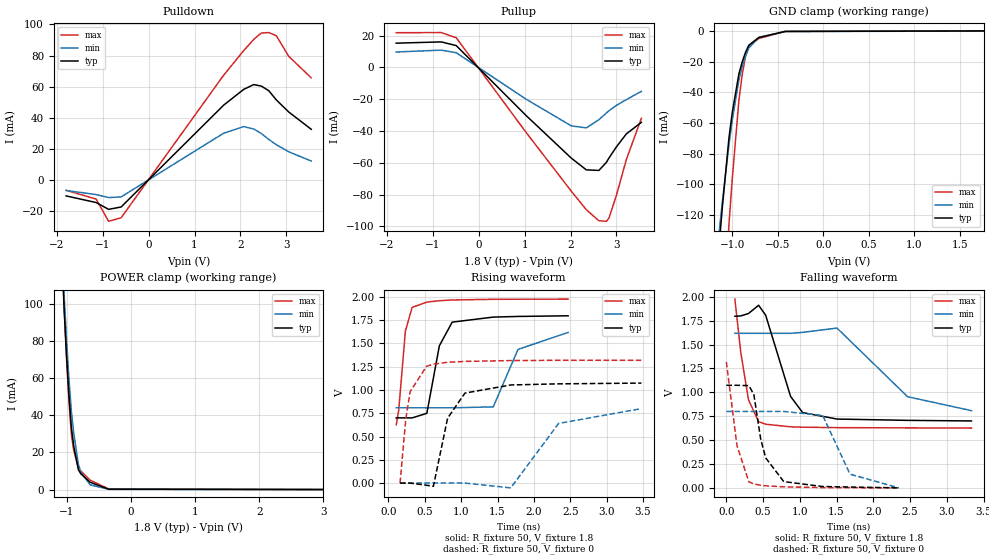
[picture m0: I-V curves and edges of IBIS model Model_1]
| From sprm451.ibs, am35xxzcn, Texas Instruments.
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| Model based on original model for BC1833DV40CTPBFHP18LL_7LM
|   Sub model HP18LL_7LM_PD_ON_1P8
[model]   Model_1
|[Description]  1.8V-I/O-PD-X
|[Input Load]   PD
|[Output Drive]
|Voltage   1.8V
|Mode   I/O
Model_type   I/O
Polarity   Non-Inverting
Enable   Active-Low
Vinl =  0.63V
Vinh =  1.17V
Cref =  15pF
Rref =  100.0000M
Vref =  0V
Vmeas =  0.9
C_comp   2.232809p   2.073051p   2.295852p
[Model Spec]
Vinl   0.63V   0.567V   0.693V
Vinh   1.17V   1.053V   1.287V
[Temperature Range]   25   125   -40
[Voltage Range]   1.8   1.62   1.98
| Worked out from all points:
|   slope of the pulldown table from 0 to 0.27 V, typ, clamps not added: 31.5 ohm
|   slope of the pullup table from 0 to 0.27 V, typ, clamps not added: 33.5 ohm
|   GND clamp passes 1 mA (typ) near -0.54 V on its own axis
|   POWER clamp passes 1 mA (typ) near -0.48 V on its own axis
|   rising waveform, R_fixture 50, V_fixture 1.8: 20-80 % time 168ps typ, 247ps min, 94.3ps max; typ from 0.701 V to 1.8 V
|   rising waveform, R_fixture 50, V_fixture 0: 20-80 % time 225ps typ, 472ps min, 131ps max; typ from 0 V to 1.07 V
|   falling waveform, R_fixture 50, V_fixture 1.8: 20-80 % time 282ps typ, 646ps min, 154ps max; typ from 1.8 V to 0.701 V
|   falling waveform, R_fixture 50, V_fixture 0: 20-80 % time 201ps typ, 246ps min, 144ps max; typ from 1.07 V to 0 V
[POWER_clamp]
-1.8V     842.4mA    869.2mA    912.8mA
-1.073V   123.6mA    130.9mA    129mA
-1.036V   94.8mA     102.9mA    96.52mA
-1V       70.82mA    79.68mA    69.62mA
-963.6mV  50.42mA    59.5mA     47.43mA
-927.3mV  33.6mA     42.32mA    29.95mA
-890.9mV  23.68mA    30.78mA    21.23mA
-818.2mV  10.84mA    13.86mA    11.65mA
-781.8mV  8.6mA      9.562mA    10.12mA
-636.4mV  3.971mA    2.6mA      5.151mA
-345.5mV  233.4uA    144.1uA    344.8uA
3.6V      0A         0A         0A
[Pulldown]
-1.8V     -10.48mA   -6.986mA   -6.871mA
-1.145V   -14.76mA   -9.635mA   -12.53mA
-872.7mV  -19.16mA   -11.57mA   -26.86mA
-600mV    -17.63mA   -11.14mA   -24.6mA
1.636V    48.02mA    29.94mA    67.34mA
2.073V    58.18mA    34.17mA    83.16mA
2.291V    61.26mA    32.65mA    90.37mA
2.455V    60.31mA    29.78mA    94.52mA
2.618V    57.35mA    25.94mA    94.79mA
2.782V    51.42mA    22.55mA    92.8mA
3.055V    43.58mA    17.93mA    79.45mA
3.545V    32.44mA    11.99mA    65.6mA
[Pullup]
-1.8V     15.25mA    9.689mA    21.84mA
-818.2mV  16.04mA    10.87mA    21.92mA
-490.9mV  13.71mA    9.212mA    18.64mA
1.036V    -30.4mA    -20.07mA   -41.09mA
2.018V    -57.11mA   -36.81mA   -77.94mA
2.345V    -64.48mA   -38.06mA   -89.56mA
2.618V    -64.84mA   -32.95mA   -96.49mA
2.782V    -59.78mA   -28.7mA    -96.85mA
2.836V    -57.13mA   -27.34mA   -95.02mA
3V        -50.06mA   -23.92mA   -80.63mA
3.218V    -41.82mA   -20.26mA   -57.92mA
3.545V    -34.58mA   -15.09mA   -32.06mA
[GND_clamp]
-1.8V     -697.8mA   -553.2mA   -1.259A
-1.145V   -140.7mA   -131.7mA   -248.3mA
-1.109V   -115.1mA   -111.6mA   -203.3mA
-1.036V   -69.61mA   -74.07mA   -125.9mA
-1V       -53.18mA   -58.25mA   -96.53mA
-927.3mV  -27.97mA   -31.86mA   -45.36mA
-890.9mV  -20.15mA   -23.34mA   -28.45mA
-854.5mV  -13.89mA   -16.39mA   -16.55mA
-818.2mV  -9.202mA   -11.02mA   -9.655mA
-709.1mV  -4.178mA   -4.041mA   -4.8mA
-418.2mV  -167.7uA   -232.8uA   -162.2uA
1.764V    148.6uA    81.78uA    236.4uA
[Ramp]
dV/dt_f 0.72573481/0.29560081n 0.53569302/0.67555475n 0.88861394/0.16164786n
dV/dt_r 0.67824841/0.22489373n 0.51280373/0.47254638n 0.81071552/0.13099315n
R_load = 50
[Rising Waveform]
R_fixture = 50
V_fixture = 1.8
V_fixture_min = 1.62
V_fixture_max = 1.98
106.8ps   700.5mV    808.2mV    625.6mV
140.8ps   700.5mV    808.2mV    778mV
233.1ps   700.6mV    808.2mV    1.632V
325.1ps   700mV      808.2mV    1.887V
528.1ps   749.6mV    808.2mV    1.944V
700.1ps   1.475V     808.2mV    1.959V
876.5ps   1.729V     808.2mV    1.967V
1.441ns   1.783V     818.9mV    1.974V
1.781ns   1.79V      1.436V     1.975V
2.47ns    1.797V     1.618V     1.976V
[Rising Waveform]
R_fixture = 50
V_fixture = 0
V_fixture_min = 0
V_fixture_max = 0
159.8ps   9.235nV    99.72nV    8.891nV
238ps     20.47uV    2.982uV    683.5mV
298.9ps   -444uV     1.923uV    982.8mV
525ps     -23.12mV   -556.3nV   1.255V
617.8ps   -34.89mV   30.45nV    1.277V
813.8ps   698.5mV    -1.58uV    1.298V
1.052ns   966.7mV    -195.9uV   1.307V
1.682ns   1.054V     -51.29mV   1.316V
2.339ns   1.066V     640.6mV    1.319V
3.477ns   1.074V     799.9mV    1.319V
[Falling Waveform]
R_fixture = 50
V_fixture = 1.8
V_fixture_min = 1.62
V_fixture_max = 1.98
116.4ps   1.797V     1.618V     1.976V
196.1ps   1.8V       1.618V     1.422V
300.8ps   1.825V     1.618V     923.4mV
439.3ps   1.912V     1.618V     693.4mV
535.4ps   1.807V     1.618V     666.2mV
874.3ps   957.4mV    1.618V     639mV
1.038ns   788mV      1.628V     635.3mV
1.506ns   720.5mV    1.673V     630.5mV
2.466ns   706.7mV    954.5mV    628.1mV
3.336ns   700.5mV    808.2mV    625.6mV
[Falling Waveform]
R_fixture = 50
V_fixture = 0
V_fixture_min = 0
V_fixture_max = 0
0s        1.074V     799.9mV    1.319V
145.1ps   1.074V     799.9mV    440.9mV
307.1ps   1.07V      799.9mV    62.25mV
374.5ps   976.4mV    799.9mV    41.47mV
466.4ps   516.4mV    799.9mV    27.62mV
535ps     314.5mV    799.9mV    21.5mV
781.5ps   65.48mV    799.9mV    10.9mV
1.311ns   14.01mV    758.7mV    2.742mV
1.683ns   8.619mV    143.3mV    921.5uV
2.347ns   9.235nV    99.72nV    8.891nV
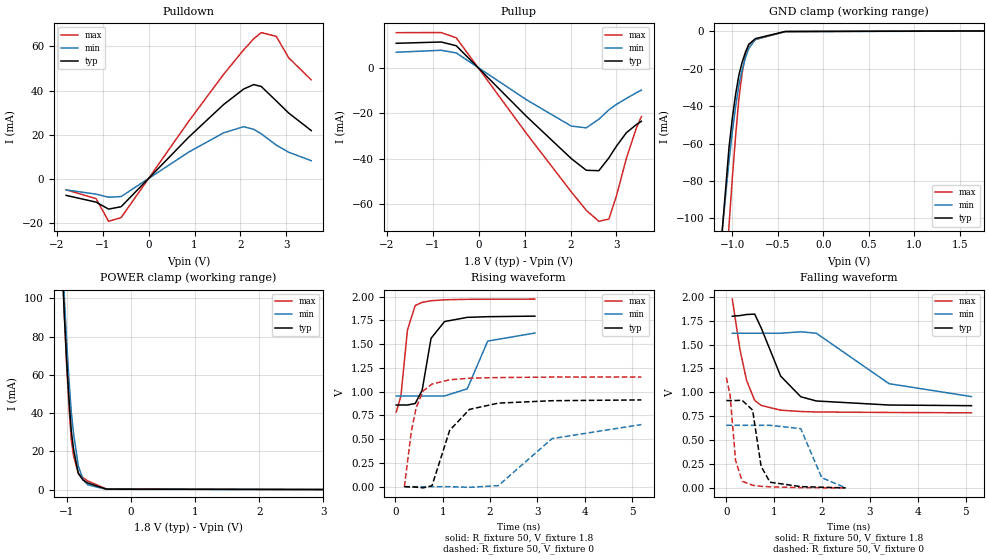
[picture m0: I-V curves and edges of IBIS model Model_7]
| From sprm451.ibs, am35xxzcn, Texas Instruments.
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| Model based on original model for BC1833DV50BTPBFZP18LL_7LM
|   Sub model ZP18LL_7LM_PD_ON_1P8
[model]   Model_7
|[Description]  1.8V-I/O-PD-X
|[Input Load]   PD
|[Output Drive]
|Voltage   1.8V
|Mode   I/O
Model_type   I/O
Polarity   Non-Inverting
Enable   Active-Low
Vinl =  0.63V
Vinh =  1.17V
Cref =  15pF
Rref =  100.0000M
Vref =  0V
Vmeas =  0.9
C_comp   1.952094p   1.82457p   1.99685p
[Model Spec]
Vinl   0.63V   0.567V   0.693V
Vinh   1.17V   1.053V   1.287V
[Temperature Range]   25   125   -40
[Voltage Range]   1.8   1.62   1.98
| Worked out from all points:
|   slope of the pulldown table from 0 to 0.27 V, typ, clamps not added: 44.6 ohm
|   slope of the pullup table from 0 to 0.27 V, typ, clamps not added: 47.6 ohm
|   GND clamp passes 1 mA (typ) near -0.57 V on its own axis
|   POWER clamp passes 1 mA (typ) near -0.50 V on its own axis
|   rising waveform, R_fixture 50, V_fixture 1.8: 20-80 % time 215ps typ, 285ps min, 155ps max; typ from 0.86 V to 1.8 V
|   rising waveform, R_fixture 50, V_fixture 0: 20-80 % time 445ps typ, 984ps min, 246ps max; typ from 0 V to 0.914 V
|   falling waveform, R_fixture 50, V_fixture 1.8: 20-80 % time 529ps typ, 1.21ns min, 284ps max; typ from 1.8 V to 0.86 V
|   falling waveform, R_fixture 50, V_fixture 0: 20-80 % time 163ps typ, 254ps min, 124ps max; typ from 0.914 V to 0 V
[POWER_clamp]
-1.8V     833.5mA    863.2mA    901.5mA
-1.073V   119.6mA    128.2mA    123.8mA
-1.036V   90.99mA    100.3mA    91.56mA
-1V       67.21mA    77.3mA     64.92mA
-963.6mV  47.03mA    57.27mA    42.99mA
-927.3mV  30.43mA    40.25mA    25.78mA
-890.9mV  20.75mA    28.88mA    17.36mA
-818.2mV  8.417mA    12.3mA     8.465mA
-745.5mV  5.011mA    5.192mA    6.262mA
-672.7mV  3.472mA    2.533mA    4.531mA
-381.8mV  258uA      159.8uA    367.6uA
3.6V      0A         0A         0A
[Pulldown]
-1.8V     -7.339mA   -4.872mA   -4.803mA
-1.145V   -10.39mA   -6.769mA   -8.819mA
-872.7mV  -13.54mA   -8.159mA   -19.05mA
-600mV    -12.46mA   -7.873mA   -17.38mA
872.7mV   18.95mA    12.21mA    26.11mA
1.636V    33.73mA    20.94mA    47.4mA
2.073V    40.73mA    23.7mA     58.46mA
2.291V    42.72mA    22.53mA    63.43mA
2.455V    41.87mA    20.47mA    66.23mA
2.782V    35.36mA    15.4mA     64.52mA
3.055V    29.83mA    12.14mA    54.79mA
3.545V    21.95mA    8.339mA    44.87mA
[Pullup]
-1.8V     10.72mA    6.784mA    15.4mA
-818.2mV  11.29mA    7.651mA    15.44mA
-490.9mV  9.653mA    6.484mA    13.12mA
1.036V    -21.34mA   -14.06mA   -28.84mA
2.018V    -39.99mA   -25.69mA   -54.63mA
2.345V    -45.12mA   -26.45mA   -62.75mA
2.618V    -45.29mA   -22.66mA   -67.55mA
2.836V    -39.69mA   -18.55mA   -66.59mA
3V        -34.54mA   -16.15mA   -56.48mA
3.218V    -28.61mA   -13.52mA   -39.88mA
3.436V    -25.01mA   -11.02mA   -26.56mA
3.545V    -23.56mA   -9.84mA    -21.49mA
[GND_clamp]
-1.8V     -667.9mA   -536.4mA   -1.146A
-1.109V   -105.7mA   -105.8mA   -172.9mA
-1.036V   -62.17mA   -69.32mA   -103.8mA
-1V       -46.71mA   -54.02mA   -78.82mA
-963.6mV  -33.8mA    -40.46mA   -56.21mA
-927.3mV  -23.44mA   -28.63mA   -35.97mA
-890.9mV  -16.49mA   -20.59mA   -22.18mA
-854.5mV  -11.01mA   -14.09mA   -12.57mA
-818.2mV  -7.007mA   -9.141mA   -7.128mA
-745.5mV  -3.917mA   -4.386mA   -4.424mA
-418.2mV  -145.2uA   -181.7uA   -152.2uA
1.764V    148.6uA    81.64uA    236.4uA
[Ramp]
dV/dt_f 0.57820343/0.53321315n 0.41153382/1.2211474n 0.72337916/0.28337698n
dV/dt_r 0.56277196/0.44507689n 0.40444103/0.98176965n 0.70129767/0.24651408n
R_load = 50
[Rising Waveform]
R_fixture = 50
V_fixture = 1.8
V_fixture_min = 1.62
V_fixture_max = 1.98
20.99ps   860mV      955mV      785.5mV
120.2ps   860mV      955mV      955mV
258.7ps   859.9mV    955mV      1.651V
422.2ps   876.3mV    955mV      1.908V
567.8ps   1.014V     955mV      1.941V
755.8ps   1.562V     955mV      1.958V
1.041ns   1.739V     955.1mV    1.968V
1.52ns    1.783V     1.031V     1.973V
1.951ns   1.79V      1.533V     1.974V
2.947ns   1.796V     1.618V     1.975V
[Rising Waveform]
R_fixture = 50
V_fixture = 0
V_fixture_min = 0
V_fixture_max = 0
193.4ps   9.192nV    85.66nV    10.64nV
340.1ps   -2.557mV   2.165uV    583.1mV
442.4ps   -5.376mV   132.4nV    832.4mV
588.8ps   -12.42mV   -1.579uV   1.007V
775.2ps   9.464mV    -2.483uV   1.081V
1.149ns   593.3mV    -171.1uV   1.126V
1.568ns   814.2mV    -6.735mV   1.142V
2.176ns   879.9mV    11.46mV    1.149V
3.31ns    905.4mV    506.5mV    1.154V
5.193ns   913.5mV    654.1mV    1.154V
[Falling Waveform]
R_fixture = 50
V_fixture = 1.8
V_fixture_min = 1.62
V_fixture_max = 1.98
124.8ps   1.796V     1.618V     1.975V
284.6ps   1.803V     1.618V     1.448V
423.8ps   1.814V     1.618V     1.123V
593.8ps   1.818V     1.618V     914.3mV
731ps     1.671V     1.618V     862.3mV
1.135ns   1.17V      1.618V     813.1mV
1.557ns   953.1mV    1.633V     799mV
1.882ns   909.2mV    1.618V     794.1mV
3.402ns   866.8mV    1.09V      788.8mV
5.125ns   860mV      955mV      785.5mV
[Falling Waveform]
R_fixture = 50
V_fixture = 0
V_fixture_min = 0
V_fixture_max = 0
0s        913.5mV    654.1mV    1.154V
77.74ps   913.4mV    654.1mV    974.7mV
192.8ps   914.2mV    654.1mV    288.5mV
330.9ps   915.9mV    654.1mV    69.36mV
549.3ps   814mV      654.1mV    26.94mV
726.8ps   225.2mV    654.1mV    16.41mV
913ps     58.95mV    654.4mV    10.83mV
1.556ns   12.95mV    618.9mV    1.852mV
1.994ns   6.897mV    106.5mV    536.1uV
2.497ns   9.192nV    85.66nV    10.64nV
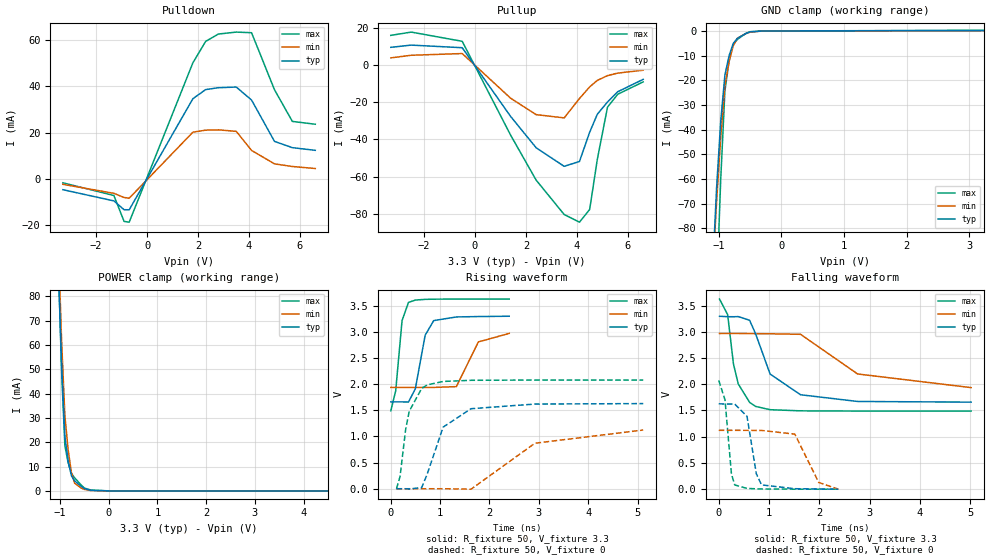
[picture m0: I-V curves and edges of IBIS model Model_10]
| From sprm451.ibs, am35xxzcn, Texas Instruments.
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| Model based on original model for BC1833DV50BTPBFZP18LL_7LM
|   Sub model ZP18LL_7LM_PD_ON_3P3
[model]   Model_10
|[Description]  3.3V-I/O-PD-X
|[Input Load]   PD
|[Output Drive]
|Voltage   3.3V
|Mode   I/O
Model_type   I/O
Polarity   Non-Inverting
Enable   Active-Low
Vinl =  0.8V
Vinh =  2V
Cref =  15pF
Rref =  100.0000M
Vref =  0V
Vmeas =  1.65
C_comp   1.683006p   1.492615p   1.787227p
[Model Spec]
Vinl   0.8V   0.8V   0.8V
Vinh   2V   2V   2V
[Temperature Range]   25   125   -40
[Voltage Range]   3.3   2.97   3.63
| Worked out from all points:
|   slope of the pulldown table from 0 to 0.495 V, typ, clamps not added: 44.6 ohm
|   slope of the pullup table from 0 to 0.495 V, typ, clamps not added: 49.2 ohm
|   GND clamp passes 1 mA (typ) near -0.56 V on its own axis
|   POWER clamp passes 1 mA (typ) near -0.50 V on its own axis
|   rising waveform, R_fixture 50, V_fixture 3.3: 20-80 % time 192ps typ, 277ps min, 121ps max; typ from 1.66 V to 3.3 V
|   rising waveform, R_fixture 50, V_fixture 0: 20-80 % time 427ps typ, 976ps min, 232ps max; typ from 0 V to 1.63 V
|   falling waveform, R_fixture 50, V_fixture 3.3: 20-80 % time 507ps typ, 1ns min, 228ps max; typ from 3.3 V to 1.66 V
|   falling waveform, R_fixture 50, V_fixture 0: 20-80 % time 153ps typ, 282ps min, 108ps max; typ from 1.63 V to 0 V
[POWER_clamp]
-3.3V     2.414A     2.855A     2.597A
-1.033V   91.38mA    100.8mA    92.09mA
-966.7mV  51.62mA    61.2mA     48.76mA
-900mV    22.31mA    30.86mA    18.57mA
-833.3mV  12.32mA    16.85mA    11.59mA
-766.7mV  6.266mA    7.628mA    7.19mA
-700mV    4.145mA    3.179mA    5.382mA
-566.7mV  1.918mA    1.21mA     2.445mA
-500mV    988.1uA    615.4uA    1.197mA
-366.7mV  251uA      160.8uA    340.6uA
33.33mV   0A         0A         0A
6.6V      0A         0A         0A
[Pulldown]
-3.3V     -4.655mA   -2.337mA   -1.677mA
-1.3V     -9.504mA   -6.223mA   -7.163mA
-900mV    -13.3mA    -8.026mA   -18.36mA
-700mV    -13.35mA   -8.345mA   -18.7mA
1.8V      34.68mA    20.21mA    50.21mA
2.3V      38.61mA    21.07mA    59.44mA
2.8V      39.41mA    21.2mA     62.61mA
3.5V      39.7mA     20.55mA    63.45mA
4.1V      34.08mA    12.32mA    63.18mA
5V        16.21mA    6.501mA    38.53mA
5.7V      13.51mA    5.366mA    24.85mA
6.6V      12.35mA    4.495mA    23.63mA
[Pullup]
-3.3V     9.687mA    4.009mA    16.14mA
-2.5V     10.89mA    5.407mA    17.91mA
-500mV    9.485mA    6.336mA    12.94mA
1.4V      -27.6mA    -17.76mA   -37.69mA
2.4V      -44.47mA   -26.6mA    -61.92mA
3.5V      -54.49mA   -28.37mA   -80.48mA
4.1V      -51.87mA   -17.91mA   -84.62mA
4.5V      -36.09mA   -11.65mA   -77.77mA
4.8V      -26.39mA   -8.135mA   -50.71mA
5.2V      -19.78mA   -5.578mA   -22.57mA
5.6V      -14.26mA   -4.206mA   -15.61mA
6.6V      -7.577mA   -2.662mA   -8.942mA
[GND_clamp]
-3.3V     -1.975A    -1.766A    -3.378A
-1.1V     -99.4mA    -100.8mA   -162mA
-1.033V   -63.74mA   -69.32mA   -106.1mA
-966.7mV  -36.57mA   -43.05mA   -60.18mA
-900mV    -17.89mA   -22.01mA   -24.33mA
-833.3mV  -10.02mA   -12.39mA   -12.36mA
-766.7mV  -5.065mA   -6.03mA    -5.397mA
-700mV    -3.03mA    -2.946mA   -3.429mA
-566.7mV  -1.071mA   -1.108mA   -1.034mA
-500mV    -408.8uA   -526.2uA   -330.7uA
-300mV    -30.43uA   -31.39uA   -39.7uA
3.233V    152.3uA    93.49uA    242.6uA
[Ramp]
dV/dt_f  0.9825446/0.50371119n 0.61884461/0.98346485n  1.2814013/0.22625728n
dV/dt_r 0.98086665/0.42362929n  0.6781094/0.97314198n   1.251215/0.23061983n
R_load = 50
[Rising Waveform]
R_fixture = 50
V_fixture = 3.3
V_fixture_min = 2.97
V_fixture_max = 3.63
613.4fs   1.659V     1.936V     1.489V
99.11ps   1.659V     1.936V     1.868V
228.5ps   1.659V     1.936V     3.213V
359.1ps   1.657V     1.936V     3.561V
497.8ps   1.91V      1.936V     3.605V
696.4ps   2.933V     1.936V     3.618V
870.1ps   3.213V     1.936V     3.622V
1.329ns   3.282V     1.951V     3.624V
1.774ns   3.29V      2.805V     3.624V
2.4ns     3.296V     2.968V     3.624V
[Rising Waveform]
R_fixture = 50
V_fixture = 0
V_fixture_min = 0
V_fixture_max = 0
115.3ps   7.935nV    106nV      4.134nV
188ps     4.843uV    -370.3nV   234.2mV
300.1ps   -248.5uV   -461.2nV   1.126V
373.2ps   -2.67mV    -60.64nV   1.479V
625.5ps   20.96mV    144.5nV    1.916V
738.1ps   279.9mV    9.941nV    1.984V
1.061ns   1.178V     25.17uV    2.05V
1.627ns   1.529V     -8.018mV   2.072V
2.921ns   1.618V     869.5mV    2.077V
5.115ns   1.627V     1.122V     2.076V
[Falling Waveform]
R_fixture = 50
V_fixture = 3.3
V_fixture_min = 2.97
V_fixture_max = 3.63
15.81ps   3.296V     2.968V     3.624V
177.4ps   3.288V     2.968V     3.327V
292.3ps   3.287V     2.968V     2.388V
387.8ps   3.29V      2.968V     2.006V
613.7ps   3.22V      2.966V     1.655V
733.8ps   2.96V      2.964V     1.577V
1.021ns   2.194V     2.962V     1.515V
1.626ns   1.8V       2.952V     1.493V
2.76ns    1.672V     2.196V     1.489V
5.016ns   1.659V     1.936V     1.489V
[Falling Waveform]
R_fixture = 50
V_fixture = 0
V_fixture_min = 0
V_fixture_max = 0
0s        1.627V     1.122V     2.076V
124.2ps   1.623V     1.122V     1.704V
252.7ps   1.623V     1.122V     288.7mV
318.3ps   1.623V     1.122V     80.41mV
562.2ps   1.388V     1.121V     14.58mV
746.4ps   297.2mV    1.12V      6.518mV
849.5ps   81.65mV    1.12V      3.807mV
1.512ns   8.88mV     1.049V     121.1uV
1.987ns   3.244mV    128.1mV    14.14uV
2.377ns   7.935nV    106nV      4.134nV
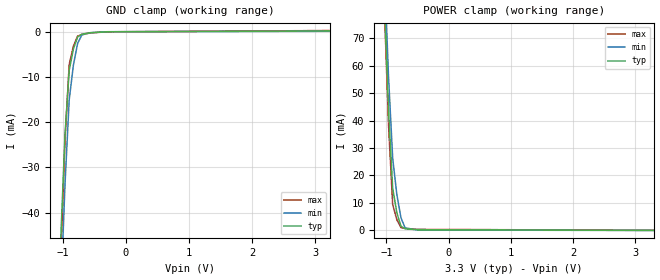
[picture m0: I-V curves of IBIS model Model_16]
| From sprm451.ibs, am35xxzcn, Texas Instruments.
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| Model based on original model for IC1833DVTPBFZP18LL_7LM
|   Sub model 7LM_!PI_!PUPDSEL_3P3
[model]   Model_16
|[Description]  3.3V-INPUT-PD-X
|[Input Load]   PD
|[Output Drive]
|Voltage   3.3V
|Mode   INPUT
Model_type   Input
Polarity   Non-Inverting
Vinl =  0.8V
Vinh =  2V
C_comp   1.012258p   0.8890016p   1.091755p
[Model Spec]
Vinl   0.8V   0.8V   0.8V
Vinh   2V   2V   2V
[Temperature Range]   25   125   -40
[Voltage Range]   3.3   2.97   3.63
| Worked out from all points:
|   GND clamp passes 1 mA (typ) near -0.75 V on its own axis
|   POWER clamp passes 1 mA (typ) near -0.73 V on its own axis
[POWER_clamp]
-3.3V     2.37A      2.826A     2.542A
-1.033V   82.55mA    94.89mA    80.63mA
-966.7mV  43.74mA    56mA       38.47mA
-900mV    15.37mA    26.34mA    9.443mA
-833.3mV  6.477mA    13.09mA    3.921mA
-766.7mV  1.541mA    4.609mA    1.021mA
-700mV    560.4uA    907.9uA    743.2uA
-500mV    249.8uA    143.8uA    371.7uA
3.3V      -147.5pA   -31.33uA   27.53uA
[GND_clamp]
-3.3V     -1.792A    -1.668A    -2.631A
-1.033V   -45.54mA   -57.75mA   -50.28mA
-966.7mV  -22.83mA   -33.82mA   -24.05mA
-900mV    -8.522mA   -15.05mA   -7.278mA
-833.3mV  -3.829mA   -7.369mA   -3.202mA
-766.7mV  -1.175mA   -2.599mA   -991.4uA
-700mV    -560.2uA   -745.4uA   -646.9uA
-566.7mV  -249.1uA   -233.9uA   -286.4uA
-300mV    -29.03uA   -23.37uA   -39.39uA
3.233V    152.3uA    84.63uA    242.6uA
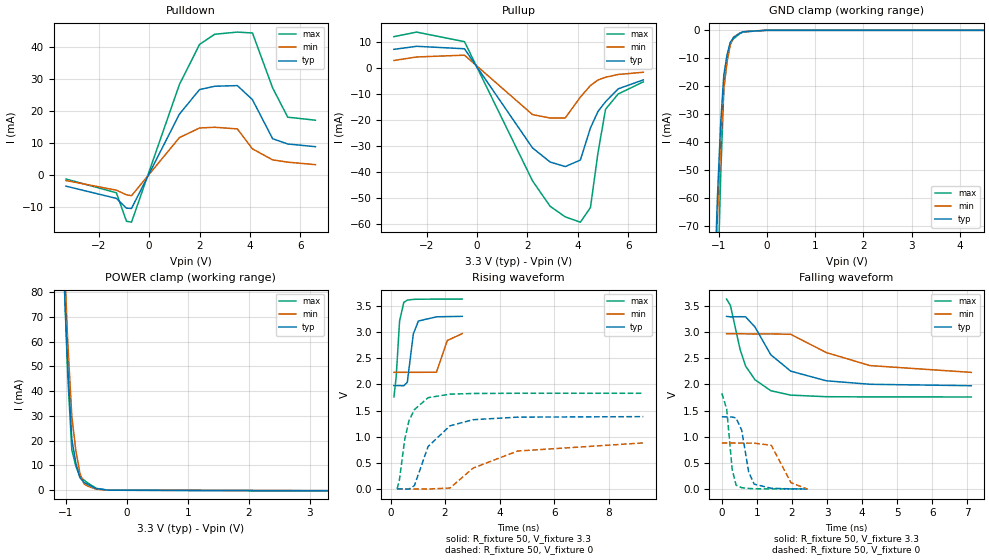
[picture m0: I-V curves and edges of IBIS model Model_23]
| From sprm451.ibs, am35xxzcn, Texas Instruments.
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| Model based on original model for BC1833DV65ATPBFHP18LL_7LM_X50
|   Sub model LL_7LM_X50_PU_ON_3P3
[model]   Model_23
|[Description]  3.3V-I/O-PU-X
|[Input Load]   PU
|[Output Drive]
|Voltage   3.3V
|Mode   I/O
Model_type   I/O
Polarity   Non-Inverting
Enable   Active-Low
Vinl =  0.8V
Vinh =  2V
Cref =  15pF
Rref =  100.0000M
Vref =  0V
Vmeas =  1.65
C_comp   1.569055p   1.388637p   1.6677p
[Model Spec]
Vinl   0.8V   0.8V   0.8V
Vinh   2V   2V   2V
[Temperature Range]   25   125   -40
[Voltage Range]   3.3   2.97   3.63
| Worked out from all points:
|   slope of the pulldown table from 0 to 0.495 V, typ, clamps not added: 57.2 ohm
|   slope of the pullup table from 0 to 0.495 V, typ, clamps not added: 64.6 ohm
|   GND clamp passes 1 mA (typ) near -0.56 V on its own axis
|   POWER clamp passes 1 mA (typ) near -0.53 V on its own axis
|   rising waveform, R_fixture 50, V_fixture 3.3: 20-80 % time 188ps typ, 267ps min, 136ps max; typ from 1.98 V to 3.3 V
|   rising waveform, R_fixture 50, V_fixture 0: 20-80 % time 836ps typ, 1.93ns min, 444ps max; typ from 0.005 V to 1.39 V
|   falling waveform, R_fixture 50, V_fixture 3.3: 20-80 % time 1.01ns typ, 1.63ns min, 553ps max; typ from 3.3 V to 1.98 V
|   falling waveform, R_fixture 50, V_fixture 0: 20-80 % time 210ps typ, 357ps min, 143ps max; typ from 1.39 V to 0.005 V
[POWER_clamp]
-3.3V     2.404A     2.849A     2.585A
-1.033V   89.24mA    99.32mA    89.3mA
-966.7mV  49.69mA    59.91mA    46.23mA
-900mV    20.59mA    29.73mA    16.29mA
-833.3mV  10.84mA    15.9mA     9.63mA
-766.7mV  5.043mA    6.847mA    5.566mA
-700mV    3.181mA    2.571mA    4.1mA
-633.3mV  2.248mA    1.617mA    2.875mA
-500mV    675.7uA    429.5uA    770.8uA
-300mV    22.84uA    18.84uA    28.19uA
3.3V      -177.5uA   -131.7uA   -277.3uA
[Pulldown]
-3.3V     -3.482mA   -1.731mA   -1.253mA
-1.3V     -7.3mA     -4.736mA   -5.547mA
-900mV    -10.35mA   -6.182mA   -14.42mA
-700mV    -10.42mA   -6.462mA   -14.71mA
1.2V      18.95mA    11.64mA    28.17mA
2V        26.61mA    14.65mA    40.68mA
2.6V      27.65mA    14.87mA    43.85mA
3.5V      27.86mA    14.36mA    44.53mA
4.1V      23.47mA    8.141mA    44.25mA
4.9V      11.31mA    4.711mA    27.15mA
5.5V      9.66mA     3.997mA    18.01mA
6.6V      8.818mA    3.224mA    17.07mA
[Pullup]
-3.3V     7.018mA    2.752mA    11.89mA
-2.4V     8.195mA    4.095mA    13.65mA
-500mV    7.249mA    4.793mA    9.977mA
2.2V      -30.8mA    -18.02mA   -43.45mA
2.9V      -36.22mA   -19.34mA   -53.21mA
3.5V      -37.97mA   -19.31mA   -57.28mA
4.1V      -35.47mA   -11.3mA    -59.32mA
4.5V      -23.14mA   -6.857mA   -53.72mA
4.8V      -16.8mA    -4.734mA   -32.6mA
5.1V      -13.06mA   -3.688mA   -15.95mA
5.6V      -8.137mA   -2.623mA   -10.11mA
6.6V      -4.691mA   -1.758mA   -5.452mA
[GND_clamp]
-3.3V     -1.939A    -1.746A    -3.236A
-1.1V     -94.85mA   -97.92mA   -147.6mA
-1.033V   -60.11mA   -66.92mA   -95.49mA
-966.7mV  -33.84mA   -41.13mA   -53.35mA
-900mV    -16.04mA   -20.57mA   -21.16mA
-833.3mV  -8.82mA    -11.35mA   -10.72mA
-766.7mV  -4.347mA   -5.329mA   -4.693mA
-700mV    -2.622mA   -2.512mA   -3.078mA
-566.7mV  -1.044mA   -980.6uA   -1.151mA
-500mV    -516.4uA   -513.3uA   -592uA
-33.33mV  0A         0A         0A
6.6V      0A         0A         0A
[Ramp]
dV/dt_f 0.79376008/1.0080993n 0.44324543/1.6259422n  1.1206463/0.55232791n
dV/dt_r 0.83122681/0.83531775n 0.53087089/1.9016899n  1.0976582/0.44436463n
R_load = 50
[Rising Waveform]
R_fixture = 50
V_fixture = 3.3
V_fixture_min = 2.97
V_fixture_max = 3.63
124.5ps   1.977V     2.231V     1.762V
206ps     1.977V     2.231V     2.132V
331.8ps   1.977V     2.231V     3.209V
486.3ps   1.975V     2.231V     3.566V
616.1ps   2.04V      2.231V     3.609V
835.8ps   2.962V     2.231V     3.624V
1.021ns   3.211V     2.231V     3.627V
1.686ns   3.291V     2.234V     3.629V
2.081ns   3.295V     2.838V     3.63V
2.629ns   3.3V       2.97V      3.63V
[Rising Waveform]
R_fixture = 50
V_fixture = 0
V_fixture_min = 0
V_fixture_max = 0
239.7ps   4.68mV     2.797mV    6.834mV
322.9ps   4.68mV     2.797mV    164.6mV
523.5ps   3.282mV    2.797mV    956.5mV
675.8ps   -302.1uV   2.797mV    1.305V
876.4ps   68.58mV    2.797mV    1.52V
1.378ns   813.9mV    2.658mV    1.747V
2.182ns   1.21V      21.49mV    1.814V
3.026ns   1.326V     401.6mV    1.827V
4.659ns   1.375V     728mV      1.831V
9.272ns   1.385V     883mV      1.831V
[Falling Waveform]
R_fixture = 50
V_fixture = 3.3
V_fixture_min = 2.97
V_fixture_max = 3.63
134.5ps   3.3V       2.97V      3.63V
243.7ps   3.29V      2.97V      3.511V
521.4ps   3.294V     2.969V     2.667V
677.8ps   3.291V     2.966V     2.351V
945.4ps   3.096V     2.964V     2.09V
1.394ns   2.568V     2.966V     1.882V
1.965ns   2.254V     2.957V     1.797V
2.975ns   2.071V     2.61V      1.767V
4.22ns    2.004V     2.361V     1.763V
7.11ns    1.977V     2.231V     1.762V
[Falling Waveform]
R_fixture = 50
V_fixture = 0
V_fixture_min = 0
V_fixture_max = 0
0s        1.385V     883mV      1.831V
138.9ps   1.381V     883mV      1.532V
294.5ps   1.38V      883.1mV    379.8mV
406.7ps   1.36V      882.6mV    80.15mV
566.9ps   1.127V     881.8mV    30mV
764.5ps   331.8mV    881.1mV    16.47mV
919.8ps   99.81mV    881.2mV    11.2mV
1.41ns    19.4mV     840.4mV    7.219mV
1.97ns    8.521mV    126.9mV    6.872mV
2.447ns   4.68mV     2.797mV    6.834mV
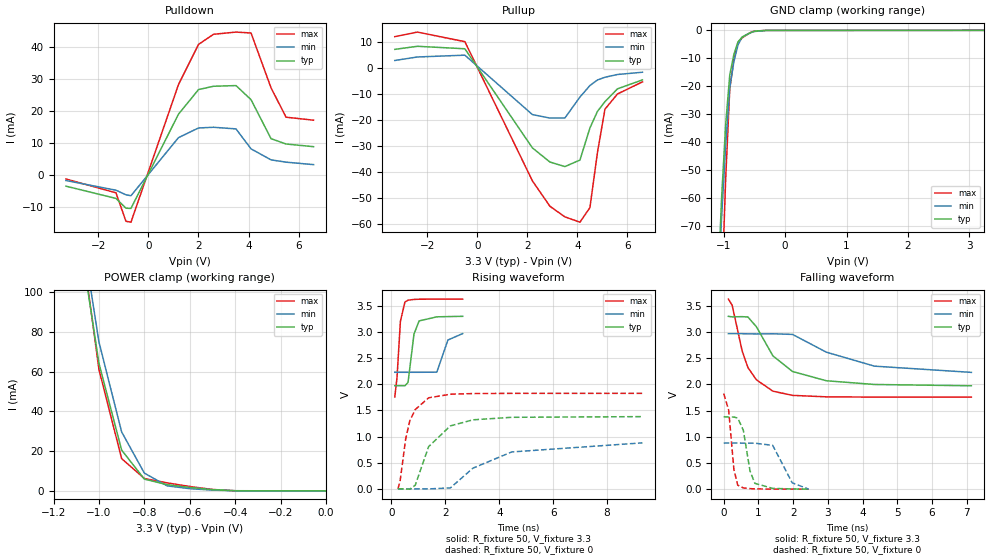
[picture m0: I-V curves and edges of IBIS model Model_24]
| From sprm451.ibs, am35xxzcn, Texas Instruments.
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| Model based on original model for BC1833DV65ATPBFHP18LL_7LM_X50
|   Sub model LM_X50_PD_PU_OFF_3P3
[model]   Model_24
|[Description]  3.3V-I/O-PI-X
|[Input Load]   PI
|[Output Drive]
|Voltage   3.3V
|Mode   I/O
Model_type   I/O
Polarity   Non-Inverting
Enable   Active-Low
Vinl =  0.8V
Vinh =  2V
Cref =  15pF
Rref =  100.0000M
Vref =  0V
Vmeas =  1.65
C_comp   1.569055p   1.388637p   1.6677p
[Model Spec]
Vinl   0.8V   0.8V   0.8V
Vinh   2V   2V   2V
[Temperature Range]   25   125   -40
[Voltage Range]   3.3   2.97   3.63
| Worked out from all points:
|   slope of the pulldown table from 0 to 0.495 V, typ, clamps not added: 57.2 ohm
|   slope of the pullup table from 0 to 0.495 V, typ, clamps not added: 64.6 ohm
|   GND clamp passes 1 mA (typ) near -0.58 V on its own axis
|   POWER clamp passes 1 mA (typ) near -0.53 V on its own axis
|   rising waveform, R_fixture 50, V_fixture 3.3: 20-80 % time 189ps typ, 268ps min, 136ps max; typ from 1.97 V to 3.3 V
|   rising waveform, R_fixture 50, V_fixture 0: 20-80 % time 841ps typ, 1.91ns min, 448ps max; typ from 0 V to 1.38 V
|   falling waveform, R_fixture 50, V_fixture 3.3: 20-80 % time 1.01ns typ, 1.64ns min, 553ps max; typ from 3.3 V to 1.97 V
|   falling waveform, R_fixture 50, V_fixture 0: 20-80 % time 210ps typ, 357ps min, 143ps max; typ from 1.38 V to 0 V
[POWER_clamp]
-3.3V     2.404A     2.849A     2.585A
-1.067V   114.2mA    123.6mA    117.4mA
-1.033V   89.22mA    99.31mA    89.28mA
-1V       64.23mA    74.99mA    61.18mA
-900mV    20.57mA    29.72mA    16.26mA
-800mV    5.954mA    8.975mA    6.268mA
-700mV    3.161mA    2.56mA     4.067mA
-600mV    1.76mA     1.128mA    2.228mA
-500mV    654.7uA    418.2uA    736.2uA
-400mV    102.9uA    85.38uA    80.17uA
0V        9.32nA     42.2nA     36.62nA
[Pulldown]
-3.3V     -3.482mA   -1.731mA   -1.253mA
-1.3V     -7.299mA   -4.736mA   -5.547mA
-900mV    -10.35mA   -6.182mA   -14.42mA
-700mV    -10.42mA   -6.462mA   -14.71mA
1.2V      18.95mA    11.64mA    28.17mA
2V        26.61mA    14.65mA    40.68mA
2.6V      27.65mA    14.87mA    43.85mA
3.5V      27.86mA    14.36mA    44.53mA
4.1V      23.47mA    8.141mA    44.25mA
4.9V      11.31mA    4.711mA    27.15mA
5.5V      9.66mA     3.997mA    18.01mA
6.6V      8.818mA    3.224mA    17.07mA
[Pullup]
-3.3V     7.018mA    2.752mA    11.89mA
-2.4V     8.195mA    4.095mA    13.65mA
-500mV    7.249mA    4.793mA    9.977mA
2.2V      -30.8mA    -18.02mA   -43.45mA
2.9V      -36.22mA   -19.34mA   -53.21mA
3.5V      -37.97mA   -19.31mA   -57.28mA
4.1V      -35.47mA   -11.3mA    -59.32mA
4.5V      -23.14mA   -6.857mA   -53.71mA
4.8V      -16.8mA    -4.734mA   -32.6mA
5.1V      -13.06mA   -3.688mA   -15.95mA
5.6V      -8.137mA   -2.623mA   -10.11mA
6.6V      -4.691mA   -1.758mA   -5.452mA
[GND_clamp]
-3.3V     -1.939A    -1.746A    -3.236A
-1.1V     -94.77mA   -97.88mA   -147.5mA
-1.033V   -60mA      -66.87mA   -95.35mA
-966.7mV  -33.71mA   -41.08mA   -53.17mA
-900mV    -15.89mA   -20.5mA    -20.9mA
-833.3mV  -8.644mA   -11.27mA   -10.41mA
-766.7mV  -4.155mA   -5.24mA    -4.355mA
-700mV    -2.422mA   -2.415mA   -2.734mA
-566.7mV  -842.1uA   -880.6uA   -805.8uA
-500mV    -315uA     -413uA     -247.5uA
-300mV    -13.91uA   -20.32uA   -14.31uA
3.233V    8.994nA    8.034uA    33.58nA
[Ramp]
dV/dt_f 0.79552329/1.0111088n 0.44388419/1.6293742n  1.1232704/0.55237363n
dV/dt_r 0.83215258/0.84027246n 0.53104946/1.9078305n  1.0994342/0.44778931n
R_load = 50
[Rising Waveform]
R_fixture = 50
V_fixture = 3.3
V_fixture_min = 2.97
V_fixture_max = 3.63
124.6ps   1.974V     2.23V      1.758V
207.3ps   1.974V     2.23V      2.134V
331.9ps   1.974V     2.23V      3.203V
499.4ps   1.972V     2.23V      3.572V
616.1ps   2.037V     2.23V      3.608V
835.9ps   2.959V     2.23V      3.623V
1.026ns   3.212V     2.23V      3.627V
1.683ns   3.29V      2.232V     3.629V
2.095ns   3.295V     2.847V     3.63V
2.642ns   3.3V       2.97V      3.63V
[Rising Waveform]
R_fixture = 50
V_fixture = 0
V_fixture_min = 0
V_fixture_max = 0
240.3ps   8.025nV    103.4nV    4.167nV
320.5ps   -166.1nV   -63.55nV   147.4mV
527.2ps   -1.449mV   27.46nV    955.3mV
681.7ps   -5.02mV    -242.9pV   1.304V
882.7ps   69.95mV    153.9nV    1.517V
1.379ns   807.8mV    -141.9uV   1.742V
2.185ns   1.205V     18.72mV    1.81V
3.024ns   1.321V     396.9mV    1.823V
4.463ns   1.369V     706.8mV    1.827V
9.314ns   1.382V     880.5mV    1.827V
[Falling Waveform]
R_fixture = 50
V_fixture = 3.3
V_fixture_min = 2.97
V_fixture_max = 3.63
134.4ps   3.3V       2.97V      3.63V
243.7ps   3.29V      2.97V      3.511V
532ps     3.294V     2.969V     2.638V
697ps     3.288V     2.966V     2.323V
940.9ps   3.102V     2.964V     2.089V
1.418ns   2.545V     2.967V     1.871V
1.983ns   2.247V     2.955V     1.791V
2.956ns   2.07V      2.616V     1.763V
4.342ns   1.999V     2.349V     1.758V
7.134ns   1.974V     2.23V      1.758V
[Falling Waveform]
R_fixture = 50
V_fixture = 0
V_fixture_min = 0
V_fixture_max = 0
0s        1.382V     880.5mV    1.827V
142.7ps   1.378V     880.5mV    1.51V
293.7ps   1.377V     880.5mV    377.8mV
403.5ps   1.358V     880mV      76.91mV
566.2ps   1.125V     879.3mV    24.12mV
757.2ps   349.3mV    878.5mV    10.5mV
897.8ps   111.1mV    878.6mV    5.201mV
1.412ns   15.28mV    836.4mV    426uV
1.972ns   4.394mV    122.7mV    40.19uV
2.447ns   8.025nV    103.4nV    4.167nV
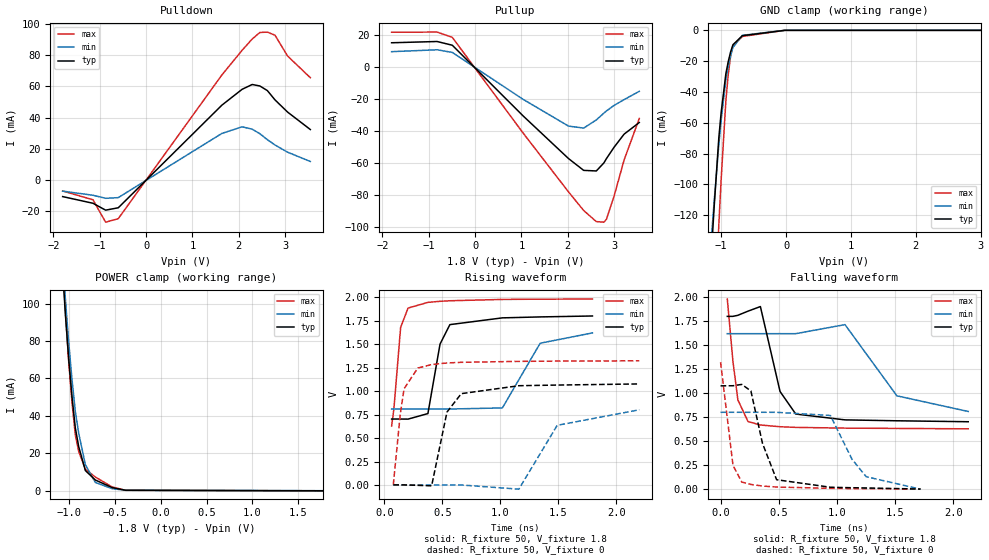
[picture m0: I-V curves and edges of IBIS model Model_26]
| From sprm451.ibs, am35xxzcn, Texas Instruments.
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| Model based on original model for BQ1833DV40DTPBFHP18LL_7LM
|   Sub model HP18LL_7LM_PU_ON_1P8
[model]   Model_26
|[Description]  1.8V-I/O-PU-X
|[Input Load]   PU
|[Output Drive]
|Voltage   1.8V
|Mode   I/O
Model_type   I/O
Polarity   Non-Inverting
Enable   Active-Low
Vinl =  0.63V
Vinh =  1.17V
Cref =  15pF
Rref =  100.0000M
Vref =  0V
Vmeas =  0.9
C_comp   2.161439p   2.02467p   2.204523p
[Model Spec]
Vinl   0.63V   0.567V   0.693V
Vinh   1.17V   1.053V   1.287V
[Temperature Range]   25   125   -40
[Voltage Range]   1.8   1.62   1.98
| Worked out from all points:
|   slope of the pulldown table from 0 to 0.27 V, typ, clamps not added: 31.5 ohm
|   slope of the pullup table from 0 to 0.27 V, typ, clamps not added: 33.5 ohm
|   GND clamp passes 1 mA (typ) near -0.53 V on its own axis
|   POWER clamp passes 1 mA (typ) near -0.49 V on its own axis
|   rising waveform, R_fixture 50, V_fixture 1.8: 20-80 % time 93.5ps typ, 189ps min, 56.4ps max; typ from 0.703 V to 1.8 V
|   rising waveform, R_fixture 50, V_fixture 0: 20-80 % time 125ps typ, 244ps min, 75.4ps max; typ from 0.003 V to 1.08 V
|   falling waveform, R_fixture 50, V_fixture 1.8: 20-80 % time 133ps typ, 278ps min, 75.6ps max; typ from 1.8 V to 0.703 V
|   falling waveform, R_fixture 50, V_fixture 0: 20-80 % time 135ps typ, 207ps min, 71.2ps max; typ from 1.08 V to 0.003 V
[POWER_clamp]
-1.8V     842.2mA    869.2mA    912.6mA
-1.073V   123.5mA    130.8mA    128.8mA
-1.036V   94.66mA    102.8mA    96.27mA
-1V       70.68mA    79.61mA    69.37mA
-963.6mV  50.27mA    59.42mA    47.18mA
-927.3mV  33.45mA    42.25mA    29.69mA
-890.9mV  23.53mA    30.71mA    20.96mA
-818.2mV  10.69mA    13.79mA    11.39mA
-709.1mV  5.603mA    4.298mA    7.212mA
-527.3mV  1.593mA    1.002mA    1.9mA
-381.8mV  140.2uA    115.9uA    126.2uA
1.764V    -143.5uA   -80.18uA   -225.9uA
[Pulldown]
-1.8V     -10.48mA   -6.986mA   -6.871mA
-1.145V   -14.76mA   -9.635mA   -12.53mA
-872.7mV  -19.16mA   -11.57mA   -26.86mA
-600mV    -17.63mA   -11.14mA   -24.6mA
1.636V    48.02mA    29.94mA    67.34mA
2.073V    58.18mA    34.17mA    83.16mA
2.291V    61.26mA    32.65mA    90.37mA
2.455V    60.31mA    29.78mA    94.52mA
2.618V    57.35mA    25.94mA    94.79mA
2.782V    51.42mA    22.55mA    92.8mA
3.055V    43.58mA    17.93mA    79.45mA
3.545V    32.44mA    11.99mA    65.6mA
[Pullup]
-1.8V     15.25mA    9.689mA    21.84mA
-818.2mV  16.04mA    10.87mA    21.92mA
-490.9mV  13.71mA    9.212mA    18.64mA
1.036V    -30.4mA    -20.07mA   -41.09mA
2.018V    -57.1mA    -36.81mA   -77.94mA
2.345V    -64.48mA   -38.06mA   -89.56mA
2.618V    -64.84mA   -32.95mA   -96.49mA
2.782V    -59.78mA   -28.7mA    -96.85mA
2.836V    -57.13mA   -27.34mA   -95.03mA
3V        -50.06mA   -23.92mA   -80.64mA
3.218V    -41.82mA   -20.26mA   -57.92mA
3.545V    -34.58mA   -15.09mA   -32.06mA
[GND_clamp]
-1.8V     -697.8mA   -553.3mA   -1.259A
-1.145V   -140.7mA   -131.7mA   -248.4mA
-1.109V   -115.2mA   -111.7mA   -203.4mA
-1.036V   -69.7mA    -74.11mA   -126mA
-1V       -53.27mA   -58.3mA    -96.66mA
-927.3mV  -28.09mA   -31.91mA   -45.55mA
-890.9mV  -20.27mA   -23.4mA    -28.66mA
-854.5mV  -14.02mA   -16.45mA   -16.78mA
-818.2mV  -9.341mA   -11.08mA   -9.899mA
-672.7mV  -3.472mA   -3.23mA    -3.981mA
-18.18mV  0A         0A         0A
3.6V      0A         0A         0A
[Ramp]
dV/dt_f  0.7446489/0.1404022n 0.55123605/0.29352959n 0.90526713/79.983793p
dV/dt_r 0.66748949/0.12390014n  0.5094473/0.24366087n 0.80990532/75.884978p
R_load = 50
[Rising Waveform]
R_fixture = 50
V_fixture = 1.8
V_fixture_min = 1.62
V_fixture_max = 1.98
62.54ps   703.5mV    810.1mV    629.7mV
82.19ps   703.5mV    810.1mV    811.3mV
140.3ps   703.5mV    810.1mV    1.679V
204.3ps   702.7mV    810.1mV    1.884V
375.6ps   761.7mV    810.1mV    1.945V
480.2ps   1.501V     810.1mV    1.956V
565.1ps   1.708V     810.1mV    1.962V
1.018ns   1.78V      821.7mV    1.976V
1.344ns   1.79V      1.51V      1.979V
1.795ns   1.8V       1.62V      1.98V
[Rising Waveform]
R_fixture = 50
V_fixture = 0
V_fixture_min = 0
V_fixture_max = 0
77.11ps   2.803mV    1.768mV    3.968mV
137.4ps   2.844mV    1.77mV     758.1mV
170.2ps   2.832mV    1.77mV     1.027V
288.5ps   -1.939mV   1.771mV    1.246V
407.8ps   -7.203mV   1.758mV    1.283V
540.2ps   778mV      1.758mV    1.3V
663.6ps   973.7mV    1.808mV    1.307V
1.16ns    1.058V     -42.67mV   1.317V
1.491ns   1.065V     636.6mV    1.32V
2.199ns   1.077V     801.8mV    1.323V
[Falling Waveform]
R_fixture = 50
V_fixture = 1.8
V_fixture_min = 1.62
V_fixture_max = 1.98
57.86ps   1.8V       1.62V      1.98V
105.8ps   1.8V       1.62V      1.337V
148.4ps   1.811V     1.62V      931.6mV
235.4ps   1.854V     1.62V      705.9mV
342.1ps   1.902V     1.62V      669.5mV
511ps     1.018V     1.62V      651.4mV
646ps     783.5mV    1.62V      644.7mV
1.069ns   722.8mV    1.714V     637mV
1.515ns   713.4mV    973.1mV    633.9mV
2.128ns   703.5mV    810.1mV    629.7mV
[Falling Waveform]
R_fixture = 50
V_fixture = 0
V_fixture_min = 0
V_fixture_max = 0
0s        1.077V     801.8mV    1.323V
106.6ps   1.078V     801.8mV    250mV
181.8ps   1.092V     801.8mV    76.03mV
260.5ps   1.024V     801.8mV    50.86mV
360.1ps   478.8mV    801.8mV    34.35mV
481.4ps   99.9mV     801.6mV    23.97mV
943.3ps   21.74mV    768.6mV    10.5mV
1.129ns   16.72mV    314.2mV    7.924mV
1.251ns   14.48mV    131.5mV    6.73mV
1.718ns   2.803mV    1.768mV    3.968mV
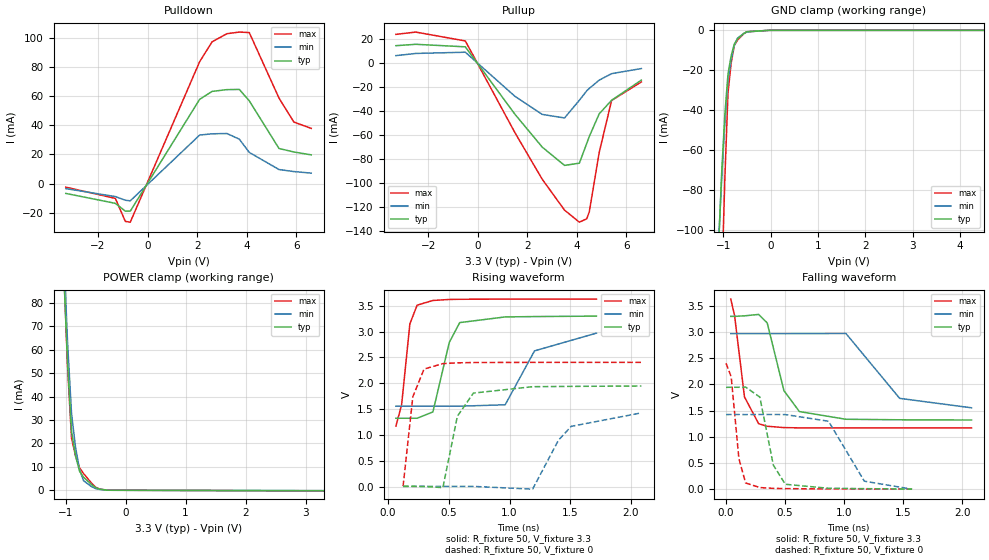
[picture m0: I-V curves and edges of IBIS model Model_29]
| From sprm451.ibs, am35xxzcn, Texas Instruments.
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| Model based on original model for BQ1833DV40DTPBFHP18LL_7LM
|   Sub model HP18LL_7LM_PU_ON_3P3
[model]   Model_29
|[Description]  3.3V-I/O-PU-X
|[Input Load]   PU
|[Output Drive]
|Voltage   3.3V
|Mode   I/O
Model_type   I/O
Polarity   Non-Inverting
Enable   Active-Low
Vinl =  0.8V
Vinh =  2V
Cref =  15pF
Rref =  100.0000M
Vref =  0V
Vmeas =  1.65
C_comp   1.861386p   1.655853p   1.968812p
[Model Spec]
Vinl   0.8V   0.8V   0.8V
Vinh   2V   2V   2V
[Temperature Range]   25   125   -40
[Voltage Range]   3.3   2.97   3.63
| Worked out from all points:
|   slope of the pulldown table from 0 to 0.495 V, typ, clamps not added: 31.5 ohm
|   slope of the pullup table from 0 to 0.495 V, typ, clamps not added: 34.2 ohm
|   GND clamp passes 1 mA (typ) near -0.52 V on its own axis
|   POWER clamp passes 1 mA (typ) near -0.48 V on its own axis
|   rising waveform, R_fixture 50, V_fixture 3.3: 20-80 % time 118ps typ, 207ps min, 63.1ps max; typ from 1.32 V to 3.3 V
|   rising waveform, R_fixture 50, V_fixture 0: 20-80 % time 110ps typ, 205ps min, 71.8ps max; typ from 0.003 V to 1.95 V
|   falling waveform, R_fixture 50, V_fixture 3.3: 20-80 % time 145ps typ, 269ps min, 84.6ps max; typ from 3.3 V to 1.32 V
|   falling waveform, R_fixture 50, V_fixture 0: 20-80 % time 99.2ps typ, 182ps min, 58.2ps max; typ from 1.95 V to 0.003 V
[POWER_clamp]
-3.3V     2.432A     2.868A     2.62A
-1.033V   95.06mA    103.2mA    96.82mA
-966.7mV  54.89mA    63.36mA    52.99mA
-900mV    25.17mA    32.73mA    22.29mA
-833.3mV  14.71mA    18.41mA    14.68mA
-766.7mV  8.177mA    8.865mA    9.637mA
-700mV    5.568mA    4.096mA    7.172mA
-566.7mV  2.478mA    1.576mA    3.075mA
-500mV    1.182mA    756.3uA    1.336mA
-433.3mV  529.8uA    361.2uA    561.7uA
-300mV    28.38uA    26.91uA    30.81uA
3.3V      -177.5uA   -143.5uA   -277.3uA
[Pulldown]
-3.3V     -6.746mA   -3.451mA   -2.449mA
-1.3V     -13.56mA   -8.907mA   -10.16mA
-900mV    -18.87mA   -11.41mA   -25.91mA
-700mV    -18.91mA   -11.83mA   -26.47mA
2.1V      57.81mA    33.29mA    83.64mA
2.6V      63.23mA    34.14mA    97.21mA
3.2V      64.44mA    34.35mA    102.8mA
3.7V      64.57mA    30.45mA    103.9mA
4.1V      56.78mA    21.39mA    103.6mA
5.3V      24.08mA    9.65mA     58.63mA
5.9V      21.68mA    8.241mA    42.2mA
6.6V      19.7mA     7.18mA     37.87mA
[Pullup]
-3.3V     14.58mA    6.278mA    24.04mA
-2.5V     15.74mA    8.096mA    25.94mA
-500mV    13.62mA    9.123mA    18.54mA
1.5V      -42.71mA   -27.72mA   -58.09mA
2.6V      -70.12mA   -42.82mA   -96.97mA
3.5V      -85.45mA   -45.81mA   -122.8mA
4.1V      -83.58mA   -31.01mA   -132.9mA
4.4V      -66.93mA   -23.06mA   -130mA
4.5V      -61.28mA   -21.14mA   -124.2mA
4.9V      -42.38mA   -14.19mA   -74.57mA
5.4V      -31.02mA   -8.795mA   -31.2mA
6.6V      -14.18mA   -4.519mA   -15.68mA
[GND_clamp]
-3.3V     -2.048A    -1.805A    -3.667A
-1.1V     -108.7mA   -106.5mA   -191.5mA
-1.033V   -71.21mA   -74.08mA   -127.8mA
-966.7mV  -42.29mA   -46.88mA   -74.43mA
-900mV    -21.88mA   -24.94mA   -31.36mA
-833.3mV  -12.76mA   -14.54mA   -16.38mA
-766.7mV  -6.884mA   -7.551mA   -7.57mA
-700mV    -4.265mA   -3.97mA    -4.926mA
-566.7mV  -1.605mA   -1.575mA   -1.664mA
-500mV    -702.9uA   -787.9uA   -705.8uA
-33.33mV  0A         0A         0A
6.6V      0A         0A         0A
[Ramp]
dV/dt_f  1.2088099/0.14590382n 0.87076856/0.2713783n   1.494596/85.099489p
dV/dt_r  1.2003306/0.11075094n 0.89198535/0.20709846n  1.4642058/72.131359p
R_load = 50
[Rising Waveform]
R_fixture = 50
V_fixture = 3.3
V_fixture_min = 2.97
V_fixture_max = 3.63
63.87ps   1.322V     1.555V     1.171V
110.7ps   1.322V     1.555V     1.581V
178.9ps   1.322V     1.555V     3.152V
238.9ps   1.322V     1.555V     3.512V
368.7ps   1.445V     1.555V     3.603V
503.1ps   2.788V     1.555V     3.622V
589.4ps   3.174V     1.555V     3.626V
964.1ps   3.284V     1.583V     3.629V
1.206ns   3.291V     2.627V     3.63V
1.716ns   3.3V       2.97V      3.63V
[Rising Waveform]
R_fixture = 50
V_fixture = 0
V_fixture_min = 0
V_fixture_max = 0
122.9ps   3.381mV    2.142mV    4.746mV
203.4ps   3.56mV     2.144mV    1.74V
295.9ps   2.256mV    2.144mV    2.275V
450.9ps   -21.78mV   2.135mV    2.38V
570.1ps   1.361V     2.168mV    2.395V
702ps     1.809V     2.291mV    2.401V
1.19ns    1.933V     -51.43mV   2.404V
1.403ns   1.937V     897.4mV    2.404V
1.508ns   1.939V     1.165V     2.404V
2.086ns   1.946V     1.426V     2.404V
[Falling Waveform]
R_fixture = 50
V_fixture = 3.3
V_fixture_min = 2.97
V_fixture_max = 3.63
39.93ps   3.3V       2.97V      3.63V
72.08ps   3.3V       2.97V      3.316V
156.2ps   3.31V      2.97V      1.761V
275.9ps   3.337V     2.97V      1.251V
348.3ps   3.176V     2.97V      1.203V
490.2ps   1.882V     2.97V      1.177V
620.8ps   1.483V     2.971V     1.172V
1.015ns   1.336V     2.973V     1.172V
1.47ns    1.326V     1.735V     1.171V
2.078ns   1.322V     1.555V     1.171V
[Falling Waveform]
R_fixture = 50
V_fixture = 0
V_fixture_min = 0
V_fixture_max = 0
0s        1.946V     1.426V     2.404V
43.48ps   1.946V     1.427V     2.148V
108.7ps   1.947V     1.427V     587.1mV
165.5ps   1.95V      1.426V     120.4mV
286ps     1.76V      1.427V     32.7mV
399.9ps   464.7mV    1.427V     17.69mV
501.6ps   95.28mV    1.426V     12.69mV
867.7ps   19.39mV    1.298V     6.151mV
1.171ns   12.09mV    154.6mV    5.005mV
1.575ns   3.381mV    2.142mV    4.746mV
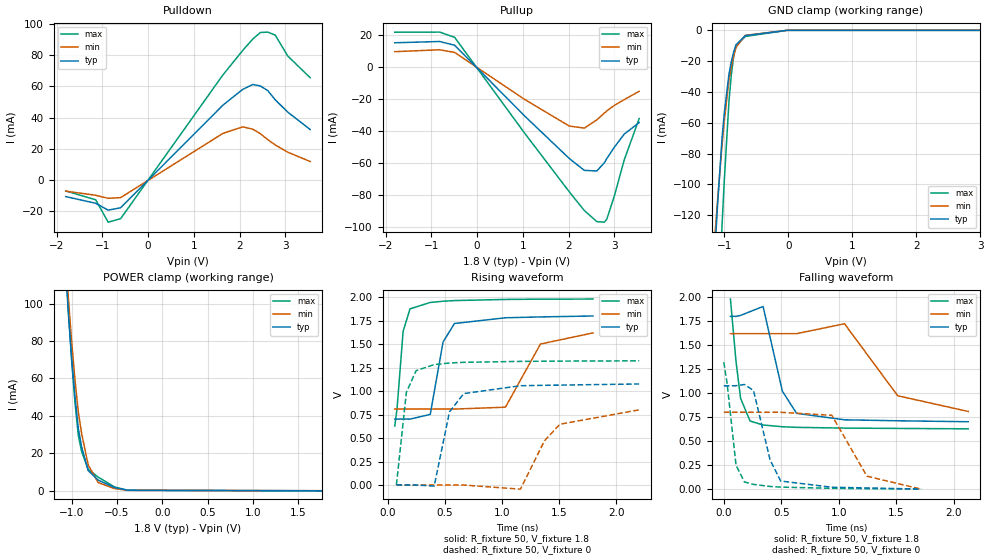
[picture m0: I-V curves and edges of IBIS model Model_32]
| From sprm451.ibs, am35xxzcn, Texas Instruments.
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| Model based on original model for BQ1833DV40DTPBFZP18LL_7LM
|   Sub model ZP18LL_7LM_PU_ON_1P8
[model]   Model_32
|[Description]  1.8V-I/O-PU-X
|[Input Load]   PU
|[Output Drive]
|Voltage   1.8V
|Mode   I/O
Model_type   I/O
Polarity   Non-Inverting
Enable   Active-Low
Vinl =  0.63V
Vinh =  1.17V
Cref =  15pF
Rref =  100.0000M
Vref =  0V
Vmeas =  0.9
C_comp   2.161439p   2.02467p   2.204523p
[Model Spec]
Vinl   0.63V   0.567V   0.693V
Vinh   1.17V   1.053V   1.287V
[Temperature Range]   25   125   -40
[Voltage Range]   1.8   1.62   1.98
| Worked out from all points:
|   slope of the pulldown table from 0 to 0.27 V, typ, clamps not added: 31.5 ohm
|   slope of the pullup table from 0 to 0.27 V, typ, clamps not added: 33.5 ohm
|   GND clamp passes 1 mA (typ) near -0.53 V on its own axis
|   POWER clamp passes 1 mA (typ) near -0.49 V on its own axis
|   rising waveform, R_fixture 50, V_fixture 1.8: 20-80 % time 93.5ps typ, 188ps min, 56.3ps max; typ from 0.703 V to 1.8 V
|   rising waveform, R_fixture 50, V_fixture 0: 20-80 % time 123ps typ, 243ps min, 75.4ps max; typ from 0.003 V to 1.08 V
|   falling waveform, R_fixture 50, V_fixture 1.8: 20-80 % time 132ps typ, 277ps min, 75.6ps max; typ from 1.8 V to 0.703 V
|   falling waveform, R_fixture 50, V_fixture 0: 20-80 % time 135ps typ, 208ps min, 71.2ps max; typ from 1.08 V to 0.003 V
[POWER_clamp]
-1.8V     842.2mA    869.2mA    912.6mA
-1.073V   123.5mA    130.8mA    128.8mA
-1.036V   94.66mA    102.8mA    96.27mA
-1V       70.68mA    79.61mA    69.37mA
-963.6mV  50.27mA    59.42mA    47.18mA
-927.3mV  33.45mA    42.25mA    29.69mA
-890.9mV  23.53mA    30.71mA    20.96mA
-818.2mV  10.69mA    13.79mA    11.39mA
-709.1mV  5.603mA    4.298mA    7.212mA
-527.3mV  1.593mA    1.002mA    1.9mA
-381.8mV  140.2uA    115.9uA    126.2uA
1.764V    -143.5uA   -80.18uA   -225.9uA
[Pulldown]
-1.8V     -10.48mA   -6.986mA   -6.871mA
-1.145V   -14.76mA   -9.635mA   -12.53mA
-872.7mV  -19.16mA   -11.57mA   -26.86mA
-600mV    -17.63mA   -11.14mA   -24.6mA
1.636V    48.02mA    29.94mA    67.34mA
2.073V    58.18mA    34.17mA    83.16mA
2.291V    61.26mA    32.65mA    90.37mA
2.455V    60.31mA    29.78mA    94.52mA
2.618V    57.35mA    25.94mA    94.79mA
2.782V    51.42mA    22.55mA    92.8mA
3.055V    43.58mA    17.93mA    79.45mA
3.545V    32.44mA    11.99mA    65.6mA
[Pullup]
-1.8V     15.25mA    9.689mA    21.84mA
-818.2mV  16.04mA    10.87mA    21.92mA
-490.9mV  13.71mA    9.212mA    18.64mA
1.036V    -30.4mA    -20.07mA   -41.09mA
2.018V    -57.1mA    -36.81mA   -77.94mA
2.345V    -64.48mA   -38.06mA   -89.56mA
2.618V    -64.84mA   -32.95mA   -96.49mA
2.782V    -59.78mA   -28.7mA    -96.85mA
2.836V    -57.13mA   -27.34mA   -95.03mA
3V        -50.06mA   -23.92mA   -80.64mA
3.218V    -41.82mA   -20.26mA   -57.92mA
3.545V    -34.58mA   -15.09mA   -32.06mA
[GND_clamp]
-1.8V     -697.8mA   -553.3mA   -1.259A
-1.145V   -140.7mA   -131.7mA   -248.4mA
-1.109V   -115.2mA   -111.7mA   -203.4mA
-1.036V   -69.7mA    -74.11mA   -126mA
-1V       -53.27mA   -58.3mA    -96.66mA
-927.3mV  -28.09mA   -31.91mA   -45.55mA
-890.9mV  -20.27mA   -23.4mA    -28.66mA
-854.5mV  -14.02mA   -16.45mA   -16.78mA
-818.2mV  -9.341mA   -11.08mA   -9.899mA
-672.7mV  -3.472mA   -3.23mA    -3.981mA
-18.18mV  0A         0A         0A
3.6V      0A         0A         0A
[Ramp]
dV/dt_f 0.74464658/0.1403864n 0.55122545/0.29357659n 0.90535371/80.011761p
dV/dt_r 0.66748863/0.12390518n 0.50933903/0.24381256n 0.80988169/75.876612p
R_load = 50
[Rising Waveform]
R_fixture = 50
V_fixture = 1.8
V_fixture_min = 1.62
V_fixture_max = 1.98
62.55ps   703.5mV    810.1mV    629.7mV
82.1ps    703.5mV    810.1mV    809.9mV
135.6ps   703.5mV    810.1mV    1.637V
196ps     703mV      810.1mV    1.876V
372.7ps   753.6mV    810.1mV    1.944V
484.6ps   1.523V     810.1mV    1.957V
584.3ps   1.72V      810.1mV    1.964V
1.03ns    1.781V     829.9mV    1.976V
1.336ns   1.79V      1.502V     1.979V
1.795ns   1.8V       1.62V      1.98V
[Rising Waveform]
R_fixture = 50
V_fixture = 0
V_fixture_min = 0
V_fixture_max = 0
77.06ps   2.803mV    1.768mV    3.968mV
164ps     2.853mV    1.77mV     988.4mV
249.1ps   2.191mV    1.77mV     1.219V
407.2ps   -8.677mV   1.759mV    1.283V
540.8ps   780.2mV    1.758mV    1.3V
665.4ps   974.8mV    1.808mV    1.307V
1.161ns   1.058V     -41.89mV   1.317V
1.371ns   1.063V     473mV      1.319V
1.506ns   1.065V     648.7mV    1.32V
2.199ns   1.077V     801.8mV    1.323V
[Falling Waveform]
R_fixture = 50
V_fixture = 1.8
V_fixture_min = 1.62
V_fixture_max = 1.98
57.9ps    1.8V       1.62V      1.98V
106.1ps   1.8V       1.62V      1.335V
146.3ps   1.81V      1.62V      947mV
228.3ps   1.849V     1.62V      711.2mV
342ps     1.903V     1.62V      669.5mV
509.9ps   1.022V     1.62V      651.5mV
633.2ps   791.1mV    1.62V      645.1mV
1.051ns   723.5mV    1.723V     637.2mV
1.514ns   713.4mV    973.9mV    633.9mV
2.128ns   703.5mV    810.1mV    629.7mV
[Falling Waveform]
R_fixture = 50
V_fixture = 0
V_fixture_min = 0
V_fixture_max = 0
0s        1.077V     801.8mV    1.323V
29.45ps   1.077V     801.8mV    1.097V
106.6ps   1.078V     801.8mV    250.4mV
179.3ps   1.091V     801.8mV    77.33mV
258.8ps   1.029V     801.8mV    51.24mV
403ps     306mV      801.8mV    29.9mV
495.3ps   86.43mV    801.6mV    23.14mV
940.6ps   21.84mV    770.4mV    10.54mV
1.246ns   14.57mV    137.1mV    6.773mV
1.718ns   2.803mV    1.768mV    3.968mV
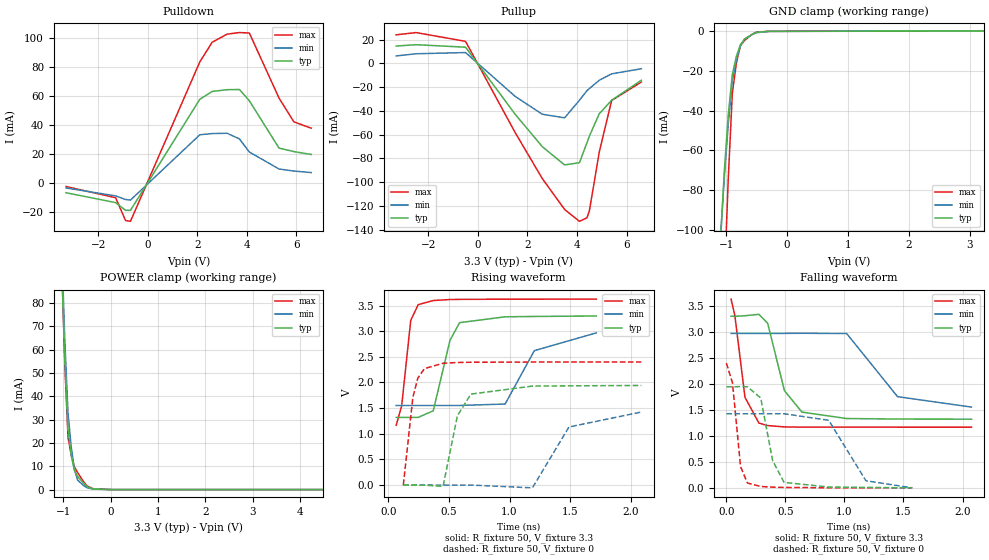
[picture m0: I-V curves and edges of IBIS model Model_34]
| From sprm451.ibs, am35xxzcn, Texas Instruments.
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| Model based on original model for BQ1833DV40DTPBFZP18LL_7LM
|   Sub model ZP18LL_7LM_PD_ON_3P3
[model]   Model_34
|[Description]  3.3V-I/O-PD-X
|[Input Load]   PD
|[Output Drive]
|Voltage   3.3V
|Mode   I/O
Model_type   I/O
Polarity   Non-Inverting
Enable   Active-Low
Vinl =  0.8V
Vinh =  2V
Cref =  15pF
Rref =  100.0000M
Vref =  0V
Vmeas =  1.65
C_comp   1.861386p   1.655853p   1.968812p
[Model Spec]
Vinl   0.8V   0.8V   0.8V
Vinh   2V   2V   2V
[Temperature Range]   25   125   -40
[Voltage Range]   3.3   2.97   3.63
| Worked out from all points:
|   slope of the pulldown table from 0 to 0.495 V, typ, clamps not added: 31.5 ohm
|   slope of the pullup table from 0 to 0.495 V, typ, clamps not added: 34.2 ohm
|   GND clamp passes 1 mA (typ) near -0.54 V on its own axis
|   POWER clamp passes 1 mA (typ) near -0.47 V on its own axis
|   rising waveform, R_fixture 50, V_fixture 3.3: 20-80 % time 118ps typ, 208ps min, 63.1ps max; typ from 1.32 V to 3.3 V
|   rising waveform, R_fixture 50, V_fixture 0: 20-80 % time 110ps typ, 206ps min, 71.9ps max; typ from 0 V to 1.94 V
|   falling waveform, R_fixture 50, V_fixture 3.3: 20-80 % time 146ps typ, 269ps min, 84.6ps max; typ from 3.3 V to 1.32 V
|   falling waveform, R_fixture 50, V_fixture 0: 20-80 % time 99.3ps typ, 181ps min, 58.2ps max; typ from 1.94 V to 0 V
[POWER_clamp]
-3.3V     2.432A     2.868A     2.62A
-1.033V   95.16mA    103.3mA    97mA
-966.7mV  55mA       63.41mA    53.17mA
-900mV    25.28mA    32.79mA    22.49mA
-833.3mV  14.83mA    18.47mA    14.88mA
-766.7mV  8.299mA    8.929mA    9.847mA
-700mV    5.694mA    4.162mA    7.387mA
-566.7mV  2.611mA    1.646mA    3.301mA
-500mV    1.319mA    827.8uA    1.568mA
-366.7mV  287.8uA    192.2uA    368.8uA
33.33mV   0A         0A         0A
6.6V      0A         0A         0A
[Pulldown]
-3.3V     -6.746mA   -3.451mA   -2.449mA
-1.3V     -13.56mA   -8.907mA   -10.16mA
-900mV    -18.87mA   -11.41mA   -25.91mA
-700mV    -18.91mA   -11.83mA   -26.47mA
2.1V      57.81mA    33.29mA    83.64mA
2.6V      63.23mA    34.14mA    97.21mA
3.2V      64.44mA    34.35mA    102.8mA
3.7V      64.57mA    30.45mA    103.9mA
4.1V      56.78mA    21.39mA    103.6mA
5.3V      24.08mA    9.65mA     58.63mA
5.9V      21.68mA    8.241mA    42.2mA
6.6V      19.7mA     7.18mA     37.87mA
[Pullup]
-3.3V     14.58mA    6.278mA    24.04mA
-2.5V     15.74mA    8.096mA    25.94mA
-500mV    13.62mA    9.123mA    18.54mA
1.5V      -42.71mA   -27.72mA   -58.1mA
2.6V      -70.12mA   -42.82mA   -96.98mA
3.5V      -85.45mA   -45.81mA   -122.9mA
4.1V      -83.57mA   -31.01mA   -132.9mA
4.4V      -66.93mA   -23.06mA   -130mA
4.5V      -61.28mA   -21.14mA   -124.2mA
4.9V      -42.37mA   -14.19mA   -74.57mA
5.4V      -31.02mA   -8.795mA   -31.2mA
6.6V      -14.18mA   -4.519mA   -15.68mA
[GND_clamp]
-3.3V     -2.048A    -1.805A    -3.667A
-1.1V     -108.6mA   -106.5mA   -191.4mA
-1.033V   -71.11mA   -74.03mA   -127.7mA
-966.7mV  -42.17mA   -46.82mA   -74.25mA
-900mV    -21.74mA   -24.87mA   -31.11mA
-833.3mV  -12.59mA   -14.47mA   -16.1mA
-766.7mV  -6.71mA    -7.469mA   -7.269mA
-700mV    -4.089mA   -3.883mA   -4.623mA
-566.7mV  -1.428mA   -1.487mA   -1.361mA
-500mV    -525.6uA   -699.5uA   -401.5uA
-300mV    -31.04uA   -34.98uA   -39.83uA
3.233V    152.3uA    97.64uA    242.6uA
[Ramp]
dV/dt_f  1.2089812/0.14578919n 0.87098555/0.27143295n  1.4948726/84.991828p
dV/dt_r  1.2006701/0.11085018n 0.89231794/0.20740933n  1.4643173/72.262276p
R_load = 50
[Rising Waveform]
R_fixture = 50
V_fixture = 3.3
V_fixture_min = 2.97
V_fixture_max = 3.63
64.28ps   1.319V     1.552V     1.166V
109.4ps   1.319V     1.552V     1.545V
184.2ps   1.319V     1.552V     3.211V
245.7ps   1.319V     1.552V     3.518V
370.2ps   1.448V     1.552V     3.599V
508.4ps   2.822V     1.552V     3.618V
587.6ps   3.167V     1.552V     3.621V
963.8ps   3.281V     1.58V      3.625V
1.205ns   3.288V     2.621V     3.625V
1.717ns   3.297V     2.968V     3.626V
[Rising Waveform]
R_fixture = 50
V_fixture = 0
V_fixture_min = 0
V_fixture_max = 0
123.2ps   8.381nV    117.4nV    4.085nV
201.5ps   186.9uV    1.748uV    1.705V
242.5ps   -185.2uV   2.009uV    2.084V
297.3ps   -1.311mV   2.569uV    2.271V
451.2ps   -26.32mV   -6.734uV   2.375V
569.5ps   1.35V      25.73uV    2.39V
680.4ps   1.773V     167.6uV    2.395V
1.189ns   1.93V      -54.91mV   2.399V
1.491ns   1.935V     1.132V     2.399V
2.089ns   1.942V     1.424V     2.399V
[Falling Waveform]
R_fixture = 50
V_fixture = 3.3
V_fixture_min = 2.97
V_fixture_max = 3.63
40.1ps    3.297V     2.968V     3.626V
72.06ps   3.296V     2.968V     3.314V
157.8ps   3.307V     2.968V     1.74V
275.9ps   3.334V     2.968V     1.245V
349.9ps   3.162V     2.968V     1.197V
492.4ps   1.866V     2.968V     1.171V
640.6ps   1.455V     2.97V      1.166V
1.019ns   1.332V     2.965V     1.167V
1.45ns    1.322V     1.752V     1.166V
2.076ns   1.319V     1.552V     1.166V
[Falling Waveform]
R_fixture = 50
V_fixture = 0
V_fixture_min = 0
V_fixture_max = 0
0s        1.942V     1.424V     2.399V
52.05ps   1.942V     1.424V     2.017V
120.4ps   1.945V     1.424V     407.4mV
178.5ps   1.943V     1.424V     93.06mV
291.3ps   1.726V     1.424V     26.42mV
392ps     524.3mV    1.424V     13.35mV
488.8ps   105.5mV    1.424V     8.371mV
866.7ps   16.03mV    1.298V     1.397mV
1.182ns   8.52mV     136.9mV    239.5uV
1.574ns   8.381nV    117.4nV    4.085nV
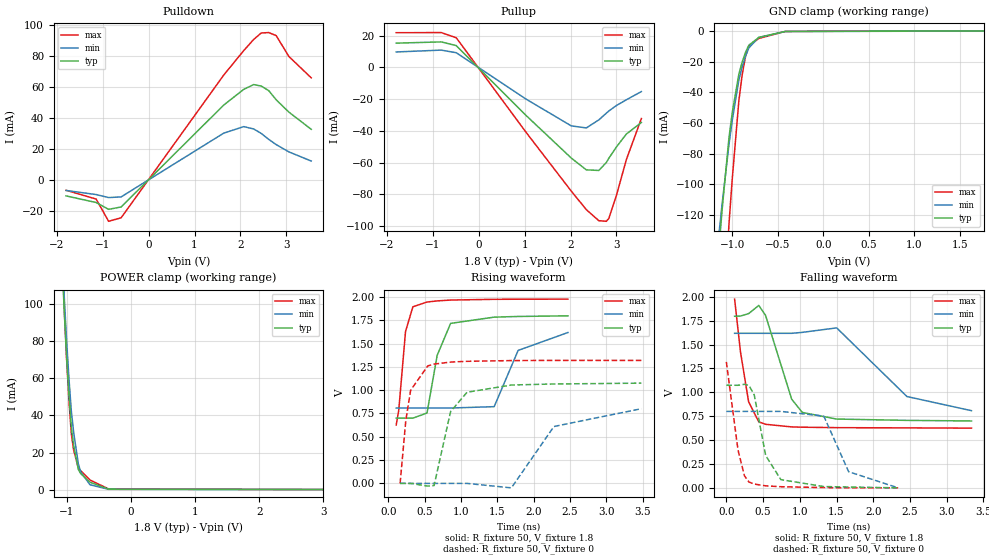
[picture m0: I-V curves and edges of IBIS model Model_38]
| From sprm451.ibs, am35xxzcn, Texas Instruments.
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| Model based on original model for BC1833DV40CTPBFZP18LL_7LM_X50
|   Sub model LL_7LM_X50_PD_ON_1P8
[model]   Model_38
|[Description]  1.8V-I/O-PD-X
|[Input Load]   PD
|[Output Drive]
|Voltage   1.8V
|Mode   I/O
Model_type   I/O
Polarity   Non-Inverting
Enable   Active-Low
Vinl =  0.63V
Vinh =  1.17V
Cref =  15pF
Rref =  100.0000M
Vref =  0V
Vmeas =  0.9
C_comp   2.232809p   2.073051p   2.295852p
[Model Spec]
Vinl   0.63V   0.567V   0.693V
Vinh   1.17V   1.053V   1.287V
[Temperature Range]   25   125   -40
[Voltage Range]   1.8   1.62   1.98
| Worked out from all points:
|   slope of the pulldown table from 0 to 0.27 V, typ, clamps not added: 31.4 ohm
|   slope of the pullup table from 0 to 0.27 V, typ, clamps not added: 33.4 ohm
|   GND clamp passes 1 mA (typ) near -0.54 V on its own axis
|   POWER clamp passes 1 mA (typ) near -0.48 V on its own axis
|   rising waveform, R_fixture 50, V_fixture 1.8: 20-80 % time 174ps typ, 261ps min, 96.7ps max; typ from 0.7 V to 1.8 V
|   rising waveform, R_fixture 50, V_fixture 0: 20-80 % time 226ps typ, 474ps min, 132ps max; typ from 0 V to 1.07 V
|   falling waveform, R_fixture 50, V_fixture 1.8: 20-80 % time 285ps typ, 648ps min, 154ps max; typ from 1.8 V to 0.7 V
|   falling waveform, R_fixture 50, V_fixture 0: 20-80 % time 210ps typ, 258ps min, 143ps max; typ from 1.07 V to 0 V
[POWER_clamp]
-1.8V     842.4mA    869.3mA    912.9mA
-1.073V   123.7mA    130.9mA    129.1mA
-1.036V   94.83mA    102.9mA    96.56mA
-1V       70.85mA    79.7mA     69.66mA
-963.6mV  50.44mA    59.51mA    47.46mA
-927.3mV  33.63mA    42.34mA    29.99mA
-890.9mV  23.71mA    30.8mA     21.26mA
-818.2mV  10.87mA    13.88mA    11.68mA
-781.8mV  8.623mA    9.578mA    10.15mA
-636.4mV  3.988mA    2.612mA    5.172mA
-345.5mV  234.4uA    145uA      345.5uA
3.6V      0A         0A         0A
[Pulldown]
-1.8V     -10.49mA   -6.992mA   -6.878mA
-1.145V   -14.77mA   -9.642mA   -12.54mA
-872.7mV  -19.17mA   -11.58mA   -26.88mA
-600mV    -17.64mA   -11.15mA   -24.61mA
1.636V    48.04mA    29.95mA    67.37mA
2.073V    58.21mA    34.18mA    83.2mA
2.291V    61.28mA    32.65mA    90.41mA
2.455V    60.33mA    29.78mA    94.55mA
2.618V    57.37mA    25.94mA    94.82mA
2.782V    51.43mA    22.55mA    92.84mA
3.055V    43.59mA    17.92mA    79.47mA
3.545V    32.43mA    11.97mA    65.61mA
[Pullup]
-1.8V     15.27mA    9.71mA     21.85mA
-818.2mV  16.05mA    10.88mA    21.94mA
-490.9mV  13.72mA    9.222mA    18.66mA
1.036V    -30.46mA   -20.11mA   -41.15mA
2.018V    -57.22mA   -36.91mA   -78.08mA
2.345V    -64.63mA   -38.19mA   -89.73mA
2.618V    -65.01mA   -33.11mA   -96.69mA
2.782V    -59.96mA   -28.87mA   -97.07mA
2.836V    -57.31mA   -27.51mA   -95.25mA
3V        -50.25mA   -24.09mA   -80.86mA
3.218V    -42.03mA   -20.43mA   -58.16mA
3.545V    -34.78mA   -15.26mA   -32.29mA
[GND_clamp]
-1.8V     -697.8mA   -553.2mA   -1.259A
-1.145V   -140.7mA   -131.7mA   -248.3mA
-1.109V   -115.1mA   -111.6mA   -203.3mA
-1.036V   -69.61mA   -74.07mA   -125.9mA
-1V       -53.17mA   -58.25mA   -96.53mA
-927.3mV  -27.97mA   -31.86mA   -45.36mA
-890.9mV  -20.15mA   -23.34mA   -28.44mA
-854.5mV  -13.89mA   -16.39mA   -16.54mA
-818.2mV  -9.198mA   -11.01mA   -9.648mA
-709.1mV  -4.172mA   -4.037mA   -4.792mA
-418.2mV  -167.1uA   -231.6uA   -161.9uA
1.764V    148.6uA    81.79uA    236.4uA
[Ramp]
dV/dt_f 0.72468238/0.29692966n 0.53520674/0.67524213n 0.88626571/0.1616922n
dV/dt_r 0.68108193/0.22655821n 0.51281713/0.47420792n   0.811647/0.13205393n
R_load = 50
[Rising Waveform]
R_fixture = 50
V_fixture = 1.8
V_fixture_min = 1.62
V_fixture_max = 1.98
106.9ps   700.4mV    808.1mV    625.4mV
141.9ps   700.4mV    808.1mV    785.2mV
235.1ps   700.4mV    808.1mV    1.628V
336.6ps   699.8mV    808.1mV    1.894V
531.1ps   754.7mV    808.1mV    1.945V
670.9ps   1.373V     808.1mV    1.957V
856.2ps   1.716V     808.1mV    1.966V
1.456ns   1.783V     822.9mV    1.974V
1.786ns   1.79V      1.426V     1.975V
2.472ns   1.797V     1.618V     1.976V
[Rising Waveform]
R_fixture = 50
V_fixture = 0
V_fixture_min = 0
V_fixture_max = 0
160.7ps   9.392nV    101.9nV    8.897nV
239.1ps   17.36uV    2.937uV    675.7mV
305.8ps   -452.6uV   1.763uV    999.1mV
541.5ps   -28.81mV   -567.7nV   1.26V
628.4ps   -23.01mV   73.3nV     1.279V
856ps     770.1mV    -2.024uV   1.301V
1.082ns   977.1mV    -290.6uV   1.309V
1.693ns   1.055V     -48.04mV   1.317V
2.279ns   1.066V     610.1mV    1.319V
3.483ns   1.075V     800.7mV    1.319V
[Falling Waveform]
R_fixture = 50
V_fixture = 1.8
V_fixture_min = 1.62
V_fixture_max = 1.98
112.7ps   1.797V     1.618V     1.976V
192.7ps   1.799V     1.618V     1.422V
303ps     1.824V     1.618V     902.2mV
441.6ps   1.91V      1.618V     690.9mV
533.4ps   1.807V     1.618V     665.6mV
889.6ps   928.1mV    1.618V     638.2mV
1.034ns   789.6mV    1.628V     635.1mV
1.502ns   720.4mV    1.675V     630.3mV
2.458ns   706.5mV    956.3mV    627.9mV
3.337ns   700.4mV    808.1mV    625.4mV
[Falling Waveform]
R_fixture = 50
V_fixture = 0
V_fixture_min = 0
V_fixture_max = 0
0s        1.075V     800.7mV    1.319V
158.7ps   1.074V     800.7mV    396.8mV
246.5ps   1.084V     800.7mV    126.6mV
308ps     1.072V     800.7mV    60.84mV
379.6ps   973.7mV    800.7mV    39.83mV
535.9ps   337.7mV    800.7mV    21.17mV
742.7ps   85.77mV    800.7mV    11.88mV
1.327ns   13.68mV    751.2mV    2.649mV
1.665ns   8.959mV    169mV      994.9uV
2.338ns   9.392nV    101.9nV    8.897nV
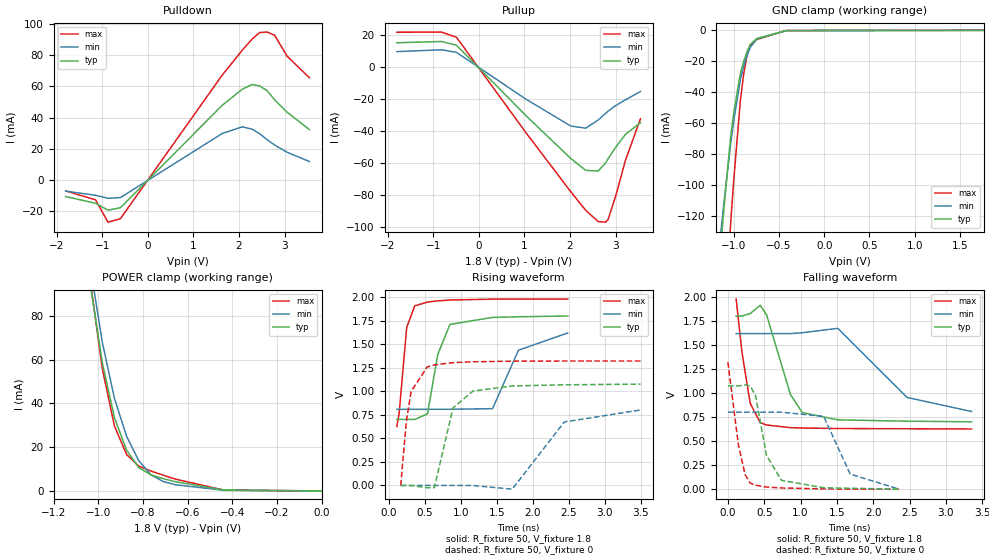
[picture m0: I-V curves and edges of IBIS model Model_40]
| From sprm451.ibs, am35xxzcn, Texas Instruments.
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| Model based on original model for BC1833DV40CTPBFZP18LL_7LM_X50
|   Sub model LM_X50_PD_PU_OFF_1P8
[model]   Model_40
|[Description]  1.8V-I/O-PI-X
|[Input Load]   PI
|[Output Drive]
|Voltage   1.8V
|Mode   I/O
Model_type   I/O
Polarity   Non-Inverting
Enable   Active-Low
Vinl =  0.63V
Vinh =  1.17V
Cref =  15pF
Rref =  100.0000M
Vref =  0V
Vmeas =  0.9
C_comp   2.232809p   2.073051p   2.295852p
[Model Spec]
Vinl   0.63V   0.567V   0.693V
Vinh   1.17V   1.053V   1.287V
[Temperature Range]   25   125   -40
[Voltage Range]   1.8   1.62   1.98
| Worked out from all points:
|   slope of the pulldown table from 0 to 0.27 V, typ, clamps not added: 31.4 ohm
|   slope of the pullup table from 0 to 0.27 V, typ, clamps not added: 33.4 ohm
|   GND clamp passes 1 mA (typ) near -0.54 V on its own axis
|   POWER clamp passes 1 mA (typ) near -0.49 V on its own axis
|   rising waveform, R_fixture 50, V_fixture 1.8: 20-80 % time 175ps typ, 260ps min, 97.3ps max; typ from 0.702 V to 1.8 V
|   rising waveform, R_fixture 50, V_fixture 0: 20-80 % time 229ps typ, 477ps min, 132ps max; typ from 0 V to 1.08 V
|   falling waveform, R_fixture 50, V_fixture 1.8: 20-80 % time 285ps typ, 649ps min, 155ps max; typ from 1.8 V to 0.702 V
|   falling waveform, R_fixture 50, V_fixture 0: 20-80 % time 212ps typ, 259ps min, 144ps max; typ from 1.08 V to 0 V
[POWER_clamp]
-1.8V     842.2mA    869.2mA    912.6mA
-1.055V   109.1mA    116.8mA    112.5mA
-1.036V   94.66mA    102.8mA    96.26mA
-981.8mV  58.67mA    68.01mA    55.9mA
-927.3mV  33.44mA    42.25mA    29.67mA
-872.7mV  18.56mA    24.94mA    16.57mA
-818.2mV  10.68mA    13.78mA    11.36mA
-763.6mV  7.313mA    7.334mA    9.056mA
-709.1mV  5.588mA    4.293mA    7.178mA
-654.5mV  4.216mA    2.83mA     5.403mA
-436.4mV  387.4uA    279.4uA    353.6uA
0V        17.81nA    62.47nA    29.22nA
[Pulldown]
-1.8V     -10.49mA   -6.992mA   -6.878mA
-1.145V   -14.77mA   -9.642mA   -12.54mA
-872.7mV  -19.17mA   -11.58mA   -26.88mA
-600mV    -17.64mA   -11.15mA   -24.61mA
1.636V    48.04mA    29.95mA    67.37mA
2.073V    58.21mA    34.18mA    83.2mA
2.291V    61.28mA    32.65mA    90.41mA
2.455V    60.33mA    29.78mA    94.55mA
2.618V    57.37mA    25.94mA    94.82mA
2.782V    51.43mA    22.55mA    92.84mA
3.055V    43.59mA    17.92mA    79.47mA
3.545V    32.43mA    11.97mA    65.61mA
[Pullup]
-1.8V     15.27mA    9.71mA     21.85mA
-818.2mV  16.05mA    10.88mA    21.94mA
-490.9mV  13.72mA    9.223mA    18.66mA
1.036V    -30.46mA   -20.11mA   -41.15mA
2.018V    -57.22mA   -36.91mA   -78.08mA
2.345V    -64.63mA   -38.19mA   -89.73mA
2.618V    -65.01mA   -33.11mA   -96.69mA
2.782V    -59.96mA   -28.87mA   -97.07mA
2.836V    -57.31mA   -27.51mA   -95.24mA
3V        -50.25mA   -24.09mA   -80.86mA
3.218V    -42.03mA   -20.43mA   -58.16mA
3.545V    -34.78mA   -15.26mA   -32.29mA
[GND_clamp]
-1.8V     -697.8mA   -553.2mA   -1.259A
-1.145V   -140.6mA   -131.7mA   -248.3mA
-1.109V   -115.1mA   -111.6mA   -203.3mA
-1.036V   -69.6mA    -74.06mA   -125.9mA
-1V       -53.16mA   -58.25mA   -96.51mA
-927.3mV  -27.95mA   -31.85mA   -45.33mA
-890.9mV  -20.12mA   -23.33mA   -28.4mA
-854.5mV  -13.86mA   -16.38mA   -16.48mA
-818.2mV  -9.16mA    -11mA      -9.576mA
-745.5mV  -5.269mA   -5.602mA   -5.948mA
-418.2mV  -131.7uA   -213.2uA   -104.8uA
1.764V    17.26nA    527.4nA    24.83nA
[Ramp]
dV/dt_f 0.72681807/0.29763727n 0.53631476/0.6762556n 0.88960757/0.16221696n
dV/dt_r 0.68217647/0.22740411n 0.51339262/0.47549139n 0.81343334/0.13267282n
R_load = 50
[Rising Waveform]
R_fixture = 50
V_fixture = 1.8
V_fixture_min = 1.62
V_fixture_max = 1.98
106.6ps   701.5mV    809.1mV    626.7mV
138.7ps   701.5mV    809.1mV    764.2mV
243.9ps   701.6mV    809.1mV    1.678V
355.7ps   701mV      809.1mV    1.908V
533ps     760.2mV    809.1mV    1.948V
676ps     1.391V     809.1mV    1.961V
844.9ps   1.711V     809.1mV    1.97V
1.437ns   1.785V     815.5mV    1.979V
1.798ns   1.792V     1.437V     1.979V
2.483ns   1.8V       1.62V      1.98V
[Rising Waveform]
R_fixture = 50
V_fixture = 0
V_fixture_min = 0
V_fixture_max = 0
160.4ps   9.859nV    108.8nV    8.928nV
240.1ps   15.15uV    2.926uV    684.3mV
305.2ps   -452.3uV   1.779uV    998mV
529ps     -24.27mV   -578.4nV   1.259V
628.1ps   -23.01mV   80.64nV    1.281V
888.5ps   824.4mV    2.149uV    1.305V
1.166ns   1.003V     -334uV     1.314V
1.711ns   1.057V     -39.54mV   1.32V
2.435ns   1.069V     674.2mV    1.322V
3.494ns   1.076V     801.7mV    1.322V
[Falling Waveform]
R_fixture = 50
V_fixture = 1.8
V_fixture_min = 1.62
V_fixture_max = 1.98
113.2ps   1.8V       1.62V      1.98V
194.3ps   1.803V     1.62V      1.419V
306.7ps   1.829V     1.62V      893.5mV
444.6ps   1.915V     1.62V      692.8mV
532.3ps   1.815V     1.62V      668.4mV
859.3ps   986.6mV    1.62V      640.7mV
1.023ns   797.9mV    1.629V     636.9mV
1.512ns   721.9mV    1.675V     631.7mV
2.465ns   708mV      955.2mV    629.3mV
3.352ns   701.5mV    809.1mV    626.7mV
[Falling Waveform]
R_fixture = 50
V_fixture = 0
V_fixture_min = 0
V_fixture_max = 0
0s        1.076V     801.7mV    1.322V
143.7ps   1.076V     801.7mV    463.3mV
237.5ps   1.086V     801.7mV    149.5mV
305.7ps   1.075V     801.7mV    63.92mV
379.3ps   976mV      801.7mV    41.27mV
530.9ps   351.6mV    801.7mV    22.29mV
736.4ps   91.93mV    801.7mV    12.43mV
1.318ns   14.55mV    757.7mV    2.784mV
1.682ns   9.291mV    157.2mV    967.3uV
2.356ns   9.859nV    108.8nV    8.928nV
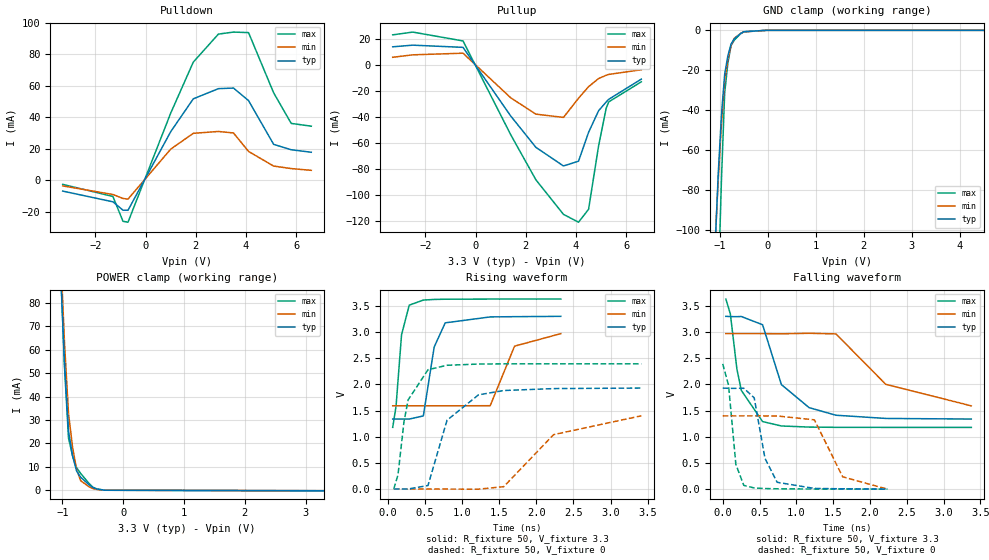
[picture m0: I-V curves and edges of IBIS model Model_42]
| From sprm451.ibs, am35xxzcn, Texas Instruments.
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| Model based on original model for BC1833DV40CTPBFZP18LL_7LM_X50
|   Sub model LL_7LM_X50_PU_ON_3P3
[model]   Model_42
|[Description]  3.3V-I/O-PU-X
|[Input Load]   PU
|[Output Drive]
|Voltage   3.3V
|Mode   I/O
Model_type   I/O
Polarity   Non-Inverting
Enable   Active-Low
Vinl =  0.8V
Vinh =  2V
Cref =  15pF
Rref =  100.0000M
Vref =  0V
Vmeas =  1.65
C_comp   1.943144p   1.721292p   2.064363p
[Model Spec]
Vinl   0.8V   0.8V   0.8V
Vinh   2V   2V   2V
[Temperature Range]   25   125   -40
[Voltage Range]   3.3   2.97   3.63
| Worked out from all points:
|   slope of the pulldown table from 0 to 0.495 V, typ, clamps not added: 31.5 ohm
|   slope of the pullup table from 0 to 0.495 V, typ, clamps not added: 34.6 ohm
|   GND clamp passes 1 mA (typ) near -0.52 V on its own axis
|   POWER clamp passes 1 mA (typ) near -0.48 V on its own axis
|   rising waveform, R_fixture 50, V_fixture 3.3: 20-80 % time 136ps typ, 201ps min, 88.9ps max; typ from 1.34 V to 3.3 V
|   rising waveform, R_fixture 50, V_fixture 0: 20-80 % time 309ps typ, 703ps min, 174ps max; typ from 0.003 V to 1.93 V
|   falling waveform, R_fixture 50, V_fixture 3.3: 20-80 % time 383ps typ, 815ps min, 190ps max; typ from 3.3 V to 1.34 V
|   falling waveform, R_fixture 50, V_fixture 0: 20-80 % time 158ps typ, 244ps min, 92.5ps max; typ from 1.93 V to 0.003 V
[POWER_clamp]
-3.3V     2.432A     2.868A     2.62A
-1.033V   95.08mA    103.2mA    96.86mA
-966.7mV  54.92mA    63.38mA    53.02mA
-900mV    25.2mA     32.75mA    22.32mA
-833.3mV  14.73mA    18.43mA    14.71mA
-766.7mV  8.199mA    8.88mA     9.664mA
-700mV    5.588mA    4.11mA     7.196mA
-566.7mV  2.492mA    1.585mA    3.092mA
-500mV    1.193mA    763uA      1.348mA
-433.3mV  535.3uA    364.9uA    567.5uA
-300mV    28.66uA    27.24uA    30.96uA
3.3V      -177.5uA   -143.2uA   -277.3uA
[Pulldown]
-3.3V     -6.73mA    -3.436mA   -2.446mA
-1.3V     -13.54mA   -8.893mA   -10.15mA
-900mV    -18.86mA   -11.4mA    -25.9mA
-700mV    -18.9mA    -11.82mA   -26.47mA
1V        30.96mA    19.89mA    42.74mA
1.9V      51.83mA    29.94mA    75.14mA
2.9V      58.3mA     31.12mA    92.92mA
3.5V      58.67mA    30.17mA    94.2mA
4.1V      50.73mA    18.46mA    93.88mA
5.1V      22.94mA    9.149mA    55.64mA
5.8V      19.5mA     7.56mA     36.23mA
6.6V      17.91mA    6.449mA    34.47mA
[Pullup]
-3.3V     13.88mA    5.843mA    23.08mA
-2.5V     15.16mA    7.729mA    25.2mA
-500mV    13.47mA    8.99mA     18.39mA
1.4V      -39.27mA   -25.27mA   -53.66mA
2.4V      -63.29mA   -37.81mA   -88.19mA
3.5V      -77.61mA   -40.33mA   -114.8mA
4.1V      -73.95mA   -25.59mA   -120.8mA
4.5V      -51.77mA   -16.71mA   -110.9mA
4.9V      -35.15mA   -10.47mA   -62.03mA
5.2V      -28.48mA   -7.948mA   -33.38mA
5.3V      -26.46mA   -7.311mA   -28.43mA
6.6V      -10.91mA   -3.736mA   -12.96mA
[GND_clamp]
-3.3V     -2.048A    -1.805A    -3.667A
-1.1V     -108.7mA   -106.5mA   -191.5mA
-1.033V   -71.21mA   -74.08mA   -127.8mA
-966.7mV  -42.28mA   -46.87mA   -74.43mA
-900mV    -21.88mA   -24.94mA   -31.36mA
-833.3mV  -12.75mA   -14.54mA   -16.38mA
-766.7mV  -6.878mA   -7.548mA   -7.563mA
-700mV    -4.259mA   -3.966mA   -4.917mA
-566.7mV  -1.601mA   -1.571mA   -1.659mA
-500mV    -700.3uA   -785.2uA   -703.8uA
-33.33mV  0A         0A         0A
6.6V      0A         0A         0A
[Ramp]
dV/dt_f  1.1889844/0.37568541n 0.84311969/0.79998787n  1.4742218/0.18981294n
dV/dt_r  1.1650184/0.30789833n  0.8454593/0.7011035n  1.4416199/0.17225835n
R_load = 50
[Rising Waveform]
R_fixture = 50
V_fixture = 3.3
V_fixture_min = 2.97
V_fixture_max = 3.63
67.21ps   1.34V      1.592V     1.181V
111.5ps   1.34V      1.592V     1.576V
186ps     1.34V      1.592V     2.948V
290ps     1.339V     1.592V     3.514V
479.6ps   1.399V     1.592V     3.611V
625.7ps   2.715V     1.592V     3.623V
774.3ps   3.176V     1.592V     3.627V
1.38ns    3.289V     1.594V     3.63V
1.708ns   3.294V     2.731V     3.63V
2.331ns   3.3V       2.97V      3.63V
[Rising Waveform]
R_fixture = 50
V_fixture = 0
V_fixture_min = 0
V_fixture_max = 0
81.57ps   3.383mV    2.143mV    4.747mV
138.4ps   3.383mV    2.144mV    274.8mV
219.1ps   3.398mV    2.143mV    1.288V
274.6ps   3.147mV    2.143mV    1.704V
542.5ps   70.65mV    2.143mV    2.281V
798.8ps   1.317V     2.143mV    2.366V
1.222ns   1.801V     603.4uV    2.389V
1.562ns   1.884V     48.27mV    2.393V
2.234ns   1.921V     1.042V     2.394V
3.415ns   1.931V     1.401V     2.394V
[Falling Waveform]
R_fixture = 50
V_fixture = 3.3
V_fixture_min = 2.97
V_fixture_max = 3.63
42.67ps   3.3V       2.97V      3.63V
103.2ps   3.296V     2.97V      3.351V
192.7ps   3.294V     2.97V      2.295V
252.6ps   3.297V     2.97V      1.887V
541.5ps   3.14V      2.97V      1.292V
796.8ps   1.998V     2.967V     1.208V
1.173ns   1.558V     2.977V     1.187V
1.538ns   1.413V     2.965V     1.182V
2.214ns   1.352V     2.003V     1.181V
3.376ns   1.34V      1.592V     1.181V
[Falling Waveform]
R_fixture = 50
V_fixture = 0
V_fixture_min = 0
V_fixture_max = 0
0s        1.931V     1.401V     2.394V
79.22ps   1.927V     1.401V     1.986V
178.8ps   1.926V     1.401V     473mV
286.6ps   1.928V     1.401V     74.46mV
427.7ps   1.745V     1.401V     24.87mV
573.8ps   591.4mV    1.4V       14.2mV
739.3ps   132.8mV    1.399V     9.301mV
1.245ns   16.48mV    1.325V     5.022mV
1.629ns   8.632mV    237.6mV    4.781mV
2.238ns   3.383mV    2.143mV    4.747mV
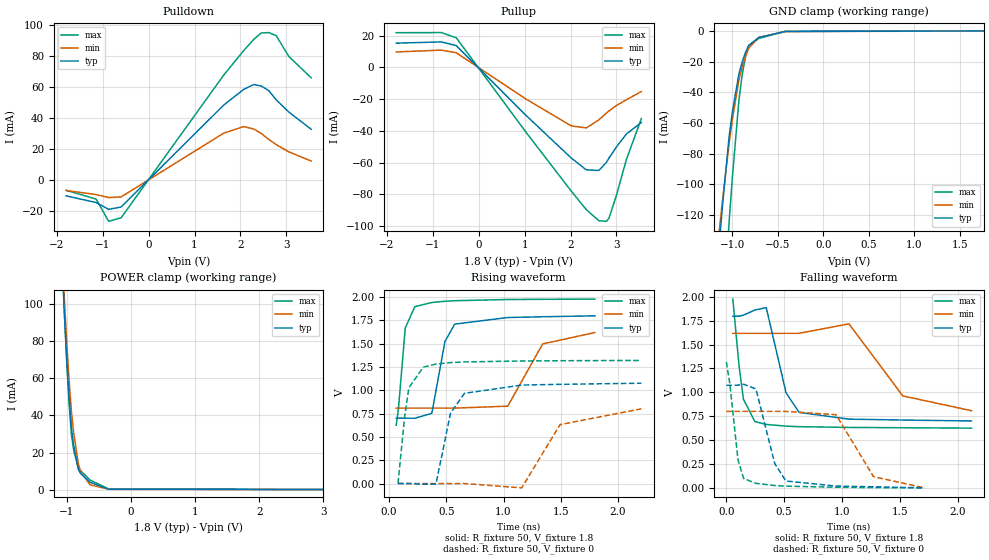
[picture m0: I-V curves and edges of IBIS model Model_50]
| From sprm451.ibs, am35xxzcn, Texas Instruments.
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| Model based on original model for BQ1833DV40DTPBFHP18LL_7LM_X50
|   Sub model LL_7LM_X50_PD_ON_1P8
[model]   Model_50
|[Description]  1.8V-I/O-PD-X
|[Input Load]   PD
|[Output Drive]
|Voltage   1.8V
|Mode   I/O
Model_type   I/O
Polarity   Non-Inverting
Enable   Active-Low
Vinl =  0.63V
Vinh =  1.17V
Cref =  15pF
Rref =  100.0000M
Vref =  0V
Vmeas =  0.9
C_comp   2.258279p   2.108893p   2.320297p
[Model Spec]
Vinl   0.63V   0.567V   0.693V
Vinh   1.17V   1.053V   1.287V
[Temperature Range]   25   125   -40
[Voltage Range]   1.8   1.62   1.98
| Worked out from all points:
|   slope of the pulldown table from 0 to 0.27 V, typ, clamps not added: 31.4 ohm
|   slope of the pullup table from 0 to 0.27 V, typ, clamps not added: 33.4 ohm
|   GND clamp passes 1 mA (typ) near -0.54 V on its own axis
|   POWER clamp passes 1 mA (typ) near -0.48 V on its own axis
|   rising waveform, R_fixture 50, V_fixture 1.8: 20-80 % time 96.2ps typ, 193ps min, 58.4ps max; typ from 0.7 V to 1.8 V
|   rising waveform, R_fixture 50, V_fixture 0: 20-80 % time 125ps typ, 246ps min, 77.1ps max; typ from 0 V to 1.07 V
|   falling waveform, R_fixture 50, V_fixture 1.8: 20-80 % time 134ps typ, 277ps min, 76.4ps max; typ from 1.8 V to 0.7 V
|   falling waveform, R_fixture 50, V_fixture 0: 20-80 % time 136ps typ, 213ps min, 71.1ps max; typ from 1.07 V to 0 V
[POWER_clamp]
-1.8V     842.4mA    869.3mA    912.9mA
-1.073V   123.7mA    130.9mA    129.1mA
-1.036V   94.83mA    102.9mA    96.56mA
-1V       70.85mA    79.7mA     69.66mA
-963.6mV  50.44mA    59.51mA    47.46mA
-927.3mV  33.63mA    42.34mA    29.99mA
-890.9mV  23.71mA    30.8mA     21.26mA
-818.2mV  10.87mA    13.88mA    11.68mA
-781.8mV  8.623mA    9.578mA    10.15mA
-636.4mV  3.988mA    2.612mA    5.172mA
-345.5mV  234.4uA    145uA      345.5uA
3.6V      0A         0A         0A
[Pulldown]
-1.8V     -10.49mA   -6.992mA   -6.878mA
-1.145V   -14.77mA   -9.642mA   -12.54mA
-872.7mV  -19.17mA   -11.58mA   -26.88mA
-600mV    -17.64mA   -11.15mA   -24.61mA
1.636V    48.04mA    29.95mA    67.37mA
2.073V    58.21mA    34.18mA    83.2mA
2.291V    61.28mA    32.65mA    90.41mA
2.455V    60.33mA    29.78mA    94.55mA
2.618V    57.37mA    25.94mA    94.82mA
2.782V    51.43mA    22.55mA    92.84mA
3.055V    43.59mA    17.92mA    79.47mA
3.545V    32.43mA    11.97mA    65.61mA
[Pullup]
-1.8V     15.27mA    9.71mA     21.85mA
-818.2mV  16.05mA    10.88mA    21.94mA
-490.9mV  13.72mA    9.222mA    18.66mA
1.036V    -30.46mA   -20.11mA   -41.15mA
2.018V    -57.22mA   -36.91mA   -78.08mA
2.345V    -64.63mA   -38.19mA   -89.73mA
2.618V    -65.01mA   -33.11mA   -96.69mA
2.782V    -59.96mA   -28.87mA   -97.07mA
2.836V    -57.31mA   -27.51mA   -95.25mA
3V        -50.25mA   -24.09mA   -80.86mA
3.218V    -42.03mA   -20.43mA   -58.16mA
3.545V    -34.78mA   -15.26mA   -32.29mA
[GND_clamp]
-1.8V     -697.8mA   -553.2mA   -1.259A
-1.145V   -140.7mA   -131.7mA   -248.3mA
-1.109V   -115.1mA   -111.6mA   -203.3mA
-1.036V   -69.61mA   -74.07mA   -125.9mA
-1V       -53.17mA   -58.25mA   -96.53mA
-927.3mV  -27.97mA   -31.86mA   -45.36mA
-890.9mV  -20.15mA   -23.34mA   -28.44mA
-854.5mV  -13.89mA   -16.39mA   -16.54mA
-818.2mV  -9.198mA   -11.01mA   -9.648mA
-709.1mV  -4.172mA   -4.037mA   -4.792mA
-418.2mV  -167.1uA   -231.6uA   -161.9uA
1.764V    148.6uA    81.79uA    236.4uA
[Ramp]
dV/dt_f 0.74239028/0.1411492n 0.54981991/0.29321666n 0.90102458/80.752878p
dV/dt_r  0.6681479/0.12567307n 0.50990338/0.2464713n 0.81073912/77.530571p
R_load = 50
[Rising Waveform]
R_fixture = 50
V_fixture = 1.8
V_fixture_min = 1.62
V_fixture_max = 1.98
62.83ps   700.4mV    808.1mV    625.4mV
82.4ps    700.4mV    808.1mV    802.9mV
141.9ps   700.4mV    808.1mV    1.667V
225.6ps   699.1mV    808.1mV    1.895V
374.1ps   752.5mV    808.1mV    1.94V
488.1ps   1.521V     808.1mV    1.953V
573.7ps   1.708V     808.1mV    1.959V
1.037ns   1.779V     829.2mV    1.972V
1.342ns   1.787V     1.496V     1.974V
1.798ns   1.797V     1.618V     1.976V
[Rising Waveform]
R_fixture = 50
V_fixture = 0
V_fixture_min = 0
V_fixture_max = 0
78.53ps   9.392nV    101.9nV    8.897nV
137.4ps   37.56uV    -156.4nV   728.6mV
173.8ps   1.384uV    229.1nV    1.027V
299.4ps   -7.497mV   1.275uV    1.247V
410ps     -5.839mV   -7.734uV   1.28V
537ps     753.4mV    -2.459uV   1.296V
659.2ps   966.7mV    31.8uV     1.303V
1.159ns   1.055V     -46.28mV   1.313V
1.494ns   1.063V     631.4mV    1.316V
2.204ns   1.075V     800.7mV    1.319V
[Falling Waveform]
R_fixture = 50
V_fixture = 1.8
V_fixture_min = 1.62
V_fixture_max = 1.98
56.18ps   1.797V     1.618V     1.976V
110.1ps   1.798V     1.618V     1.276V
147.9ps   1.808V     1.618V     928.2mV
247.2ps   1.862V     1.618V     693.5mV
345.2ps   1.887V     1.618V     664mV
516.5ps   995.9mV    1.618V     646.1mV
629ps     790.2mV    1.618V     640.6mV
1.06ns    719.6mV    1.717V     632.7mV
1.526ns   710mV      962.6mV    629.5mV
2.12ns    700.4mV    808.1mV    625.4mV
[Falling Waveform]
R_fixture = 50
V_fixture = 0
V_fixture_min = 0
V_fixture_max = 0
0s        1.075V     800.7mV    1.319V
29.24ps   1.074V     800.7mV    1.101V
100.9ps   1.075V     800.7mV    293.3mV
149.6ps   1.085V     800.7mV    97.42mV
255.8ps   1.036V     800.7mV    47.37mV
419ps     253.1mV    800.7mV    24.09mV
515.1ps   71.79mV    800.5mV    17.84mV
948.3ps   18.56mV    766mV      6.47mV
1.273ns   11.32mV    117mV      2.617mV
1.711ns   9.392nV    101.9nV    8.897nV
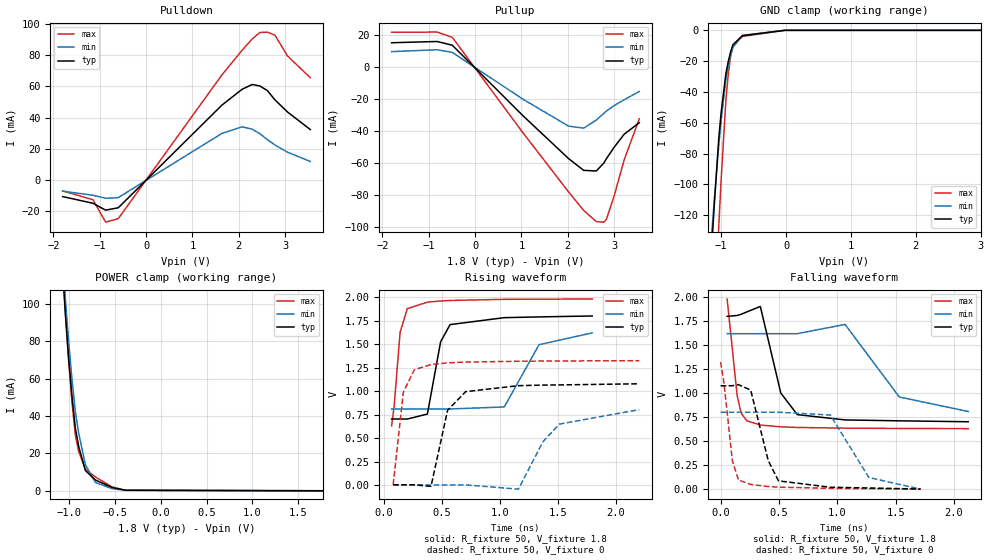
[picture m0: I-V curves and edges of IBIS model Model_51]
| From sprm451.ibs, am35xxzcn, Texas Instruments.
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| Model based on original model for BQ1833DV40DTPBFHP18LL_7LM_X50
|   Sub model LL_7LM_X50_PU_ON_1P8
[model]   Model_51
|[Description]  1.8V-I/O-PU-X
|[Input Load]   PU
|[Output Drive]
|Voltage   1.8V
|Mode   I/O
Model_type   I/O
Polarity   Non-Inverting
Enable   Active-Low
Vinl =  0.63V
Vinh =  1.17V
Cref =  15pF
Rref =  100.0000M
Vref =  0V
Vmeas =  0.9
C_comp   2.258279p   2.108893p   2.320297p
[Model Spec]
Vinl   0.63V   0.567V   0.693V
Vinh   1.17V   1.053V   1.287V
[Temperature Range]   25   125   -40
[Voltage Range]   1.8   1.62   1.98
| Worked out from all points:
|   slope of the pulldown table from 0 to 0.27 V, typ, clamps not added: 31.4 ohm
|   slope of the pullup table from 0 to 0.27 V, typ, clamps not added: 33.4 ohm
|   GND clamp passes 1 mA (typ) near -0.53 V on its own axis
|   POWER clamp passes 1 mA (typ) near -0.49 V on its own axis
|   rising waveform, R_fixture 50, V_fixture 1.8: 20-80 % time 96ps typ, 192ps min, 56.9ps max; typ from 0.703 V to 1.8 V
|   rising waveform, R_fixture 50, V_fixture 0: 20-80 % time 125ps typ, 246ps min, 77ps max; typ from 0.003 V to 1.08 V
|   falling waveform, R_fixture 50, V_fixture 1.8: 20-80 % time 134ps typ, 278ps min, 76.2ps max; typ from 1.8 V to 0.703 V
|   falling waveform, R_fixture 50, V_fixture 0: 20-80 % time 137ps typ, 213ps min, 71.1ps max; typ from 1.08 V to 0.003 V
[POWER_clamp]
-1.8V     842.3mA    869.2mA    912.6mA
-1.073V   123.5mA    130.8mA    128.8mA
-1.036V   94.69mA    102.8mA    96.31mA
-1V       70.7mA     79.63mA    69.41mA
-963.6mV  50.3mA     59.44mA    47.21mA
-927.3mV  33.48mA    42.27mA    29.73mA
-890.9mV  23.56mA    30.73mA    21mA
-818.2mV  10.72mA    13.8mA     11.42mA
-709.1mV  5.624mA    4.312mA    7.236mA
-527.3mV  1.606mA    1.01mA     1.915mA
-381.8mV  142.3uA    117.5uA    127.8uA
1.764V    -143.5uA   -80.17uA   -225.9uA
[Pulldown]
-1.8V     -10.49mA   -6.992mA   -6.878mA
-1.145V   -14.77mA   -9.642mA   -12.54mA
-872.7mV  -19.18mA   -11.58mA   -26.88mA
-600mV    -17.64mA   -11.15mA   -24.61mA
1.636V    48.04mA    29.95mA    67.37mA
2.073V    58.21mA    34.18mA    83.2mA
2.291V    61.28mA    32.65mA    90.41mA
2.455V    60.33mA    29.78mA    94.55mA
2.618V    57.37mA    25.94mA    94.82mA
2.782V    51.43mA    22.55mA    92.84mA
3.055V    43.59mA    17.92mA    79.47mA
3.545V    32.43mA    11.97mA    65.61mA
[Pullup]
-1.8V     15.27mA    9.71mA     21.85mA
-818.2mV  16.05mA    10.88mA    21.94mA
-490.9mV  13.72mA    9.223mA    18.66mA
1.036V    -30.45mA   -20.11mA   -41.15mA
2.018V    -57.22mA   -36.91mA   -78.08mA
2.345V    -64.63mA   -38.19mA   -89.73mA
2.618V    -65.01mA   -33.11mA   -96.69mA
2.782V    -59.96mA   -28.87mA   -97.07mA
2.836V    -57.32mA   -27.51mA   -95.25mA
3V        -50.25mA   -24.09mA   -80.87mA
3.218V    -42.03mA   -20.43mA   -58.16mA
3.545V    -34.78mA   -15.26mA   -32.29mA
[GND_clamp]
-1.8V     -697.8mA   -553.3mA   -1.259A
-1.145V   -140.7mA   -131.7mA   -248.4mA
-1.109V   -115.2mA   -111.7mA   -203.4mA
-1.036V   -69.7mA    -74.11mA   -126mA
-1V       -53.27mA   -58.3mA    -96.66mA
-927.3mV  -28.09mA   -31.91mA   -45.55mA
-890.9mV  -20.27mA   -23.39mA   -28.66mA
-854.5mV  -14.02mA   -16.45mA   -16.77mA
-818.2mV  -9.337mA   -11.08mA   -9.893mA
-672.7mV  -3.466mA   -3.226mA   -3.973mA
-18.18mV  0A         0A         0A
3.6V      0A         0A         0A
[Ramp]
dV/dt_f 0.74322799/0.14126105n 0.55025203/0.29314368n 0.90205253/80.90041p
dV/dt_r 0.66807245/0.12557404n 0.50966594/0.24636347n 0.81085041/77.399484p
R_load = 50
[Rising Waveform]
R_fixture = 50
V_fixture = 1.8
V_fixture_min = 1.62
V_fixture_max = 1.98
65.02ps   703.3mV    810mV      631.5mV
86.37ps   703.3mV    810mV      831.6mV
137.9ps   703.4mV    810mV      1.623V
200ps     702.7mV    810mV      1.878V
373.8ps   756mV      810mV      1.947V
487.8ps   1.525V     810mV      1.96V
569.2ps   1.708V     810mV      1.965V
1.037ns   1.782V     831.3mV    1.977V
1.337ns   1.79V      1.494V     1.979V
1.796ns   1.8V       1.62V      1.98V
[Rising Waveform]
R_fixture = 50
V_fixture = 0
V_fixture_min = 0
V_fixture_max = 0
78.17ps   2.802mV    1.768mV    3.967mV
166.4ps   2.838mV    1.768mV    988.5mV
261.1ps   2.523mV    1.769mV    1.228V
405ps     -13.97mV   1.761mV    1.283V
547.9ps   796.3mV    1.768mV    1.301V
703.9ps   994.4mV    1.789mV    1.309V
1.159ns   1.058V     -43.89mV   1.318V
1.372ns   1.064V     463.6mV    1.32V
1.513ns   1.066V     649.1mV    1.321V
2.202ns   1.078V     802.6mV    1.324V
[Falling Waveform]
R_fixture = 50
V_fixture = 1.8
V_fixture_min = 1.62
V_fixture_max = 1.98
56.22ps   1.8V       1.62V      1.98V
142.1ps   1.809V     1.62V      975.5mV
175ps     1.821V     1.62V      797.2mV
223.7ps   1.846V     1.62V      714mV
340.5ps   1.903V     1.62V      669mV
515.8ps   1.002V     1.62V      650.3mV
656.8ps   777.6mV    1.62V      643.8mV
1.066ns   722.3mV    1.716V     636.8mV
1.531ns   712.9mV    960.7mV    633.7mV
2.121ns   703.3mV    810mV      631.5mV
[Falling Waveform]
R_fixture = 50
V_fixture = 0
V_fixture_min = 0
V_fixture_max = 0
0s        1.078V     802.6mV    1.324V
28.99ps   1.077V     802.6mV    1.108V
100.7ps   1.078V     802.6mV    299.7mV
152.8ps   1.089V     802.6mV    97.78mV
258ps     1.033V     802.6mV    50.88mV
408.1ps   299mV      802.6mV    29.03mV
495.9ps   88.26mV    802.4mV    22.85mV
940.1ps   21.67mV    773.3mV    10.56mV
1.27ns    14.18mV    122.8mV    6.619mV
1.713ns   2.802mV    1.768mV    3.967mV
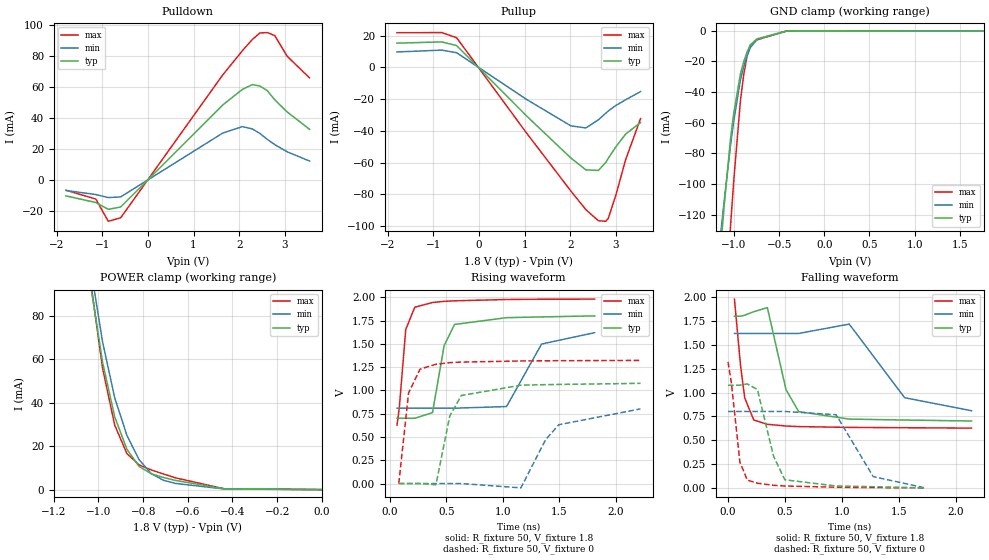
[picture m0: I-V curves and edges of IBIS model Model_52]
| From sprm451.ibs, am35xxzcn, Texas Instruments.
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| Model based on original model for BQ1833DV40DTPBFHP18LL_7LM_X50
|   Sub model LM_X50_PD_PU_OFF_1P8
[model]   Model_52
|[Description]  1.8V-I/O-PI-X
|[Input Load]   PI
|[Output Drive]
|Voltage   1.8V
|Mode   I/O
Model_type   I/O
Polarity   Non-Inverting
Enable   Active-Low
Vinl =  0.63V
Vinh =  1.17V
Cref =  15pF
Rref =  100.0000M
Vref =  0V
Vmeas =  0.9
C_comp   2.258279p   2.108893p   2.320297p
[Model Spec]
Vinl   0.63V   0.567V   0.693V
Vinh   1.17V   1.053V   1.287V
[Temperature Range]   25   125   -40
[Voltage Range]   1.8   1.62   1.98
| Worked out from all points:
|   slope of the pulldown table from 0 to 0.27 V, typ, clamps not added: 31.4 ohm
|   slope of the pullup table from 0 to 0.27 V, typ, clamps not added: 33.4 ohm
|   GND clamp passes 1 mA (typ) near -0.54 V on its own axis
|   POWER clamp passes 1 mA (typ) near -0.49 V on its own axis
|   rising waveform, R_fixture 50, V_fixture 1.8: 20-80 % time 96.8ps typ, 193ps min, 58.5ps max; typ from 0.702 V to 1.8 V
|   rising waveform, R_fixture 50, V_fixture 0: 20-80 % time 126ps typ, 248ps min, 77.5ps max; typ from 0 V to 1.08 V
|   falling waveform, R_fixture 50, V_fixture 1.8: 20-80 % time 134ps typ, 278ps min, 76.8ps max; typ from 1.8 V to 0.702 V
|   falling waveform, R_fixture 50, V_fixture 0: 20-80 % time 137ps typ, 214ps min, 71.4ps max; typ from 1.08 V to 0 V
[POWER_clamp]
-1.8V     842.2mA    869.2mA    912.6mA
-1.055V   109.1mA    116.8mA    112.5mA
-1.036V   94.66mA    102.8mA    96.26mA
-981.8mV  58.67mA    68.01mA    55.9mA
-927.3mV  33.44mA    42.25mA    29.67mA
-872.7mV  18.56mA    24.94mA    16.57mA
-818.2mV  10.68mA    13.78mA    11.36mA
-763.6mV  7.313mA    7.334mA    9.056mA
-709.1mV  5.588mA    4.293mA    7.178mA
-654.5mV  4.216mA    2.83mA     5.403mA
-436.4mV  387.4uA    279.4uA    353.6uA
0V        17.81nA    62.47nA    29.22nA
[Pulldown]
-1.8V     -10.49mA   -6.992mA   -6.878mA
-1.145V   -14.77mA   -9.642mA   -12.54mA
-872.7mV  -19.17mA   -11.58mA   -26.88mA
-600mV    -17.64mA   -11.15mA   -24.61mA
1.636V    48.04mA    29.95mA    67.37mA
2.073V    58.21mA    34.18mA    83.2mA
2.291V    61.28mA    32.65mA    90.41mA
2.455V    60.33mA    29.78mA    94.55mA
2.618V    57.37mA    25.94mA    94.82mA
2.782V    51.43mA    22.55mA    92.84mA
3.055V    43.59mA    17.92mA    79.47mA
3.545V    32.43mA    11.97mA    65.61mA
[Pullup]
-1.8V     15.27mA    9.71mA     21.85mA
-818.2mV  16.05mA    10.88mA    21.94mA
-490.9mV  13.72mA    9.223mA    18.66mA
1.036V    -30.46mA   -20.11mA   -41.15mA
2.018V    -57.22mA   -36.91mA   -78.08mA
2.345V    -64.63mA   -38.19mA   -89.73mA
2.618V    -65.01mA   -33.11mA   -96.69mA
2.782V    -59.96mA   -28.87mA   -97.07mA
2.836V    -57.31mA   -27.51mA   -95.24mA
3V        -50.25mA   -24.09mA   -80.86mA
3.218V    -42.03mA   -20.43mA   -58.16mA
3.545V    -34.78mA   -15.26mA   -32.29mA
[GND_clamp]
-1.8V     -697.8mA   -553.2mA   -1.259A
-1.145V   -140.6mA   -131.7mA   -248.3mA
-1.109V   -115.1mA   -111.6mA   -203.3mA
-1.036V   -69.6mA    -74.06mA   -125.9mA
-1V       -53.16mA   -58.25mA   -96.51mA
-927.3mV  -27.95mA   -31.85mA   -45.33mA
-890.9mV  -20.12mA   -23.33mA   -28.4mA
-854.5mV  -13.86mA   -16.38mA   -16.48mA
-818.2mV  -9.16mA    -11mA      -9.576mA
-745.5mV  -5.269mA   -5.602mA   -5.948mA
-418.2mV  -131.7uA   -213.2uA   -104.8uA
1.764V    17.26nA    527.4nA    24.83nA
[Ramp]
dV/dt_f 0.74424878/0.14163278n 0.55081222/0.29374304n 0.90374433/81.171093p
dV/dt_r 0.66923909/0.12624472n 0.51047828/0.24722722n 0.81251592/77.935129p
R_load = 50
[Rising Waveform]
R_fixture = 50
V_fixture = 1.8
V_fixture_min = 1.62
V_fixture_max = 1.98
62.62ps   701.5mV    809.1mV    626.7mV
82.22ps   701.5mV    809.1mV    804.5mV
140.2ps   701.6mV    809.1mV    1.656V
220.4ps   700.3mV    809.1mV    1.893V
376.8ps   762.2mV    809.1mV    1.944V
479.4ps   1.48V      809.1mV    1.956V
571.6ps   1.708V     809mV      1.962V
1.032ns   1.781V     826.7mV    1.976V
1.342ns   1.789V     1.498V     1.979V
1.812ns   1.8V       1.62V      1.98V
[Rising Waveform]
R_fixture = 50
V_fixture = 0
V_fixture_min = 0
V_fixture_max = 0
78.35ps   9.859nV    108.8nV    8.928nV
164.9ps   40.02uV    156nV      972.1mV
266.2ps   -546.8uV   1.134uV    1.228V
407.3ps   -12.45mV   -7.371uV   1.281V
529.5ps   724.6mV    -3.736uV   1.298V
631.8ps   945.5mV    24.06uV    1.304V
1.159ns   1.056V     -46.28mV   1.316V
1.377ns   1.062V     469.6mV    1.318V
1.494ns   1.064V     631.4mV    1.319V
2.218ns   1.076V     801.7mV    1.322V
[Falling Waveform]
R_fixture = 50
V_fixture = 1.8
V_fixture_min = 1.62
V_fixture_max = 1.98
56.3ps    1.8V       1.62V      1.98V
109.3ps   1.801V     1.62V      1.291V
146.3ps   1.811V     1.62V      944.7mV
225.7ps   1.848V     1.62V      711.9mV
345.3ps   1.891V     1.62V      666.8mV
508.4ps   1.031V     1.62V      648.8mV
619.8ps   799.9mV    1.62V      642.8mV
1.063ns   721.5mV    1.718V     634.2mV
1.549ns   711.5mV    945.7mV    630.9mV
2.136ns   701.5mV    809.1mV    626.7mV
[Falling Waveform]
R_fixture = 50
V_fixture = 0
V_fixture_min = 0
V_fixture_max = 0
0s        1.076V     801.7mV    1.322V
29.07ps   1.076V     801.7mV    1.106V
104.2ps   1.077V     801.7mV    270.1mV
168.7ps   1.09V      801.7mV    81.93mV
258.1ps   1.031V     801.7mV    48.48mV
399.2ps   332.4mV    801.7mV    26.79mV
498.5ps   84.56mV    801.5mV    19.4mV
948.1ps   19.38mV    767mV      6.622mV
1.274ns   11.89mV    117.7mV    2.671mV
1.727ns   9.859nV    108.8nV    8.928nV
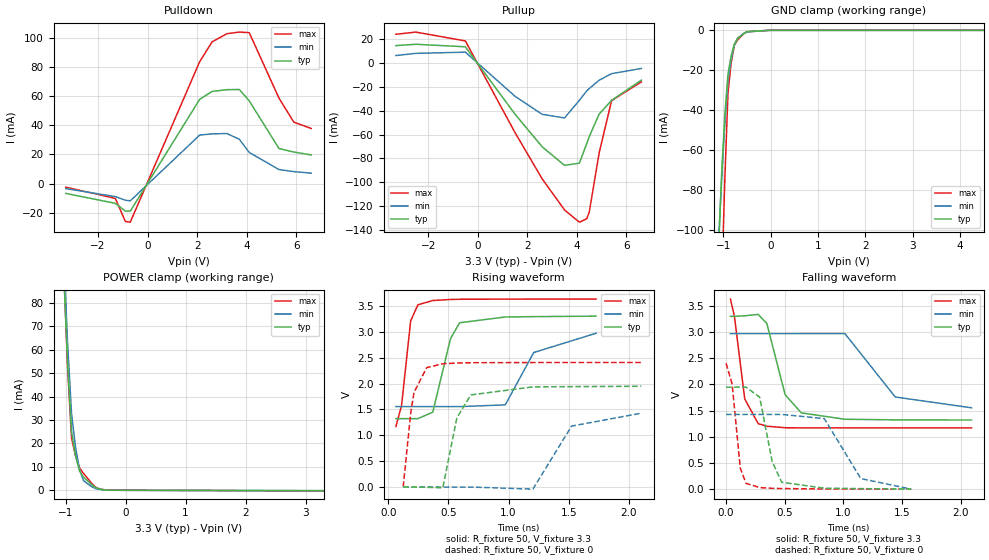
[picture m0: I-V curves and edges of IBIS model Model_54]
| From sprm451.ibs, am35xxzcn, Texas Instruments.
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| Model based on original model for BQ1833DV40DTPBFHP18LL_7LM_X50
|   Sub model LL_7LM_X50_PU_ON_3P3
[model]   Model_54
|[Description]  3.3V-I/O-PU-X
|[Input Load]   PU
|[Output Drive]
|Voltage   3.3V
|Mode   I/O
Model_type   I/O
Polarity   Non-Inverting
Enable   Active-Low
Vinl =  0.8V
Vinh =  2V
Cref =  15pF
Rref =  100.0000M
Vref =  0V
Vmeas =  1.65
C_comp   1.964904p   1.748404p   2.088782p
[Model Spec]
Vinl   0.8V   0.8V   0.8V
Vinh   2V   2V   2V
[Temperature Range]   25   125   -40
[Voltage Range]   3.3   2.97   3.63
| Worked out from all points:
|   slope of the pulldown table from 0 to 0.495 V, typ, clamps not added: 31.5 ohm
|   slope of the pullup table from 0 to 0.495 V, typ, clamps not added: 34.1 ohm
|   GND clamp passes 1 mA (typ) near -0.52 V on its own axis
|   POWER clamp passes 1 mA (typ) near -0.48 V on its own axis
|   rising waveform, R_fixture 50, V_fixture 3.3: 20-80 % time 121ps typ, 219ps min, 65.7ps max; typ from 1.32 V to 3.3 V
|   rising waveform, R_fixture 50, V_fixture 0: 20-80 % time 113ps typ, 209ps min, 73.5ps max; typ from 0.003 V to 1.95 V
|   falling waveform, R_fixture 50, V_fixture 3.3: 20-80 % time 146ps typ, 268ps min, 85.7ps max; typ from 3.3 V to 1.32 V
|   falling waveform, R_fixture 50, V_fixture 0: 20-80 % time 101ps typ, 186ps min, 59.5ps max; typ from 1.95 V to 0.003 V
[POWER_clamp]
-3.3V     2.432A     2.868A     2.62A
-1.033V   95.08mA    103.2mA    96.86mA
-966.7mV  54.92mA    63.38mA    53.02mA
-900mV    25.2mA     32.75mA    22.32mA
-833.3mV  14.73mA    18.43mA    14.71mA
-766.7mV  8.199mA    8.88mA     9.664mA
-700mV    5.588mA    4.11mA     7.196mA
-566.7mV  2.492mA    1.585mA    3.092mA
-500mV    1.193mA    763uA      1.348mA
-433.3mV  535.3uA    364.9uA    567.5uA
-300mV    28.66uA    27.24uA    30.96uA
3.3V      -177.5uA   -143.2uA   -277.3uA
[Pulldown]
-3.3V     -6.752mA   -3.455mA   -2.453mA
-1.3V     -13.57mA   -8.914mA   -10.17mA
-900mV    -18.88mA   -11.42mA   -25.93mA
-700mV    -18.93mA   -11.84mA   -26.49mA
2.1V      57.83mA    33.3mA     83.68mA
2.6V      63.26mA    34.15mA    97.27mA
3.2V      64.48mA    34.36mA    102.9mA
3.7V      64.6mA     30.45mA    104mA
4.1V      56.79mA    21.38mA    103.6mA
5.3V      24.05mA    9.632mA    58.63mA
5.9V      21.65mA    8.225mA    42.16mA
6.6V      19.68mA    7.168mA    37.84mA
[Pullup]
-3.3V     14.63mA    6.311mA    24.1mA
-2.5V     15.75mA    8.119mA    25.97mA
-500mV    13.64mA    9.134mA    18.56mA
1.5V      -42.79mA   -27.78mA   -58.19mA
2.6V      -70.29mA   -43mA      -97.17mA
3.5V      -85.79mA   -46.07mA   -123.2mA
4.1V      -84.01mA   -31.26mA   -133.5mA
4.4V      -67.36mA   -23.27mA   -130.6mA
4.5V      -61.7mA    -21.35mA   -124.8mA
4.9V      -42.71mA   -14.38mA   -75.13mA
5.4V      -31.3mA    -8.901mA   -31.49mA
6.6V      -14.33mA   -4.555mA   -15.8mA
[GND_clamp]
-3.3V     -2.048A    -1.805A    -3.667A
-1.1V     -108.7mA   -106.5mA   -191.5mA
-1.033V   -71.21mA   -74.08mA   -127.8mA
-966.7mV  -42.28mA   -46.87mA   -74.43mA
-900mV    -21.88mA   -24.94mA   -31.36mA
-833.3mV  -12.75mA   -14.54mA   -16.38mA
-766.7mV  -6.878mA   -7.548mA   -7.563mA
-700mV    -4.259mA   -3.966mA   -4.917mA
-566.7mV  -1.601mA   -1.571mA   -1.659mA
-500mV    -700.3uA   -785.2uA   -703.8uA
-33.33mV  0A         0A         0A
6.6V      0A         0A         0A
[Ramp]
dV/dt_f  1.2089244/0.14667502n 0.87056288/0.27074556n  1.4946333/86.194848p
dV/dt_r   1.201486/0.11352066n 0.89245721/0.21113366n  1.4660738/73.805021p
R_load = 50
[Rising Waveform]
R_fixture = 50
V_fixture = 3.3
V_fixture_min = 2.97
V_fixture_max = 3.63
63.42ps   1.322V     1.555V     1.171V
110.3ps   1.322V     1.555V     1.574V
185.8ps   1.322V     1.555V     3.207V
246.3ps   1.322V     1.555V     3.52V
370ps     1.448V     1.555V     3.602V
517.3ps   2.867V     1.554V     3.622V
593.1ps   3.173V     1.554V     3.626V
972.8ps   3.284V     1.588V     3.629V
1.209ns   3.291V     2.598V     3.63V
1.727ns   3.3V       2.97V      3.63V
[Rising Waveform]
R_fixture = 50
V_fixture = 0
V_fixture_min = 0
V_fixture_max = 0
124ps     3.38mV     2.142mV    4.745mV
185.5ps   3.585mV    2.141mV    1.412V
213.2ps   3.503mV    2.142mV    1.824V
318.9ps   -3.13mV    2.143mV    2.306V
453.1ps   -12.83mV   2.137mV    2.381V
570.2ps   1.337V     2.172mV    2.396V
686.1ps   1.78V      2.303mV    2.401V
1.202ns   1.935V     -39.15mV   2.405V
1.524ns   1.94V      1.178V     2.406V
2.104ns   1.947V     1.428V     2.405V
[Falling Waveform]
R_fixture = 50
V_fixture = 3.3
V_fixture_min = 2.97
V_fixture_max = 3.63
37.41ps   3.3V       2.97V      3.63V
71.26ps   3.3V       2.97V      3.301V
159.2ps   3.311V     2.97V      1.725V
274.1ps   3.337V     2.97V      1.253V
348.1ps   3.163V     2.97V      1.203V
503.8ps   1.805V     2.97V      1.175V
642ps     1.458V     2.972V     1.171V
1.013ns   1.336V     2.972V     1.172V
1.443ns   1.325V     1.761V     1.171V
2.093ns   1.322V     1.555V     1.171V
[Falling Waveform]
R_fixture = 50
V_fixture = 0
V_fixture_min = 0
V_fixture_max = 0
0s        1.947V     1.428V     2.405V
51.57ps   1.947V     1.428V     2.012V
121.6ps   1.95V      1.428V     400.7mV
170.3ps   1.95V      1.428V     112.8mV
286.5ps   1.757V     1.428V     32.86mV
393.4ps   529.3mV    1.428V     18.28mV
475.2ps   133.2mV    1.428V     13.82mV
837.9ps   20.81mV    1.349V     6.478mV
1.149ns   12.64mV    204.5mV    5.057mV
1.579ns   3.38mV     2.142mV    4.745mV
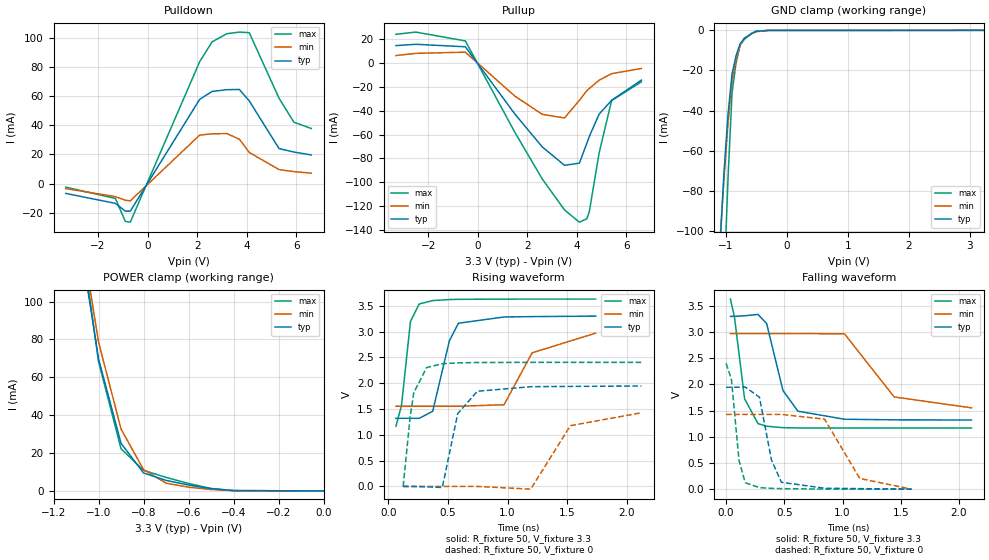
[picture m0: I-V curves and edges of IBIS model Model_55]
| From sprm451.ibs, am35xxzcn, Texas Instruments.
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| Model based on original model for BQ1833DV40DTPBFHP18LL_7LM_X50
|   Sub model LM_X50_PD_PU_OFF_3P3
[model]   Model_55
|[Description]  3.3V-I/O-PI-X
|[Input Load]   PI
|[Output Drive]
|Voltage   3.3V
|Mode   I/O
Model_type   I/O
Polarity   Non-Inverting
Enable   Active-Low
Vinl =  0.8V
Vinh =  2V
Cref =  15pF
Rref =  100.0000M
Vref =  0V
Vmeas =  1.65
C_comp   1.964904p   1.748404p   2.088782p
[Model Spec]
Vinl   0.8V   0.8V   0.8V
Vinh   2V   2V   2V
[Temperature Range]   25   125   -40
[Voltage Range]   3.3   2.97   3.63
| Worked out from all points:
|   slope of the pulldown table from 0 to 0.495 V, typ, clamps not added: 31.5 ohm
|   slope of the pullup table from 0 to 0.495 V, typ, clamps not added: 34.1 ohm
|   GND clamp passes 1 mA (typ) near -0.54 V on its own axis
|   POWER clamp passes 1 mA (typ) near -0.48 V on its own axis
|   rising waveform, R_fixture 50, V_fixture 3.3: 20-80 % time 121ps typ, 219ps min, 65.8ps max; typ from 1.32 V to 3.3 V
|   rising waveform, R_fixture 50, V_fixture 0: 20-80 % time 113ps typ, 211ps min, 73.9ps max; typ from 0 V to 1.95 V
|   falling waveform, R_fixture 50, V_fixture 3.3: 20-80 % time 147ps typ, 269ps min, 85.9ps max; typ from 3.3 V to 1.32 V
|   falling waveform, R_fixture 50, V_fixture 0: 20-80 % time 101ps typ, 186ps min, 59.6ps max; typ from 1.95 V to 0 V
[POWER_clamp]
-3.3V     2.432A     2.868A     2.62A
-1.067V   120.4mA    127.8mA    125.3mA
-1.033V   95.07mA    103.2mA    96.84mA
-1V       69.76mA    78.68mA    68.35mA
-900mV    25.18mA    32.74mA    22.3mA
-800mV    9.485mA    11.26mA    10.87mA
-700mV    5.568mA    4.099mA    7.163mA
-600mV    3.121mA    1.985mA    3.929mA
-500mV    1.172mA    751.7uA    1.314mA
-400mV    187uA      155.3uA    145.6uA
0V        9.358nA    43.99nA    36.65nA
[Pulldown]
-3.3V     -6.752mA   -3.455mA   -2.453mA
-1.3V     -13.57mA   -8.914mA   -10.17mA
-900mV    -18.88mA   -11.42mA   -25.92mA
-700mV    -18.93mA   -11.84mA   -26.49mA
2.1V      57.83mA    33.3mA     83.68mA
2.6V      63.26mA    34.15mA    97.27mA
3.2V      64.48mA    34.36mA    102.9mA
3.7V      64.6mA     30.45mA    104mA
4.1V      56.79mA    21.38mA    103.6mA
5.3V      24.05mA    9.632mA    58.63mA
5.9V      21.65mA    8.225mA    42.16mA
6.6V      19.68mA    7.168mA    37.84mA
[Pullup]
-3.3V     14.63mA    6.311mA    24.1mA
-2.5V     15.75mA    8.119mA    25.97mA
-500mV    13.64mA    9.134mA    18.56mA
1.5V      -42.79mA   -27.78mA   -58.2mA
2.6V      -70.29mA   -43mA      -97.17mA
3.5V      -85.79mA   -46.07mA   -123.2mA
4.1V      -84mA      -31.26mA   -133.5mA
4.4V      -67.35mA   -23.27mA   -130.6mA
4.5V      -61.7mA    -21.35mA   -124.8mA
4.9V      -42.71mA   -14.38mA   -75.13mA
5.4V      -31.3mA    -8.901mA   -31.49mA
6.6V      -14.33mA   -4.555mA   -15.8mA
[GND_clamp]
-3.3V     -2.048A    -1.805A    -3.667A
-1.1V     -108.6mA   -106.5mA   -191.4mA
-1.033V   -71.11mA   -74.03mA   -127.7mA
-966.7mV  -42.16mA   -46.82mA   -74.24mA
-900mV    -21.73mA   -24.87mA   -31.1mA
-833.3mV  -12.58mA   -14.46mA   -16.07mA
-766.7mV  -6.686mA   -7.459mA   -7.225mA
-700mV    -4.06mA    -3.869mA   -4.574mA
-566.7mV  -1.399mA   -1.472mA   -1.314mA
-500mV    -498.9uA   -685uA     -359.4uA
-300mV    -14.89uA   -26.01uA   -14.51uA
3.233V    8.831nA    14.59uA    33.57nA
[Ramp]
dV/dt_f  1.2102749/0.14704878n 0.87131344/0.27127121n  1.4966992/86.447448p
dV/dt_r  1.2031293/0.11394558n 0.89350552/0.21170078n  1.4681911/74.174164p
R_load = 50
[Rising Waveform]
R_fixture = 50
V_fixture = 3.3
V_fixture_min = 2.97
V_fixture_max = 3.63
63.57ps   1.32V      1.553V     1.167V
110.3ps   1.32V      1.553V     1.569V
185.7ps   1.32V      1.553V     3.2V
259.1ps   1.32V      1.553V     3.535V
371.9ps   1.456V     1.553V     3.601V
512.1ps   2.824V     1.553V     3.621V
587.6ps   3.162V     1.553V     3.625V
970.1ps   3.283V     1.583V     3.629V
1.205ns   3.29V      2.588V     3.63V
1.738ns   3.3V       2.97V      3.63V
[Rising Waveform]
R_fixture = 50
V_fixture = 0
V_fixture_min = 0
V_fixture_max = 0
124.2ps   8.754nV    122.9nV    4.075nV
183.5ps   206.3uV    -319nV     1.362V
213ps     126uV      247.3nV    1.814V
321.1ps   -7.115mV   1.551uV    2.303V
452.6ps   -20.47mV   -4.458uV   2.377V
581.4ps   1.41V      41.98uV    2.394V
745.9ps   1.844V     89.02uV    2.401V
1.193ns   1.932V     -52.66mV   2.404V
1.526ns   1.938V     1.177V     2.404V
2.121ns   1.946V     1.427V     2.404V
[Falling Waveform]
R_fixture = 50
V_fixture = 3.3
V_fixture_min = 2.97
V_fixture_max = 3.63
37.48ps   3.3V       2.97V      3.63V
72.29ps   3.3V       2.97V      3.286V
159.2ps   3.311V     2.97V      1.725V
274.2ps   3.337V     2.97V      1.252V
348.2ps   3.163V     2.97V      1.202V
488.7ps   1.884V     2.97V      1.174V
617ps     1.489V     2.971V     1.169V
1.017ns   1.335V     2.966V     1.168V
1.443ns   1.324V     1.761V     1.168V
2.107ns   1.32V      1.553V     1.167V
[Falling Waveform]
R_fixture = 50
V_fixture = 0
V_fixture_min = 0
V_fixture_max = 0
0s        1.946V     1.427V     2.404V
46.24ps   1.946V     1.427V     2.096V
111.2ps   1.947V     1.427V     548.5mV
164.9ps   1.95V      1.427V     121.8mV
286.6ps   1.755V     1.427V     29.87mV
390.3ps   554.3mV    1.427V     15.06mV
475.5ps   130.7mV    1.427V     10.02mV
846.1ps   18.22mV    1.337V     1.895mV
1.148ns   10.13mV    204.2mV    388.7uV
1.593ns   8.754nV    122.9nV    4.075nV
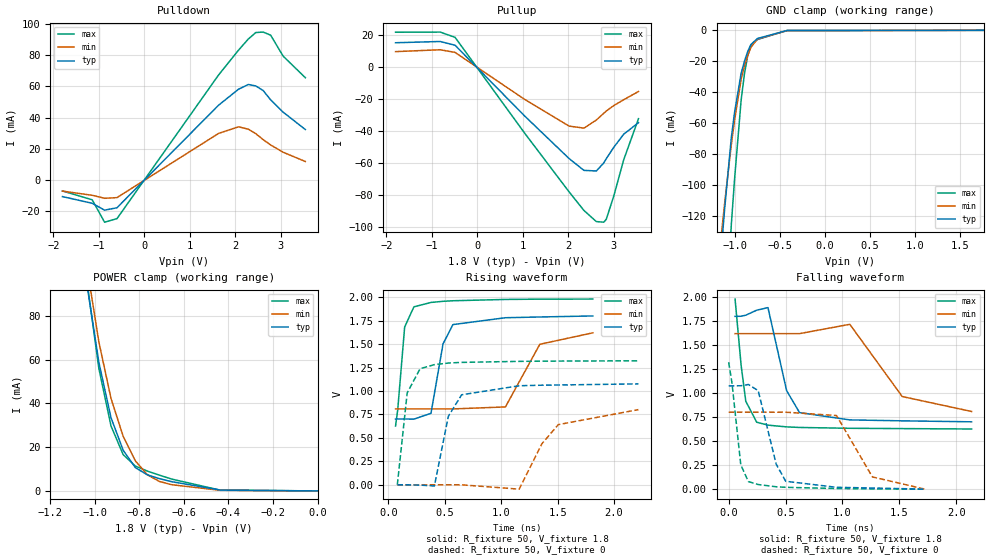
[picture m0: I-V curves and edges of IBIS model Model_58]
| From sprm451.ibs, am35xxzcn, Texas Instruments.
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| Model based on original model for BQ1833DV40DTPBFZP18LL_7LM_X50
|   Sub model LM_X50_PD_PU_OFF_1P8
[model]   Model_58
|[Description]  1.8V-I/O-PI-X
|[Input Load]   PI
|[Output Drive]
|Voltage   1.8V
|Mode   I/O
Model_type   I/O
Polarity   Non-Inverting
Enable   Active-Low
Vinl =  0.63V
Vinh =  1.17V
Cref =  15pF
Rref =  100.0000M
Vref =  0V
Vmeas =  0.9
C_comp   2.258279p   2.108893p   2.320297p
[Model Spec]
Vinl   0.63V   0.567V   0.693V
Vinh   1.17V   1.053V   1.287V
[Temperature Range]   25   125   -40
[Voltage Range]   1.8   1.62   1.98
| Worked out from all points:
|   slope of the pulldown table from 0 to 0.27 V, typ, clamps not added: 31.4 ohm
|   slope of the pullup table from 0 to 0.27 V, typ, clamps not added: 33.4 ohm
|   GND clamp passes 1 mA (typ) near -0.54 V on its own axis
|   POWER clamp passes 1 mA (typ) near -0.49 V on its own axis
|   rising waveform, R_fixture 50, V_fixture 1.8: 20-80 % time 96.3ps typ, 193ps min, 58.5ps max; typ from 0.702 V to 1.8 V
|   rising waveform, R_fixture 50, V_fixture 0: 20-80 % time 126ps typ, 246ps min, 77.5ps max; typ from 0 V to 1.08 V
|   falling waveform, R_fixture 50, V_fixture 1.8: 20-80 % time 134ps typ, 278ps min, 76.8ps max; typ from 1.8 V to 0.702 V
|   falling waveform, R_fixture 50, V_fixture 0: 20-80 % time 137ps typ, 214ps min, 71.3ps max; typ from 1.08 V to 0 V
[POWER_clamp]
-1.8V     842.2mA    869.2mA    912.6mA
-1.055V   109.1mA    116.8mA    112.5mA
-1.036V   94.66mA    102.8mA    96.26mA
-981.8mV  58.67mA    68.01mA    55.9mA
-927.3mV  33.44mA    42.25mA    29.67mA
-872.7mV  18.56mA    24.94mA    16.57mA
-818.2mV  10.68mA    13.78mA    11.36mA
-763.6mV  7.313mA    7.334mA    9.056mA
-709.1mV  5.588mA    4.293mA    7.178mA
-654.5mV  4.216mA    2.83mA     5.403mA
-436.4mV  387.4uA    279.4uA    353.6uA
0V        17.81nA    62.47nA    29.22nA
[Pulldown]
-1.8V     -10.49mA   -6.992mA   -6.878mA
-1.145V   -14.77mA   -9.642mA   -12.54mA
-872.7mV  -19.17mA   -11.58mA   -26.88mA
-600mV    -17.64mA   -11.15mA   -24.61mA
1.636V    48.04mA    29.95mA    67.37mA
2.073V    58.21mA    34.18mA    83.2mA
2.291V    61.28mA    32.65mA    90.41mA
2.455V    60.33mA    29.78mA    94.55mA
2.618V    57.37mA    25.94mA    94.82mA
2.782V    51.43mA    22.55mA    92.84mA
3.055V    43.59mA    17.92mA    79.47mA
3.545V    32.43mA    11.97mA    65.61mA
[Pullup]
-1.8V     15.27mA    9.71mA     21.85mA
-818.2mV  16.05mA    10.88mA    21.94mA
-490.9mV  13.72mA    9.223mA    18.66mA
1.036V    -30.46mA   -20.11mA   -41.15mA
2.018V    -57.22mA   -36.91mA   -78.08mA
2.345V    -64.63mA   -38.19mA   -89.73mA
2.618V    -65.01mA   -33.11mA   -96.69mA
2.782V    -59.96mA   -28.87mA   -97.07mA
2.836V    -57.31mA   -27.51mA   -95.24mA
3V        -50.25mA   -24.09mA   -80.86mA
3.218V    -42.03mA   -20.43mA   -58.16mA
3.545V    -34.78mA   -15.26mA   -32.29mA
[GND_clamp]
-1.8V     -697.8mA   -553.2mA   -1.259A
-1.145V   -140.6mA   -131.7mA   -248.3mA
-1.109V   -115.1mA   -111.6mA   -203.3mA
-1.036V   -69.6mA    -74.06mA   -125.9mA
-1V       -53.16mA   -58.25mA   -96.51mA
-927.3mV  -27.95mA   -31.85mA   -45.33mA
-890.9mV  -20.12mA   -23.33mA   -28.4mA
-854.5mV  -13.86mA   -16.38mA   -16.48mA
-818.2mV  -9.16mA    -11mA      -9.576mA
-745.5mV  -5.269mA   -5.602mA   -5.948mA
-418.2mV  -131.7uA   -213.2uA   -104.8uA
1.764V    17.26nA    527.4nA    24.83nA
[Ramp]
dV/dt_f  0.7442848/0.1416213n 0.55081501/0.29391692n  0.9037678/81.141453p
dV/dt_r 0.66923535/0.12626442n 0.51046937/0.24721243n 0.81251436/77.869267p
R_load = 50
[Rising Waveform]
R_fixture = 50
V_fixture = 1.8
V_fixture_min = 1.62
V_fixture_max = 1.98
62.62ps   701.5mV    809.1mV    626.7mV
82.24ps   701.5mV    809.1mV    804.8mV
143.3ps   701.6mV    809.1mV    1.682V
225.4ps   700.2mV    809.1mV    1.897V
376.8ps   762.2mV    809.1mV    1.944V
483.7ps   1.502V     809.1mV    1.956V
571.4ps   1.708V     809mV      1.962V
1.037ns   1.781V     830.3mV    1.976V
1.342ns   1.789V     1.498V     1.979V
1.812ns   1.8V       1.62V      1.98V
[Rising Waveform]
R_fixture = 50
V_fixture = 0
V_fixture_min = 0
V_fixture_max = 0
78.35ps   9.859nV    108.8nV    8.928nV
166ps     36.77uV    161.2nV    980.1mV
280.5ps   -2.694mV   1.226uV    1.238V
407.3ps   -12.39mV   -7.372uV   1.281V
530.8ps   730.2mV    -3.496uV   1.298V
648.7ps   959.6mV    29.61uV    1.305V
1.159ns   1.056V     -46.25mV   1.316V
1.362ns   1.062V     440.1mV    1.318V
1.506ns   1.064V     641.8mV    1.319V
2.217ns   1.076V     801.7mV    1.322V
[Falling Waveform]
R_fixture = 50
V_fixture = 1.8
V_fixture_min = 1.62
V_fixture_max = 1.98
56.31ps   1.8V       1.62V      1.98V
109.4ps   1.801V     1.62V      1.29V
150.5ps   1.812V     1.62V      915.7mV
246.4ps   1.864V     1.62V      697.5mV
345.4ps   1.891V     1.62V      666.8mV
509.7ps   1.026V     1.62V      648.7mV
623ps     797.5mV    1.62V      642.7mV
1.065ns   721.4mV    1.717V     634.1mV
1.526ns   711.7mV    964.8mV    630.9mV
2.136ns   701.5mV    809.1mV    626.7mV
[Falling Waveform]
R_fixture = 50
V_fixture = 0
V_fixture_min = 0
V_fixture_max = 0
0s        1.076V     801.7mV    1.322V
29.08ps   1.076V     801.7mV    1.106V
106.3ps   1.077V     801.7mV    254.4mV
173.2ps   1.09V      801.7mV    78.96mV
259.7ps   1.026V     801.7mV    48.04mV
417.6ps   260.7mV    801.7mV    25.1mV
501.7ps   82.03mV    801.5mV    19.2mV
948.1ps   19.37mV    767mV      6.617mV
1.264ns   12.04mV    127.3mV    2.745mV
1.727ns   9.859nV    108.8nV    8.928nV
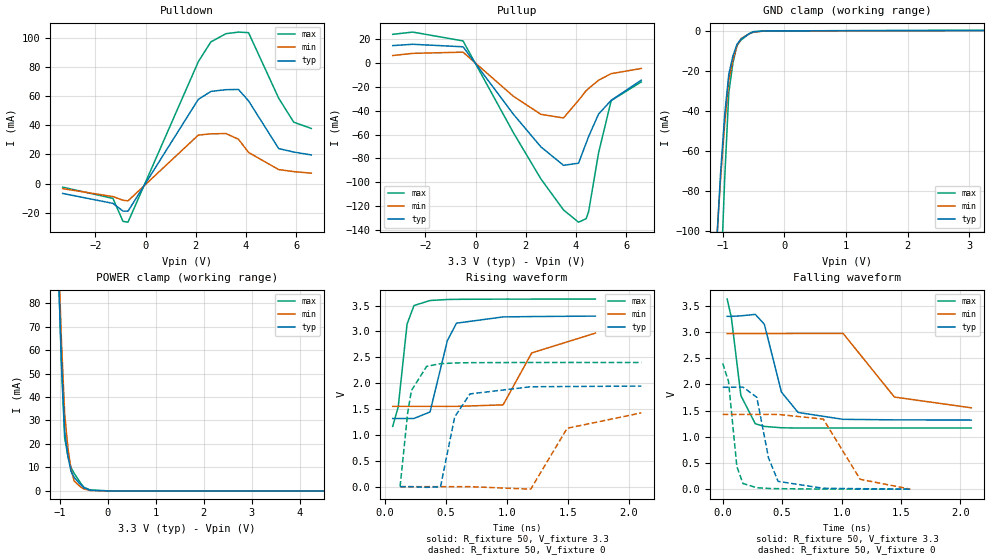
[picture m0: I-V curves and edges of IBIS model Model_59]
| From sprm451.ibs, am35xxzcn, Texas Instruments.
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| Model based on original model for BQ1833DV40DTPBFZP18LL_7LM_X50
|   Sub model LL_7LM_X50_PD_ON_3P3
[model]   Model_59
|[Description]  3.3V-I/O-PD-X
|[Input Load]   PD
|[Output Drive]
|Voltage   3.3V
|Mode   I/O
Model_type   I/O
Polarity   Non-Inverting
Enable   Active-Low
Vinl =  0.8V
Vinh =  2V
Cref =  15pF
Rref =  100.0000M
Vref =  0V
Vmeas =  1.65
C_comp   1.964904p   1.748404p   2.088782p
[Model Spec]
Vinl   0.8V   0.8V   0.8V
Vinh   2V   2V   2V
[Temperature Range]   25   125   -40
[Voltage Range]   3.3   2.97   3.63
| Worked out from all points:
|   slope of the pulldown table from 0 to 0.495 V, typ, clamps not added: 31.5 ohm
|   slope of the pullup table from 0 to 0.495 V, typ, clamps not added: 34.1 ohm
|   GND clamp passes 1 mA (typ) near -0.54 V on its own axis
|   POWER clamp passes 1 mA (typ) near -0.47 V on its own axis
|   rising waveform, R_fixture 50, V_fixture 3.3: 20-80 % time 121ps typ, 219ps min, 65.6ps max; typ from 1.32 V to 3.3 V
|   rising waveform, R_fixture 50, V_fixture 0: 20-80 % time 113ps typ, 210ps min, 73.6ps max; typ from 0 V to 1.94 V
|   falling waveform, R_fixture 50, V_fixture 3.3: 20-80 % time 146ps typ, 268ps min, 85.6ps max; typ from 3.3 V to 1.32 V
|   falling waveform, R_fixture 50, V_fixture 0: 20-80 % time 101ps typ, 186ps min, 59.3ps max; typ from 1.94 V to 0 V
[POWER_clamp]
-3.3V     2.432A     2.868A     2.62A
-1.033V   95.18mA    103.3mA    97.04mA
-966.7mV  55.02mA    63.43mA    53.21mA
-900mV    25.31mA    32.8mA     22.52mA
-833.3mV  14.85mA    18.49mA    14.91mA
-766.7mV  8.321mA    8.944mA    9.874mA
-700mV    5.714mA    4.176mA    7.411mA
-566.7mV  2.625mA    1.655mA    3.318mA
-500mV    1.329mA    834.5uA    1.58mA
-366.7mV  289.8uA    193.7uA    370.6uA
33.33mV   0A         0A         0A
6.6V      0A         0A         0A
[Pulldown]
-3.3V     -6.752mA   -3.455mA   -2.453mA
-1.3V     -13.57mA   -8.914mA   -10.17mA
-900mV    -18.88mA   -11.42mA   -25.92mA
-700mV    -18.93mA   -11.84mA   -26.49mA
2.1V      57.83mA    33.3mA     83.68mA
2.6V      63.26mA    34.15mA    97.27mA
3.2V      64.48mA    34.36mA    102.9mA
3.7V      64.6mA     30.45mA    104mA
4.1V      56.79mA    21.38mA    103.6mA
5.3V      24.05mA    9.632mA    58.63mA
5.9V      21.65mA    8.225mA    42.16mA
6.6V      19.68mA    7.168mA    37.84mA
[Pullup]
-3.3V     14.63mA    6.311mA    24.1mA
-2.5V     15.75mA    8.119mA    25.97mA
-500mV    13.64mA    9.134mA    18.56mA
1.5V      -42.79mA   -27.78mA   -58.2mA
2.6V      -70.29mA   -43mA      -97.17mA
3.5V      -85.79mA   -46.07mA   -123.2mA
4.1V      -84mA      -31.26mA   -133.5mA
4.4V      -67.35mA   -23.27mA   -130.6mA
4.5V      -61.7mA    -21.35mA   -124.8mA
4.9V      -42.71mA   -14.38mA   -75.13mA
5.4V      -31.3mA    -8.901mA   -31.49mA
6.6V      -14.33mA   -4.555mA   -15.8mA
[GND_clamp]
-3.3V     -2.048A    -1.805A    -3.667A
-1.1V     -108.6mA   -106.5mA   -191.4mA
-1.033V   -71.11mA   -74.03mA   -127.7mA
-966.7mV  -42.16mA   -46.82mA   -74.25mA
-900mV    -21.74mA   -24.87mA   -31.11mA
-833.3mV  -12.59mA   -14.46mA   -16.09mA
-766.7mV  -6.705mA   -7.466mA   -7.261mA
-700mV    -4.083mA   -3.879mA   -4.614mA
-566.7mV  -1.424mA   -1.483mA   -1.356mA
-500mV    -523uA     -696.8uA   -399.5uA
-300mV    -31.01uA   -34.87uA   -39.82uA
3.233V    152.3uA    97.89uA    242.6uA
[Ramp]
dV/dt_f  1.2091236/0.14658916n 0.87077041/0.27080478n  1.4948943/86.023366p
dV/dt_r  1.2018786/0.11363629n  0.8928316/0.21124792n  1.4662491/73.881603p
R_load = 50
[Rising Waveform]
R_fixture = 50
V_fixture = 3.3
V_fixture_min = 2.97
V_fixture_max = 3.63
63.75ps   1.318V     1.552V     1.166V
109ps     1.318V     1.552V     1.542V
181.6ps   1.318V     1.552V     3.143V
238.5ps   1.318V     1.552V     3.501V
370.2ps   1.444V     1.552V     3.598V
512.3ps   2.822V     1.552V     3.618V
587.4ps   3.16V      1.552V     3.621V
970.3ps   3.281V     1.581V     3.625V
1.205ns   3.288V     2.585V     3.625V
1.728ns   3.297V     2.968V     3.626V
[Rising Waveform]
R_fixture = 50
V_fixture = 0
V_fixture_min = 0
V_fixture_max = 0
124.3ps   8.544nV    119.7nV    4.096nV
186.2ps   204.5uV    -270.6nV   1.416V
217.2ps   102.7uV    306.9nV    1.857V
342.6ps   -13.02mV   1.428uV    2.326V
456.3ps   -2.467mV   -4.564uV   2.377V
572.7ps   1.349V     32.5uV     2.391V
698ps     1.793V     151.2uV    2.397V
1.197ns   1.931V     -48.06mV   2.4V
1.496ns   1.936V     1.129V     2.401V
2.105ns   1.944V     1.426V     2.4V
[Falling Waveform]
R_fixture = 50
V_fixture = 3.3
V_fixture_min = 2.97
V_fixture_max = 3.63
37.5ps    3.297V     2.968V     3.626V
72.47ps   3.296V     2.968V     3.279V
152.9ps   3.306V     2.968V     1.784V
274.1ps   3.334V     2.968V     1.248V
350.1ps   3.146V     2.968V     1.197V
494.3ps   1.85V      2.968V     1.171V
634.2ps   1.463V     2.97V      1.166V
1.013ns   1.332V     2.97V      1.167V
1.444ns   1.322V     1.757V     1.166V
2.091ns   1.318V     1.552V     1.166V
[Falling Waveform]
R_fixture = 50
V_fixture = 0
V_fixture_min = 0
V_fixture_max = 0
0s        1.944V     1.426V     2.4V
48.81ps   1.943V     1.426V     2.055V
118.9ps   1.946V     1.426V     431.3mV
170.3ps   1.947V     1.426V     107.7mV
286.9ps   1.752V     1.426V     27.67mV
385.3ps   596.2mV    1.426V     13.96mV
466ps     148.6mV    1.426V     9.332mV
846.3ps   17.03mV    1.336V     1.635mV
1.156ns   9.134mV    188.5mV    295.3uV
1.578ns   8.544nV    119.7nV    4.096nV
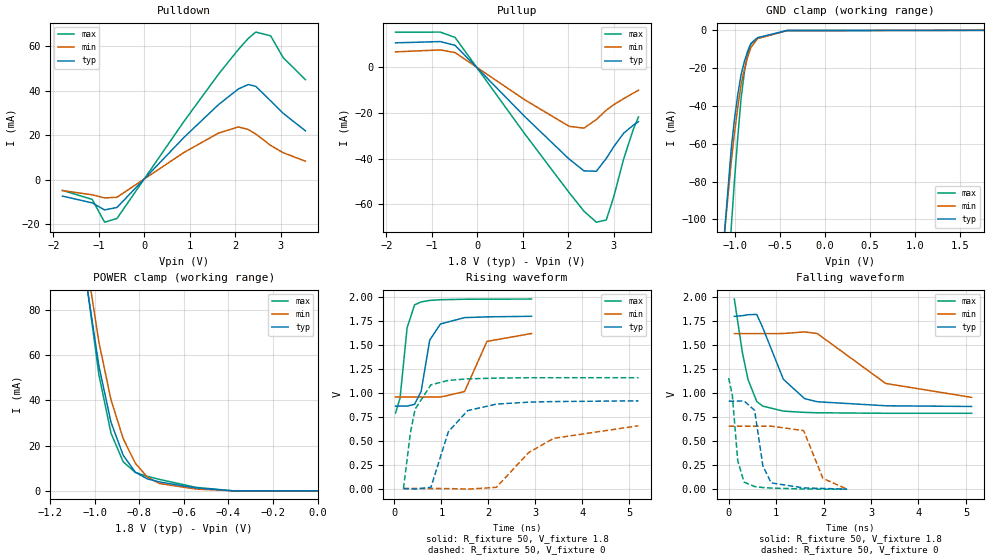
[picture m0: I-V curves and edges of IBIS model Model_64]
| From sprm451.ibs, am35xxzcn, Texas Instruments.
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| Model based on original model for BC1833DV50BTPBFHP18LL_7LM_X50
|   Sub model LM_X50_PD_PU_OFF_1P8
[model]   Model_64
|[Description]  1.8V-I/O-PI-X
|[Input Load]   PI
|[Output Drive]
|Voltage   1.8V
|Mode   I/O
Model_type   I/O
Polarity   Non-Inverting
Enable   Active-Low
Vinl =  0.63V
Vinh =  1.17V
Cref =  15pF
Rref =  100.0000M
Vref =  0V
Vmeas =  0.9
C_comp   1.952094p   1.82457p   1.99685p
[Model Spec]
Vinl   0.63V   0.567V   0.693V
Vinh   1.17V   1.053V   1.287V
[Temperature Range]   25   125   -40
[Voltage Range]   1.8   1.62   1.98
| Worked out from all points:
|   slope of the pulldown table from 0 to 0.27 V, typ, clamps not added: 44.5 ohm
|   slope of the pullup table from 0 to 0.27 V, typ, clamps not added: 47.5 ohm
|   GND clamp passes 1 mA (typ) near -0.57 V on its own axis
|   POWER clamp passes 1 mA (typ) near -0.52 V on its own axis
|   rising waveform, R_fixture 50, V_fixture 1.8: 20-80 % time 219ps typ, 288ps min, 153ps max; typ from 0.861 V to 1.8 V
|   rising waveform, R_fixture 50, V_fixture 0: 20-80 % time 446ps typ, 983ps min, 248ps max; typ from 0 V to 0.917 V
|   falling waveform, R_fixture 50, V_fixture 1.8: 20-80 % time 523ps typ, 1.19ns min, 279ps max; typ from 1.8 V to 0.861 V
|   falling waveform, R_fixture 50, V_fixture 0: 20-80 % time 165ps typ, 259ps min, 124ps max; typ from 0.917 V to 0 V
[POWER_clamp]
-1.8V     833.4mA    863.1mA    901.3mA
-1.055V   105.1mA    114.2mA    107.4mA
-1.036V   90.84mA    100.3mA    91.29mA
-981.8mV  55.17mA    65.7mA     51.32mA
-927.3mV  30.27mA    40.17mA    25.49mA
-872.7mV  15.75mA    23.12mA    12.86mA
-818.2mV  8.252mA    12.22mA    8.168mA
-763.6mV  5.284mA    6.038mA    6.409mA
-709.1mV  3.96mA     3.258mA    5.067mA
-545.5mV  1.312mA    822.8uA    1.581mA
-381.8mV  78.85uA    70.73uA    56.5uA
0V        17.8nA     61.32nA    29.21nA
[Pulldown]
-1.8V     -7.359mA   -4.884mA   -4.817mA
-1.145V   -10.42mA   -6.784mA   -8.841mA
-872.7mV  -13.57mA   -8.176mA   -19.09mA
-600mV    -12.48mA   -7.89mA    -17.42mA
872.7mV   18.97mA    12.22mA    26.15mA
1.636V    33.77mA    20.96mA    47.46mA
2.073V    40.79mA    23.72mA    58.54mA
2.291V    42.78mA    22.54mA    63.52mA
2.455V    41.93mA    20.49mA    66.32mA
2.782V    35.41mA    15.4mA     64.63mA
3.055V    29.87mA    12.14mA    54.89mA
3.545V    21.98mA    8.327mA    44.95mA
[Pullup]
-1.8V     10.75mA    6.804mA    15.41mA
-818.2mV  11.31mA    7.663mA    15.46mA
-490.9mV  9.668mA    6.495mA    13.14mA
1.036V    -21.39mA   -14.1mA    -28.91mA
2.018V    -40.11mA   -25.78mA   -54.77mA
2.345V    -45.27mA   -26.58mA   -62.92mA
2.618V    -45.47mA   -22.82mA   -67.76mA
2.836V    -39.88mA   -18.72mA   -66.81mA
3V        -34.74mA   -16.32mA   -56.71mA
3.218V    -28.82mA   -13.69mA   -40.13mA
3.436V    -25.21mA   -11.19mA   -26.84mA
3.545V    -23.75mA   -10mA      -21.69mA
[GND_clamp]
-1.8V     -667.9mA   -536.4mA   -1.146A
-1.109V   -105.7mA   -105.8mA   -172.9mA
-1.036V   -62.15mA   -69.31mA   -103.8mA
-1V       -46.69mA   -54.01mA   -78.79mA
-963.6mV  -33.78mA   -40.45mA   -56.18mA
-927.3mV  -23.42mA   -28.62mA   -35.93mA
-890.9mV  -16.46mA   -20.57mA   -22.13mA
-854.5mV  -10.97mA   -14.07mA   -12.5mA
-818.2mV  -6.96mA    -9.12mA    -7.043mA
-745.5mV  -3.86mA    -4.36mA    -4.33mA
-418.2mV  -108.5uA   -160.9uA   -94.49uA
1.764V    17.34nA    385nA      24.83nA
[Ramp]
dV/dt_f 0.57858729/0.52591044n 0.41207565/1.2020594n 0.72544172/0.28061355n
dV/dt_r 0.56445801/0.44634657n 0.40570119/0.98336285n 0.70408266/0.24778214n
R_load = 50
[Rising Waveform]
R_fixture = 50
V_fixture = 1.8
V_fixture_min = 1.62
V_fixture_max = 1.98
24.17ps   861.3mV    956mV      790.2mV
120.4ps   861.3mV    956mV      945.5mV
270ps     861.1mV    956mV      1.68V
428.8ps   880.1mV    956mV      1.919V
568.5ps   1.015V     956mV      1.95V
751.5ps   1.552V     956mV      1.966V
980.1ps   1.72V      956mV      1.973V
1.492ns   1.786V     1.013V     1.978V
1.97ns    1.794V     1.538V     1.979V
2.917ns   1.8V       1.62V      1.98V
[Rising Waveform]
R_fixture = 50
V_fixture = 0
V_fixture_min = 0
V_fixture_max = 0
192.7ps   9.923nV    95.96nV    10.68nV
339.8ps   -2.394mV   2.155uV    581.6mV
440.7ps   -5.267mV   215.9nV    830.2mV
776.8ps   12.67mV    -2.341uV   1.084V
1.148ns   594.1mV    -160.1uV   1.13V
1.558ns   814.4mV    -6.589mV   1.146V
2.17ns    882.1mV    12.92mV    1.154V
2.854ns   902.8mV    374.7mV    1.158V
3.389ns   908.8mV    524.7mV    1.158V
5.193ns   916.6mV    656.1mV    1.158V
[Falling Waveform]
R_fixture = 50
V_fixture = 1.8
V_fixture_min = 1.62
V_fixture_max = 1.98
119.4ps   1.8V       1.62V      1.98V
288ps     1.807V     1.62V      1.425V
408.8ps   1.817V     1.62V      1.14V
591.6ps   1.82V      1.62V      912.8mV
719.1ps   1.681V     1.62V      864.8mV
1.153ns   1.144V     1.621V     813.1mV
1.6ns     943mV      1.638V     799.5mV
1.867ns   910.5mV    1.621V     795.6mV
3.309ns   868.6mV    1.101V     790.4mV
5.119ns   861.3mV    956mV      790.2mV
[Falling Waveform]
R_fixture = 50
V_fixture = 0
V_fixture_min = 0
V_fixture_max = 0
0s        916.6mV    656.1mV    1.158V
76.36ps   916.3mV    656.1mV    982.9mV
191.1ps   917.2mV    656.1mV    296.3mV
323.3ps   919.3mV    656.1mV    73.68mV
546.8ps   821mV      656.2mV    27.59mV
720.5ps   243.4mV    656.1mV    16.94mV
895.6ps   64.93mV    656.2mV    11.48mV
1.58ns    13.06mV    609.7mV    1.773mV
1.986ns   7.428mV    111.7mV    562.9uV
2.499ns   9.923nV    95.96nV    10.68nV
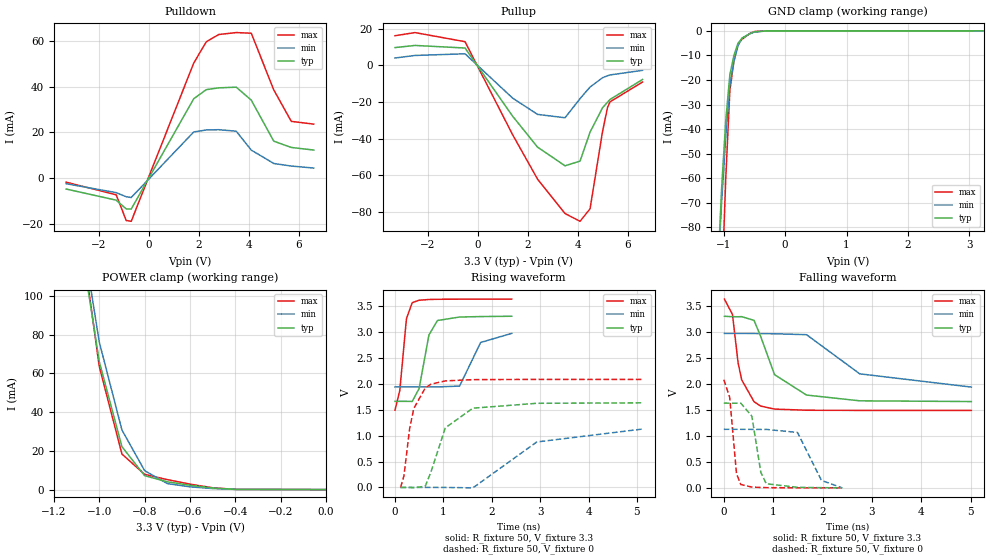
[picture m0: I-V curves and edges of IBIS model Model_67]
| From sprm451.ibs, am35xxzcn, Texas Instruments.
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| Model based on original model for BC1833DV50BTPBFHP18LL_7LM_X50
|   Sub model LM_X50_PD_PU_OFF_3P3
[model]   Model_67
|[Description]  3.3V-I/O-PI-X
|[Input Load]   PI
|[Output Drive]
|Voltage   3.3V
|Mode   I/O
Model_type   I/O
Polarity   Non-Inverting
Enable   Active-Low
Vinl =  0.8V
Vinh =  2V
Cref =  15pF
Rref =  100.0000M
Vref =  0V
Vmeas =  1.65
C_comp   1.683006p   1.492615p   1.787227p
[Model Spec]
Vinl   0.8V   0.8V   0.8V
Vinh   2V   2V   2V
[Temperature Range]   25   125   -40
[Voltage Range]   3.3   2.97   3.63
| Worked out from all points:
|   slope of the pulldown table from 0 to 0.495 V, typ, clamps not added: 44.5 ohm
|   slope of the pullup table from 0 to 0.495 V, typ, clamps not added: 49.1 ohm
|   GND clamp passes 1 mA (typ) near -0.56 V on its own axis
|   POWER clamp passes 1 mA (typ) near -0.51 V on its own axis
|   rising waveform, R_fixture 50, V_fixture 3.3: 20-80 % time 195ps typ, 279ps min, 122ps max; typ from 1.66 V to 3.3 V
|   rising waveform, R_fixture 50, V_fixture 0: 20-80 % time 428ps typ, 987ps min, 236ps max; typ from 0 V to 1.63 V
|   falling waveform, R_fixture 50, V_fixture 3.3: 20-80 % time 497ps typ, 969ps min, 226ps max; typ from 3.3 V to 1.66 V
|   falling waveform, R_fixture 50, V_fixture 0: 20-80 % time 155ps typ, 285ps min, 110ps max; typ from 1.63 V to 0 V
[POWER_clamp]
-3.3V     2.414A     2.856A     2.597A
-1.067V   116.4mA    125.1mA    120.2mA
-1.033V   91.29mA    100.7mA    91.93mA
-1V       66.19mA    76.32mA    63.69mA
-900mV    22.2mA     30.8mA     18.38mA
-800mV    7.208mA    9.795mA    7.881mA
-700mV    4.017mA    3.114mA    5.155mA
-600mV    2.246mA    1.437mA    2.828mA
-500mV    840.1uA    538.7uA    942.1uA
-400mV    133.3uA    110.7uA    103.8uA
0V        9.333nA    42.82nA    36.63nA
[Pulldown]
-3.3V     -4.669mA   -2.345mA   -1.683mA
-1.3V     -9.527mA   -6.237mA   -7.18mA
-900mV    -13.33mA   -8.043mA   -18.4mA
-700mV    -13.38mA   -8.364mA   -18.74mA
1.8V      34.72mA    20.23mA    50.28mA
2.3V      38.67mA    21.09mA    59.54mA
2.8V      39.47mA    21.22mA    62.74mA
3.5V      39.76mA    20.55mA    63.58mA
4.1V      34.11mA    12.32mA    63.3mA
5V        16.21mA    6.486mA    38.59mA
5.7V      13.47mA    5.354mA    24.85mA
6.6V      12.34mA    4.484mA    23.64mA
[Pullup]
-3.3V     9.738mA    4.045mA    16.21mA
-2.5V     10.91mA    5.432mA    17.94mA
-500mV    9.5mA      6.347mA    12.96mA
1.4V      -27.68mA   -17.82mA   -37.78mA
2.4V      -44.64mA   -26.76mA   -62.11mA
3.5V      -54.84mA   -28.6mA    -80.92mA
4.1V      -52.27mA   -18.13mA   -85.16mA
4.5V      -36.47mA   -11.82mA   -78.33mA
5V        -23.1mA    -6.724mA   -36.03mA
5.2V      -20.04mA   -5.652mA   -22.93mA
5.3V      -18.59mA   -5.203mA   -19.89mA
6.6V      -7.68mA    -2.683mA   -9.05mA
[GND_clamp]
-3.3V     -1.975A    -1.766A    -3.378A
-1.1V     -99.4mA    -100.8mA   -162mA
-1.033V   -63.74mA   -69.32mA   -106.1mA
-966.7mV  -36.56mA   -43.04mA   -60.17mA
-900mV    -17.88mA   -22mA      -24.31mA
-833.3mV  -9.995mA   -12.37mA   -12.32mA
-766.7mV  -5.035mA   -6.016mA   -5.345mA
-700mV    -2.995mA   -2.928mA   -3.372mA
-566.7mV  -1.037mA   -1.089mA   -982.7uA
-500mV    -379.4uA   -508.9uA   -286.6uA
-300mV    -14.25uA   -22.31uA   -14.38uA
3.233V    8.935nA    10.41uA    33.57nA
[Ramp]
dV/dt_f  0.9840264/0.49686375n 0.61917333/0.96341921n  1.2838169/0.22526778n
dV/dt_r  0.9837655/0.426144n  0.68058675/0.97772548n  1.2549269/0.23335071n
R_load = 50
[Rising Waveform]
R_fixture = 50
V_fixture = 3.3
V_fixture_min = 2.97
V_fixture_max = 3.63
2.32ps    1.66V      1.938V     1.49V
101.4ps   1.66V      1.938V     1.87V
238.9ps   1.66V      1.938V     3.254V
358.2ps   1.658V     1.938V     3.562V
500.4ps   1.907V     1.938V     3.609V
703.6ps   2.94V      1.938V     3.623V
879.4ps   3.218V     1.938V     3.627V
1.337ns   3.285V     1.954V     3.629V
1.771ns   3.294V     2.794V     3.63V
2.414ns   3.3V       2.97V      3.63V
[Rising Waveform]
R_fixture = 50
V_fixture = 0
V_fixture_min = 0
V_fixture_max = 0
117.2ps   8.36nV     112.1nV    4.117nV
187.8ps   2.405uV    -318.4nV   223.1mV
303.3ps   -255.2uV   -416.1nV   1.127V
390ps     -3.908mV   -10.37nV   1.522V
627.3ps   21.82mV    181nV      1.918V
745.9ps   301mV      83.26nV    1.991V
1.042ns   1.149V     12.09uV    2.054V
1.612ns   1.528V     -7.876mV   2.078V
2.93ns    1.622V     876.4mV    2.083V
5.117ns   1.631V     1.126V     2.082V
[Falling Waveform]
R_fixture = 50
V_fixture = 3.3
V_fixture_min = 2.97
V_fixture_max = 3.63
12.95ps   3.3V       2.97V      3.63V
175.7ps   3.292V     2.97V      3.335V
289.6ps   3.291V     2.97V      2.405V
362ps     3.293V     2.97V      2.078V
612.5ps   3.222V     2.969V     1.657V
745.9ps   2.914V     2.966V     1.573V
1.028ns   2.177V     2.964V     1.515V
1.675ns   1.785V     2.946V     1.493V
2.753ns   1.674V     2.193V     1.49V
5.013ns   1.66V      1.938V     1.49V
[Falling Waveform]
R_fixture = 50
V_fixture = 0
V_fixture_min = 0
V_fixture_max = 0
0s        1.631V     1.126V     2.082V
119.2ps   1.628V     1.126V     1.741V
257.7ps   1.628V     1.126V     271.7mV
345.2ps   1.628V     1.126V     63.79mV
568.1ps   1.379V     1.125V     15.72mV
749.8ps   298.6mV    1.124V     7.246mV
860.3ps   78.44mV    1.124V     4.147mV
1.492ns   10.4mV     1.066V     180.2uV
1.977ns   3.94mV     143.4mV    21.16uV
2.398ns   8.36nV     112.1nV    4.117nV
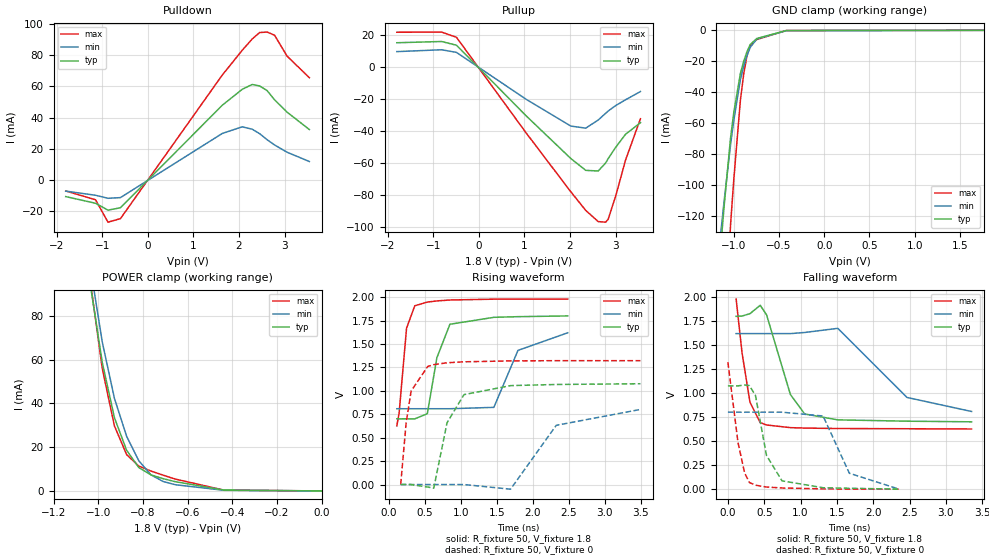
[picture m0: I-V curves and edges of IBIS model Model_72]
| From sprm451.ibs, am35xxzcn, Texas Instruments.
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| Model based on original model for BC1833DV40CTPBFHP18LL_7LM_X50
|   Sub model LM_X50_PD_PU_OFF_1P8
[model]   Model_72
|[Description]  1.8V-I/O-PI-X
|[Input Load]   PI
|[Output Drive]
|Voltage   1.8V
|Mode   I/O
Model_type   I/O
Polarity   Non-Inverting
Enable   Active-Low
Vinl =  0.63V
Vinh =  1.17V
Cref =  15pF
Rref =  100.0000M
Vref =  0V
Vmeas =  0.9
C_comp   2.232809p   2.073051p   2.295852p
[Model Spec]
Vinl   0.63V   0.567V   0.693V
Vinh   1.17V   1.053V   1.287V
[Temperature Range]   25   125   -40
[Voltage Range]   1.8   1.62   1.98
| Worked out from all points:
|   slope of the pulldown table from 0 to 0.27 V, typ, clamps not added: 31.4 ohm
|   slope of the pullup table from 0 to 0.27 V, typ, clamps not added: 33.4 ohm
|   GND clamp passes 1 mA (typ) near -0.54 V on its own axis
|   POWER clamp passes 1 mA (typ) near -0.49 V on its own axis
|   rising waveform, R_fixture 50, V_fixture 1.8: 20-80 % time 175ps typ, 263ps min, 97.1ps max; typ from 0.702 V to 1.8 V
|   rising waveform, R_fixture 50, V_fixture 0: 20-80 % time 229ps typ, 476ps min, 133ps max; typ from 0 V to 1.08 V
|   falling waveform, R_fixture 50, V_fixture 1.8: 20-80 % time 285ps typ, 649ps min, 155ps max; typ from 1.8 V to 0.702 V
|   falling waveform, R_fixture 50, V_fixture 0: 20-80 % time 210ps typ, 259ps min, 145ps max; typ from 1.08 V to 0 V
[POWER_clamp]
-1.8V     842.2mA    869.2mA    912.6mA
-1.055V   109.1mA    116.8mA    112.5mA
-1.036V   94.66mA    102.8mA    96.26mA
-981.8mV  58.67mA    68.01mA    55.9mA
-927.3mV  33.44mA    42.25mA    29.67mA
-872.7mV  18.56mA    24.94mA    16.57mA
-818.2mV  10.68mA    13.78mA    11.36mA
-763.6mV  7.313mA    7.334mA    9.056mA
-709.1mV  5.588mA    4.293mA    7.178mA
-654.5mV  4.216mA    2.83mA     5.403mA
-436.4mV  387.4uA    279.4uA    353.6uA
0V        17.81nA    62.47nA    29.22nA
[Pulldown]
-1.8V     -10.49mA   -6.992mA   -6.878mA
-1.145V   -14.77mA   -9.642mA   -12.54mA
-872.7mV  -19.17mA   -11.58mA   -26.88mA
-600mV    -17.64mA   -11.15mA   -24.61mA
1.636V    48.04mA    29.95mA    67.37mA
2.073V    58.21mA    34.18mA    83.2mA
2.291V    61.28mA    32.65mA    90.41mA
2.455V    60.33mA    29.78mA    94.55mA
2.618V    57.37mA    25.94mA    94.82mA
2.782V    51.43mA    22.55mA    92.84mA
3.055V    43.59mA    17.92mA    79.47mA
3.545V    32.43mA    11.97mA    65.61mA
[Pullup]
-1.8V     15.27mA    9.71mA     21.85mA
-818.2mV  16.05mA    10.88mA    21.94mA
-490.9mV  13.72mA    9.223mA    18.66mA
1.036V    -30.46mA   -20.11mA   -41.15mA
2.018V    -57.22mA   -36.91mA   -78.08mA
2.345V    -64.63mA   -38.19mA   -89.73mA
2.618V    -65.01mA   -33.11mA   -96.69mA
2.782V    -59.96mA   -28.87mA   -97.07mA
2.836V    -57.31mA   -27.51mA   -95.24mA
3V        -50.25mA   -24.09mA   -80.86mA
3.218V    -42.03mA   -20.43mA   -58.16mA
3.545V    -34.78mA   -15.26mA   -32.29mA
[GND_clamp]
-1.8V     -697.8mA   -553.2mA   -1.259A
-1.145V   -140.6mA   -131.7mA   -248.3mA
-1.109V   -115.1mA   -111.6mA   -203.3mA
-1.036V   -69.6mA    -74.06mA   -125.9mA
-1V       -53.16mA   -58.25mA   -96.51mA
-927.3mV  -27.95mA   -31.85mA   -45.33mA
-890.9mV  -20.12mA   -23.33mA   -28.4mA
-854.5mV  -13.86mA   -16.38mA   -16.48mA
-818.2mV  -9.16mA    -11mA      -9.576mA
-745.5mV  -5.269mA   -5.602mA   -5.948mA
-418.2mV  -131.7uA   -213.2uA   -104.8uA
1.764V    17.26nA    527.4nA    24.83nA
[Ramp]
dV/dt_f 0.72681948/0.29763456n 0.53631229/0.67625232n 0.88958768/0.16224868n
dV/dt_r 0.68218096/0.22740465n 0.51339518/0.47557392n 0.81343784/0.13274334n
R_load = 50
[Rising Waveform]
R_fixture = 50
V_fixture = 1.8
V_fixture_min = 1.62
V_fixture_max = 1.98
106.6ps   701.5mV    809.1mV    626.7mV
138.7ps   701.5mV    809.1mV    764.1mV
242ps     701.6mV    809.1mV    1.669V
356.2ps   701mV      809.1mV    1.908V
530.8ps   756.1mV    809.1mV    1.948V
663.5ps   1.353V     809.1mV    1.96V
844.8ps   1.711V     809.1mV    1.97V
1.456ns   1.785V     823.9mV    1.979V
1.791ns   1.792V     1.432V     1.979V
2.483ns   1.8V       1.62V      1.98V
[Rising Waveform]
R_fixture = 50
V_fixture = 0
V_fixture_min = 0
V_fixture_max = 0
160.4ps   9.859nV    108.8nV    8.928nV
235.9ps   21.42uV    2.984uV    654.7mV
305.1ps   -452.5uV   1.78uV     997.5mV
535.5ps   -26.59mV   -572nV     1.26V
620.4ps   -39.17mV   456.3pV    1.28V
805.1ps   660.1mV    -1.092uV   1.3V
1.041ns   959.9mV    -160.7uV   1.31V
1.688ns   1.056V     -49.59mV   1.32V
2.323ns   1.068V     632mV      1.322V
3.494ns   1.076V     801.7mV    1.322V
[Falling Waveform]
R_fixture = 50
V_fixture = 1.8
V_fixture_min = 1.62
V_fixture_max = 1.98
113.2ps   1.8V       1.62V      1.98V
194.3ps   1.803V     1.62V      1.42V
303.4ps   1.828V     1.62V      905.9mV
444.6ps   1.915V     1.62V      692.9mV
532.3ps   1.815V     1.62V      668.4mV
859.5ps   986.3mV    1.62V      640.7mV
1.057ns   782.7mV    1.632V     636.3mV
1.512ns   721.9mV    1.675V     631.7mV
2.465ns   708mV      955.2mV    629.3mV
3.353ns   701.5mV    809.1mV    626.7mV
[Falling Waveform]
R_fixture = 50
V_fixture = 0
V_fixture_min = 0
V_fixture_max = 0
0s        1.076V     801.7mV    1.322V
138.7ps   1.076V     801.7mV    485.5mV
229.8ps   1.085V     801.7mV    168.7mV
295.5ps   1.079V     801.7mV    69.7mV
379.3ps   976mV      801.7mV    41.32mV
530.9ps   351.6mV    801.7mV    22.31mV
743.8ps   87.04mV    801.7mV    12.22mV
1.31ns    14.74mV    762mV      2.853mV
1.671ns   9.398mV    165.8mV    1.001mV
2.356ns   9.859nV    108.8nV    8.928nV
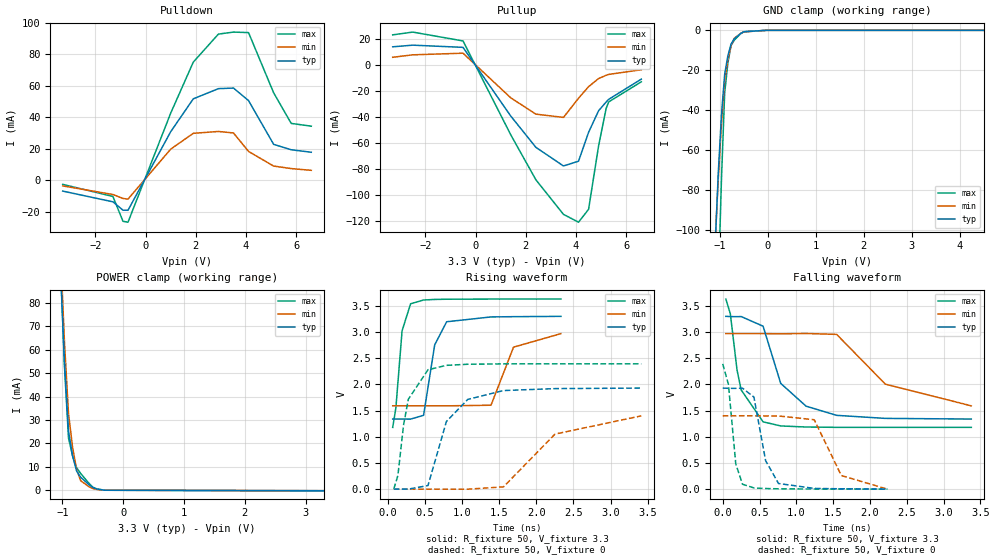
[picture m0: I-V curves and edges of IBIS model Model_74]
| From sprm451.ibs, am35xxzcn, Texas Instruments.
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| Model based on original model for BC1833DV40CTPBFHP18LL_7LM_X50
|   Sub model LL_7LM_X50_PU_ON_3P3
[model]   Model_74
|[Description]  3.3V-I/O-PU-X
|[Input Load]   PU
|[Output Drive]
|Voltage   3.3V
|Mode   I/O
Model_type   I/O
Polarity   Non-Inverting
Enable   Active-Low
Vinl =  0.8V
Vinh =  2V
Cref =  15pF
Rref =  100.0000M
Vref =  0V
Vmeas =  1.65
C_comp   1.943144p   1.721292p   2.064363p
[Model Spec]
Vinl   0.8V   0.8V   0.8V
Vinh   2V   2V   2V
[Temperature Range]   25   125   -40
[Voltage Range]   3.3   2.97   3.63
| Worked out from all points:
|   slope of the pulldown table from 0 to 0.495 V, typ, clamps not added: 31.5 ohm
|   slope of the pullup table from 0 to 0.495 V, typ, clamps not added: 34.6 ohm
|   GND clamp passes 1 mA (typ) near -0.52 V on its own axis
|   POWER clamp passes 1 mA (typ) near -0.48 V on its own axis
|   rising waveform, R_fixture 50, V_fixture 3.3: 20-80 % time 137ps typ, 201ps min, 89ps max; typ from 1.34 V to 3.3 V
|   rising waveform, R_fixture 50, V_fixture 0: 20-80 % time 312ps typ, 707ps min, 173ps max; typ from 0.003 V to 1.93 V
|   falling waveform, R_fixture 50, V_fixture 3.3: 20-80 % time 378ps typ, 808ps min, 190ps max; typ from 3.3 V to 1.34 V
|   falling waveform, R_fixture 50, V_fixture 0: 20-80 % time 157ps typ, 245ps min, 92.5ps max; typ from 1.93 V to 0.003 V
[POWER_clamp]
-3.3V     2.432A     2.868A     2.62A
-1.033V   95.08mA    103.2mA    96.86mA
-966.7mV  54.92mA    63.38mA    53.02mA
-900mV    25.2mA     32.75mA    22.32mA
-833.3mV  14.73mA    18.43mA    14.71mA
-766.7mV  8.199mA    8.88mA     9.664mA
-700mV    5.588mA    4.11mA     7.196mA
-566.7mV  2.492mA    1.585mA    3.092mA
-500mV    1.193mA    763uA      1.348mA
-433.3mV  535.3uA    364.9uA    567.5uA
-300mV    28.66uA    27.24uA    30.96uA
3.3V      -177.5uA   -143.2uA   -277.3uA
[Pulldown]
-3.3V     -6.73mA    -3.436mA   -2.446mA
-1.3V     -13.54mA   -8.893mA   -10.15mA
-900mV    -18.86mA   -11.4mA    -25.9mA
-700mV    -18.9mA    -11.82mA   -26.47mA
1V        30.96mA    19.89mA    42.74mA
1.9V      51.83mA    29.94mA    75.14mA
2.9V      58.3mA     31.12mA    92.92mA
3.5V      58.67mA    30.17mA    94.2mA
4.1V      50.73mA    18.46mA    93.88mA
5.1V      22.94mA    9.149mA    55.64mA
5.8V      19.5mA     7.56mA     36.23mA
6.6V      17.91mA    6.449mA    34.47mA
[Pullup]
-3.3V     13.88mA    5.843mA    23.08mA
-2.5V     15.16mA    7.729mA    25.2mA
-500mV    13.47mA    8.99mA     18.39mA
1.4V      -39.27mA   -25.27mA   -53.66mA
2.4V      -63.29mA   -37.81mA   -88.19mA
3.5V      -77.61mA   -40.33mA   -114.8mA
4.1V      -73.95mA   -25.59mA   -120.8mA
4.5V      -51.77mA   -16.71mA   -110.9mA
4.9V      -35.15mA   -10.47mA   -62.03mA
5.2V      -28.48mA   -7.948mA   -33.38mA
5.3V      -26.46mA   -7.311mA   -28.43mA
6.6V      -10.91mA   -3.736mA   -12.96mA
[GND_clamp]
-3.3V     -2.048A    -1.805A    -3.667A
-1.1V     -108.7mA   -106.5mA   -191.5mA
-1.033V   -71.21mA   -74.08mA   -127.8mA
-966.7mV  -42.28mA   -46.87mA   -74.43mA
-900mV    -21.88mA   -24.94mA   -31.36mA
-833.3mV  -12.75mA   -14.54mA   -16.38mA
-766.7mV  -6.878mA   -7.548mA   -7.563mA
-700mV    -4.259mA   -3.966mA   -4.917mA
-566.7mV  -1.601mA   -1.571mA   -1.659mA
-500mV    -700.3uA   -785.2uA   -703.8uA
-33.33mV  0A         0A         0A
6.6V      0A         0A         0A
[Ramp]
dV/dt_f  1.1889828/0.37568061n 0.84311434/0.79997722n  1.4742206/0.18989122n
dV/dt_r  1.1650202/0.30793731n 0.84546314/0.70126016n  1.4416224/0.17238007n
R_load = 50
[Rising Waveform]
R_fixture = 50
V_fixture = 3.3
V_fixture_min = 2.97
V_fixture_max = 3.63
67.2ps    1.34V      1.592V     1.181V
109.9ps   1.34V      1.592V     1.553V
193.3ps   1.34V      1.592V     3.024V
308.2ps   1.339V     1.592V     3.54V
482.9ps   1.411V     1.592V     3.612V
632.7ps   2.756V     1.592V     3.623V
793.6ps   3.197V     1.592V     3.627V
1.391ns   3.289V     1.604V     3.63V
1.694ns   3.294V     2.712V     3.63V
2.332ns   3.3V       2.97V      3.63V
[Rising Waveform]
R_fixture = 50
V_fixture = 0
V_fixture_min = 0
V_fixture_max = 0
81.58ps   3.383mV    2.143mV    4.747mV
137ps     3.383mV    2.144mV    262.6mV
212.8ps   3.394mV    2.143mV    1.221V
277.7ps   3.099mV    2.143mV    1.719V
542.3ps   70.28mV    2.143mV    2.281V
790.6ps   1.294V     2.143mV    2.365V
1.078ns   1.715V     1.747mV    2.386V
1.559ns   1.884V     45.82mV    2.393V
2.253ns   1.921V     1.053V     2.394V
3.415ns   1.931V     1.401V     2.394V
[Falling Waveform]
R_fixture = 50
V_fixture = 3.3
V_fixture_min = 2.97
V_fixture_max = 3.63
42.66ps   3.3V       2.97V      3.63V
103.2ps   3.296V     2.97V      3.351V
194.9ps   3.294V     2.97V      2.273V
250.7ps   3.296V     2.97V      1.896V
548.3ps   3.112V     2.97V      1.287V
787.6ps   2.021V     2.967V     1.209V
1.132ns   1.586V     2.973V     1.188V
1.547ns   1.411V     2.956V     1.182V
2.209ns   1.353V     2.006V     1.181V
3.376ns   1.34V      1.592V     1.181V
[Falling Waveform]
R_fixture = 50
V_fixture = 0
V_fixture_min = 0
V_fixture_max = 0
0s        1.931V     1.401V     2.394V
77.61ps   1.927V     1.401V     2.003V
177.3ps   1.926V     1.401V     486mV
268.7ps   1.929V     1.401V     96.86mV
424ps     1.759V     1.401V     25.36mV
582.6ps   546.5mV    1.4V       14.27mV
757.9ps   110.5mV    1.399V     8.857mV
1.243ns   16.48mV    1.327V     5.024mV
1.611ns   8.847mV    262.2mV    4.785mV
2.238ns   3.383mV    2.143mV    4.747mV
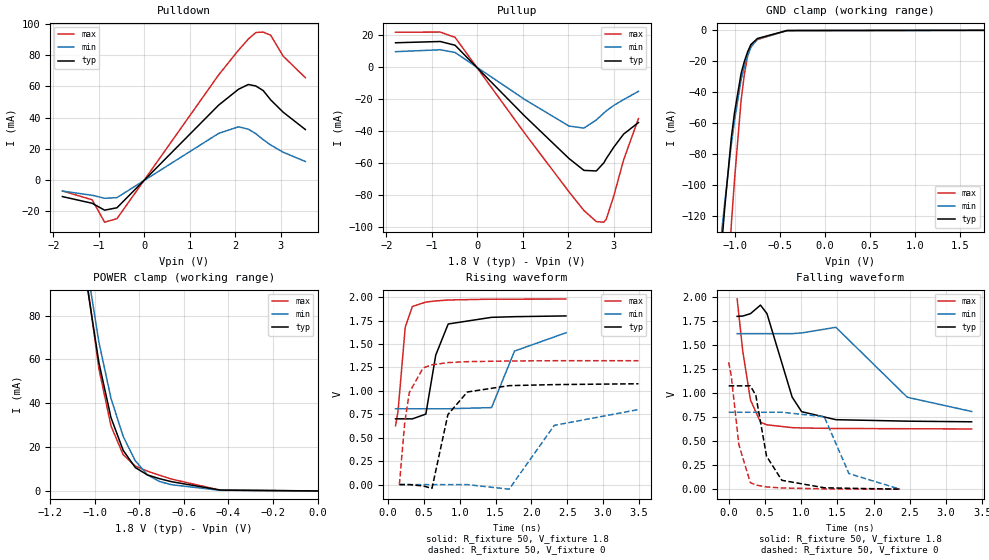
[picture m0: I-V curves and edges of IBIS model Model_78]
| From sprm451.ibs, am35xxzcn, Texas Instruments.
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| Model based on original model for BC1833DV40CTPBFZP18LL_7LM
|   Sub model LL_7LM_PD_PU_OFF_1P8
[model]   Model_78
|[Description]  1.8V-I/O-PI-X
|[Input Load]   PI
|[Output Drive]
|Voltage   1.8V
|Mode   I/O
Model_type   I/O
Polarity   Non-Inverting
Enable   Active-Low
Vinl =  0.63V
Vinh =  1.17V
Cref =  15pF
Rref =  100.0000M
Vref =  0V
Vmeas =  0.9
C_comp   2.232809p   2.073051p   2.295852p
[Model Spec]
Vinl   0.63V   0.567V   0.693V
Vinh   1.17V   1.053V   1.287V
[Temperature Range]   25   125   -40
[Voltage Range]   1.8   1.62   1.98
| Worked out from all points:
|   slope of the pulldown table from 0 to 0.27 V, typ, clamps not added: 31.5 ohm
|   slope of the pullup table from 0 to 0.27 V, typ, clamps not added: 33.5 ohm
|   GND clamp passes 1 mA (typ) near -0.54 V on its own axis
|   POWER clamp passes 1 mA (typ) near -0.49 V on its own axis
|   rising waveform, R_fixture 50, V_fixture 1.8: 20-80 % time 168ps typ, 246ps min, 94.6ps max; typ from 0.702 V to 1.8 V
|   rising waveform, R_fixture 50, V_fixture 0: 20-80 % time 227ps typ, 475ps min, 131ps max; typ from 0 V to 1.08 V
|   falling waveform, R_fixture 50, V_fixture 1.8: 20-80 % time 282ps typ, 649ps min, 154ps max; typ from 1.8 V to 0.702 V
|   falling waveform, R_fixture 50, V_fixture 0: 20-80 % time 204ps typ, 246ps min, 145ps max; typ from 1.08 V to 0 V
[POWER_clamp]
-1.8V     842.2mA    869.1mA    912.5mA
-1.055V   109mA      116.8mA    112.5mA
-1.036V   94.63mA    102.8mA    96.22mA
-981.8mV  58.65mA    67.99mA    55.86mA
-927.3mV  33.42mA    42.23mA    29.64mA
-872.7mV  18.54mA    24.92mA    16.54mA
-818.2mV  10.66mA    13.77mA    11.33mA
-763.6mV  7.291mA    7.319mA    9.029mA
-709.1mV  5.568mA    4.279mA    7.154mA
-654.5mV  4.197mA    2.818mA    5.381mA
-436.4mV  381.9uA    275.7uA    348.1uA
0V        17.81nA    62.52nA    29.22nA
[Pulldown]
-1.8V     -10.48mA   -6.986mA   -6.871mA
-1.145V   -14.76mA   -9.635mA   -12.53mA
-872.7mV  -19.16mA   -11.57mA   -26.86mA
-600mV    -17.63mA   -11.14mA   -24.6mA
1.636V    48.02mA    29.94mA    67.34mA
2.073V    58.19mA    34.17mA    83.16mA
2.291V    61.26mA    32.65mA    90.37mA
2.455V    60.31mA    29.78mA    94.52mA
2.618V    57.35mA    25.94mA    94.79mA
2.782V    51.42mA    22.55mA    92.8mA
3.055V    43.58mA    17.93mA    79.45mA
3.545V    32.44mA    11.99mA    65.6mA
[Pullup]
-1.8V     15.25mA    9.689mA    21.84mA
-818.2mV  16.04mA    10.87mA    21.92mA
-490.9mV  13.71mA    9.212mA    18.64mA
1.036V    -30.4mA    -20.07mA   -41.09mA
2.018V    -57.11mA   -36.81mA   -77.94mA
2.345V    -64.48mA   -38.06mA   -89.56mA
2.618V    -64.84mA   -32.95mA   -96.49mA
2.782V    -59.78mA   -28.7mA    -96.85mA
2.836V    -57.13mA   -27.34mA   -95.02mA
3V        -50.06mA   -23.92mA   -80.63mA
3.218V    -41.82mA   -20.26mA   -57.92mA
3.545V    -34.58mA   -15.09mA   -32.06mA
[GND_clamp]
-1.8V     -697.8mA   -553.2mA   -1.259A
-1.145V   -140.6mA   -131.7mA   -248.3mA
-1.109V   -115.1mA   -111.6mA   -203.3mA
-1.036V   -69.6mA    -74.07mA   -125.9mA
-1V       -53.16mA   -58.25mA   -96.51mA
-927.3mV  -27.95mA   -31.85mA   -45.33mA
-890.9mV  -20.12mA   -23.33mA   -28.4mA
-854.5mV  -13.86mA   -16.38mA   -16.49mA
-818.2mV  -9.165mA   -11mA      -9.583mA
-745.5mV  -5.275mA   -5.606mA   -5.955mA
-418.2mV  -132.4uA   -214.4uA   -105.2uA
1.764V    17.27nA    517.3nA    24.83nA
[Ramp]
dV/dt_f 0.72790979/0.29629198n 0.53680598/0.67655767n 0.89197507/0.16214684n
dV/dt_r 0.67919076/0.22567297n 0.51335242/0.47383479n 0.81249964/0.13161071n
R_load = 50
[Rising Waveform]
R_fixture = 50
V_fixture = 1.8
V_fixture_min = 1.62
V_fixture_max = 1.98
106.5ps   701.7mV    809.2mV    626.9mV
140.9ps   701.7mV    809.2mV    782.2mV
241.6ps   701.7mV    809.2mV    1.681V
341.3ps   701.2mV    809.2mV    1.901V
528.9ps   752.5mV    809.2mV    1.948V
666.8ps   1.382V     809.2mV    1.96V
840.4ps   1.714V     809.2mV    1.97V
1.445ns   1.785V     821.9mV    1.979V
1.765ns   1.792V     1.425V     1.979V
2.482ns   1.8V       1.62V      1.98V
[Rising Waveform]
R_fixture = 50
V_fixture = 0
V_fixture_min = 0
V_fixture_max = 0
159.6ps   9.701nV    106.6nV    8.922nV
234.3ps   27.29uV    3.035uV    659.5mV
298.5ps   -444.1uV   1.934uV    982.9mV
491ps     -14.74mV   -522.8nV   1.245V
614.5ps   -40.29mV   -2.729nV   1.278V
836ps     746.8mV    -2.273uV   1.302V
1.107ns   988.1mV    -296uV     1.312V
1.69ns    1.056V     -48.92mV   1.319V
2.319ns   1.067V     632mV      1.322V
3.493ns   1.076V     800.9mV    1.322V
[Falling Waveform]
R_fixture = 50
V_fixture = 1.8
V_fixture_min = 1.62
V_fixture_max = 1.98
116.8ps   1.8V       1.62V      1.98V
194.5ps   1.803V     1.62V      1.437V
300.4ps   1.828V     1.62V      930.1mV
438.9ps   1.917V     1.62V      696.7mV
528.5ps   1.828V     1.62V      670.1mV
875.8ps   958.9mV    1.62V      640.6mV
1.007ns   806.9mV    1.627V     637.5mV
1.479ns   723.7mV    1.686V     632.1mV
2.465ns   708.2mV    957mV      629.5mV
3.352ns   701.7mV    809.2mV    626.9mV
[Falling Waveform]
R_fixture = 50
V_fixture = 0
V_fixture_min = 0
V_fixture_max = 0
0s        1.076V     800.9mV    1.322V
34.59ps   1.076V     800.9mV    1.185V
140.9ps   1.076V     800.9mV    462.7mV
298.3ps   1.076V     800.9mV    69mV
374.4ps   978.1mV    800.9mV    42.89mV
522.4ps   343.8mV    800.9mV    23.25mV
734.3ps   92.05mV    800.9mV    12.57mV
1.319ns   14.5mV     754.9mV    2.74mV
1.659ns   9.462mV    162.2mV    1.011mV
2.364ns   9.701nV    106.6nV    8.922nV
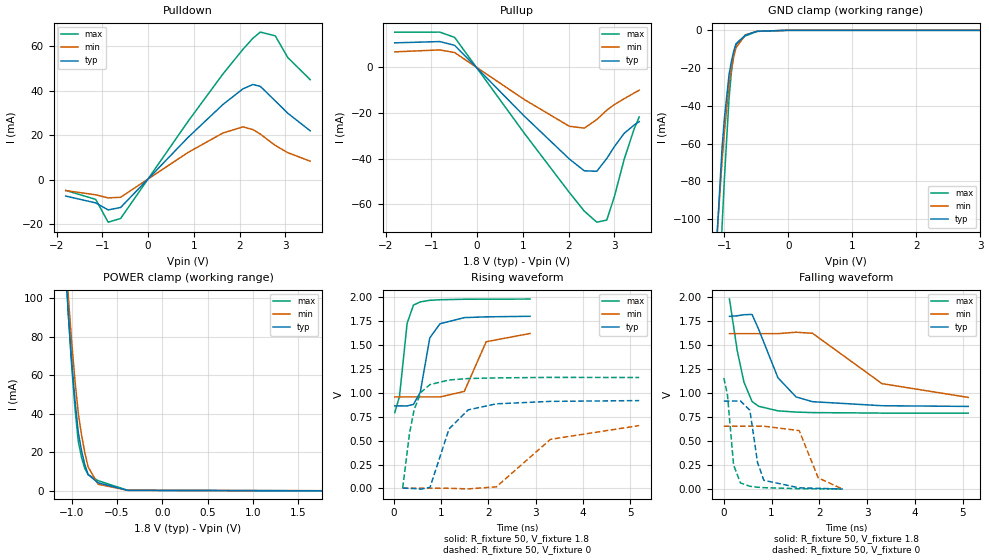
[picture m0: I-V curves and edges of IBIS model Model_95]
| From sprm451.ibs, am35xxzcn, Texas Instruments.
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| Model based on original model for BC1833DV50BTPBFZP18LL_7LM_X50
|   Sub model LL_7LM_X50_PU_ON_1P8
[model]   Model_95
|[Description]  1.8V-I/O-PU-X
|[Input Load]   PU
|[Output Drive]
|Voltage   1.8V
|Mode   I/O
Model_type   I/O
Polarity   Non-Inverting
Enable   Active-Low
Vinl =  0.63V
Vinh =  1.17V
Cref =  15pF
Rref =  100.0000M
Vref =  0V
Vmeas =  0.9
C_comp   1.952094p   1.82457p   1.99685p
[Model Spec]
Vinl   0.63V   0.567V   0.693V
Vinh   1.17V   1.053V   1.287V
[Temperature Range]   25   125   -40
[Voltage Range]   1.8   1.62   1.98
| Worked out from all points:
|   slope of the pulldown table from 0 to 0.27 V, typ, clamps not added: 44.5 ohm
|   slope of the pullup table from 0 to 0.27 V, typ, clamps not added: 47.5 ohm
|   GND clamp passes 1 mA (typ) near -0.55 V on its own axis
|   POWER clamp passes 1 mA (typ) near -0.52 V on its own axis
|   rising waveform, R_fixture 50, V_fixture 1.8: 20-80 % time 217ps typ, 287ps min, 151ps max; typ from 0.863 V to 1.8 V
|   rising waveform, R_fixture 50, V_fixture 0: 20-80 % time 444ps typ, 982ps min, 246ps max; typ from 0.003 V to 0.918 V
|   falling waveform, R_fixture 50, V_fixture 1.8: 20-80 % time 522ps typ, 1.19ns min, 279ps max; typ from 1.8 V to 0.863 V
|   falling waveform, R_fixture 50, V_fixture 0: 20-80 % time 165ps typ, 259ps min, 124ps max; typ from 0.918 V to 0.003 V
[POWER_clamp]
-1.8V     833.4mA    863.1mA    901.3mA
-1.073V   119.5mA    128.1mA    123.6mA
-1.036V   90.87mA    100.3mA    91.35mA
-1V       67.1mA     77.25mA    64.7mA
-963.6mV  46.91mA    57.21mA    42.77mA
-927.3mV  30.3mA     40.19mA    25.55mA
-890.9mV  20.62mA    28.82mA    17.13mA
-854.5mV  13.29mA    19.51mA    11.36mA
-818.2mV  8.287mA    12.24mA    8.227mA
-709.1mV  3.995mA    3.277mA    5.125mA
-381.8mV  107.6uA    86.16uA    103uA
1.764V    -143.5uA   -80.09uA   -225.9uA
[Pulldown]
-1.8V     -7.359mA   -4.884mA   -4.817mA
-1.145V   -10.42mA   -6.784mA   -8.842mA
-872.7mV  -13.57mA   -8.176mA   -19.09mA
-600mV    -12.48mA   -7.89mA    -17.42mA
872.7mV   18.97mA    12.22mA    26.15mA
1.636V    33.77mA    20.96mA    47.46mA
2.073V    40.79mA    23.72mA    58.54mA
2.291V    42.78mA    22.54mA    63.52mA
2.455V    41.93mA    20.49mA    66.32mA
2.782V    35.41mA    15.4mA     64.63mA
3.055V    29.87mA    12.14mA    54.89mA
3.545V    21.98mA    8.327mA    44.95mA
[Pullup]
-1.8V     10.75mA    6.804mA    15.41mA
-818.2mV  11.31mA    7.663mA    15.46mA
-490.9mV  9.668mA    6.495mA    13.14mA
1.036V    -21.39mA   -14.1mA    -28.91mA
2.018V    -40.11mA   -25.78mA   -54.77mA
2.345V    -45.27mA   -26.58mA   -62.92mA
2.618V    -45.47mA   -22.82mA   -67.76mA
2.836V    -39.88mA   -18.72mA   -66.82mA
3V        -34.75mA   -16.32mA   -56.72mA
3.218V    -28.82mA   -13.69mA   -40.13mA
3.436V    -25.21mA   -11.19mA   -26.84mA
3.545V    -23.75mA   -10mA      -21.69mA
[GND_clamp]
-1.8V     -667.9mA   -536.4mA   -1.146A
-1.109V   -105.8mA   -105.8mA   -173mA
-1.036V   -62.25mA   -69.36mA   -103.9mA
-1V       -46.8mA    -54.06mA   -78.94mA
-927.3mV  -23.55mA   -28.68mA   -36.16mA
-890.9mV  -16.61mA   -20.64mA   -22.39mA
-854.5mV  -11.14mA   -14.15mA   -12.79mA
-818.2mV  -7.136mA   -9.199mA   -7.36mA
-672.7mV  -2.571mA   -2.42mA    -2.99mA
-490.9mV  -507.2uA   -519uA     -573.9uA
-18.18mV  0A         0A         0A
3.6V      0A         0A         0A
[Ramp]
dV/dt_f 0.57746028/0.5248361n 0.41152909/1.2000923n 0.72359942/0.28001902n
dV/dt_r 0.56243202/0.4442558n 0.40458536/0.98019865n  0.7018131/0.24626785n
R_load = 50
[Rising Waveform]
R_fixture = 50
V_fixture = 1.8
V_fixture_min = 1.62
V_fixture_max = 1.98
23.65ps   863.1mV    956.9mV    793.2mV
123.1ps   863.1mV    956.9mV    959.5mV
284.9ps   862.9mV    956.9mV    1.727V
418.7ps   878.4mV    956.9mV    1.917V
562.4ps   1.005V     956.9mV    1.95V
764ps     1.574V     956.9mV    1.967V
979.7ps   1.722V     956.9mV    1.973V
1.493ns   1.786V     1.014V     1.978V
1.956ns   1.794V     1.534V     1.979V
2.884ns   1.8V       1.62V      1.98V
[Rising Waveform]
R_fixture = 50
V_fixture = 0
V_fixture_min = 0
V_fixture_max = 0
191.1ps   3.421mV    2.083mV    4.967mV
336.3ps   1.309mV    2.085mV    578.5mV
432.5ps   -1.637mV   2.083mV    822.1mV
573.3ps   -7.537mV   2.081mV    1.004V
768.5ps   10.99mV    2.08mV     1.086V
1.172ns   622.8mV    1.906mV    1.134V
1.576ns   821.8mV    -4.857mV   1.149V
2.172ns   884.8mV    17.01mV    1.156V
3.316ns   910.3mV    513.7mV    1.161V
5.191ns   918.4mV    657.4mV    1.16V
[Falling Waveform]
R_fixture = 50
V_fixture = 1.8
V_fixture_min = 1.62
V_fixture_max = 1.98
119.2ps   1.8V       1.62V      1.98V
280.9ps   1.806V     1.62V      1.445V
421.3ps   1.817V     1.62V      1.117V
591.6ps   1.82V      1.62V      914.6mV
728.8ps   1.667V     1.62V      864.6mV
1.133ns   1.162V     1.62V      817mV
1.513ns   962mV      1.635V     804.2mV
1.858ns   912.3mV    1.624V     798.8mV
3.314ns   870.3mV    1.1V       793.5mV
5.119ns   863.1mV    956.9mV    793.2mV
[Falling Waveform]
R_fixture = 50
V_fixture = 0
V_fixture_min = 0
V_fixture_max = 0
0s        918.4mV    657.4mV    1.16V
76.19ps   918.1mV    657.4mV    985.7mV
205.4ps   919mV      657.4mV    253.1mV
349.1ps   919.9mV    657.4mV    66.62mV
546.7ps   822.8mV    657.5mV    31.99mV
707.1ps   278.9mV    657.4mV    22.17mV
838.8ps   94.28mV    657.3mV    17.81mV
1.58ns    15.99mV    611.1mV    6.735mV
1.978ns   10.57mV    119.3mV    5.547mV
2.493ns   3.421mV    2.083mV    4.967mV
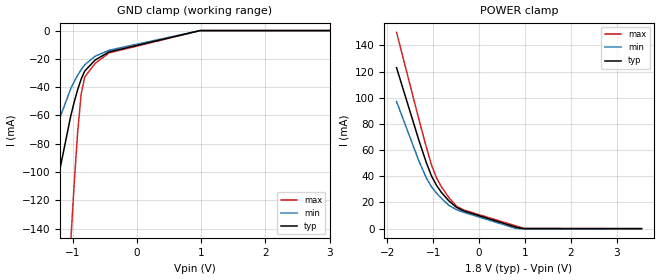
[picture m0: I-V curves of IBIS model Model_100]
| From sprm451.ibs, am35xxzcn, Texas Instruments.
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| Model based on original model for BSSTL18TCSCGPBFZ_7LM
|   Sub model HALF_TERM_SSTL_1P8
[model]   Model_100
|[Description]  1.8V-INPUT-HALF_SSTL-X-+-10%V
|[Input Load]   HALF_SSTL
|[Output Drive]
|Voltage   1.8V
|Mode   INPUT
Model_type   Input
Polarity   Non-Inverting
Vinl =  0.8
Vinh =  1
C_comp   3.009089p   2.23501p   3.950269p
[Model Spec]
Vinl   0.8   0.71   0.89
Vinh   1   0.91   1.09
[Temperature Range]   25   125   -40
[Voltage Range]   1.8   1.62   1.98
[POWER_clamp]
-1.8V     123mA      97.14mA    150mA
-1.309V   67.13mA    51.4mA     83.08mA
-1.145V   49.92mA    38.48mA    61.54mA
-1.036V   40.14mA    31.93mA    48.55mA
-927.3mV  33.07mA    27.14mA    38.76mA
-818.2mV  27.54mA    23.05mA    31.79mA
-654.5mV  21.1mA     17.78mA    23.62mA
-490.9mV  16.23mA    14.49mA    17.1mA
-327.3mV  13.47mA    12.44mA    14.19mA
818.2mV   986.3uA    9.607uA    1.978mA
981.8mV   0A         0A         178.9uA
3.545V    0A         0A         0A
[GND_clamp]
-1.8V     -238.9mA   -142.6mA   -823.4mA
-1.418V   -146.7mA   -88.57mA   -482.7mA
-1.364V   -133.7mA   -81.17mA   -433.9mA
-1.036V   -60.63mA   -41.2mA    -150.4mA
-981.8mV  -50.62mA   -36.1mA    -108.7mA
-927.3mV  -41.81mA   -31.61mA   -71.96mA
-872.7mV  -34.34mA   -27.65mA   -45mA
-818.2mV  -28.67mA   -24.24mA   -32.93mA
-654.5mV  -20.78mA   -18.11mA   -23.15mA
-436.4mV  -15.06mA   -13.89mA   -15.77mA
981.8mV   0A         0A         -1.329uA
3.545V    0A         0A         0A
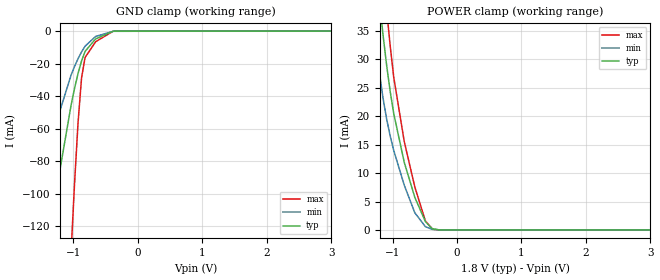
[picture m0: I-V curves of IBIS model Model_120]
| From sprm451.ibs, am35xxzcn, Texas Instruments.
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| Model based on original model for BSSTL18TCSCGPBFZ_7LM
|   Sub model NO_TERM_SSTL_0.1_1P8
[model]   Model_120
|[Description]  1.8V-INPUT-NONE_SSTL-X-+-0.1V
|[Input Load]   NONE_SSTL
|[Output Drive]
|Voltage   1.8V
|Mode   INPUT
Model_type   Input
Polarity   Non-Inverting
Vinl =  0.8
Vinh =  1
C_comp   3.009089p   2.23501p   3.95018p
[Model Spec]
Vinl   0.8   0.75   0.85
Vinh   1   0.95   1.05
[Temperature Range]   25   125   -40
[Voltage Range]   1.8   1.7   1.9
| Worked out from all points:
|   GND clamp passes 1 mA (typ) near -0.50 V on its own axis
|   POWER clamp passes 1 mA (typ) near -0.46 V on its own axis
[POWER_clamp]
-1.8V     107.1mA    82.35mA    134.1mA
-1.309V   51.28mA    36.01mA    67.01mA
-1.145V   34.1mA     23.04mA    45.4mA
-1.091V   28.94mA    19.51mA    38.64mA
-1.036V   24.34mA    16.52mA    32.36mA
-981.8mV  20.5mA     14.01mA    26.92mA
-818.2mV  11.9mA     7.881mA    15.56mA
-654.5mV  5.743mA    3.03mA     7.581mA
-490.9mV  1.486mA    587.7uA    1.604mA
-381.8mV  216.1uA    94.91uA    155.5uA
-272.7mV  11.41uA    9.683uA    3.885uA
3.545V    0A         0A         0A
[GND_clamp]
-1.8V     -229.3mA   -132mA     -818.5mA
-1.745V   -215.8mA   -124mA     -769.6mA
-1.691V   -202.2mA   -116mA     -720.6mA
-1.364V   -121.3mA   -68.84mA   -424.9mA
-1.036V   -45.75mA   -27.16mA   -136.8mA
-981.8mV  -35.29mA   -21.77mA   -94.06mA
-927.3mV  -26.08mA   -17mA      -56.49mA
-872.7mV  -18.32mA   -12.82mA   -28.79mA
-818.2mV  -12.5mA    -9.275mA   -16.24mA
-654.5mV  -4.818mA   -3.298mA   -6.567mA
-381.8mV  -101.4uA   -119.7uA   -85.8uA
3.545V    0A         0A         0A
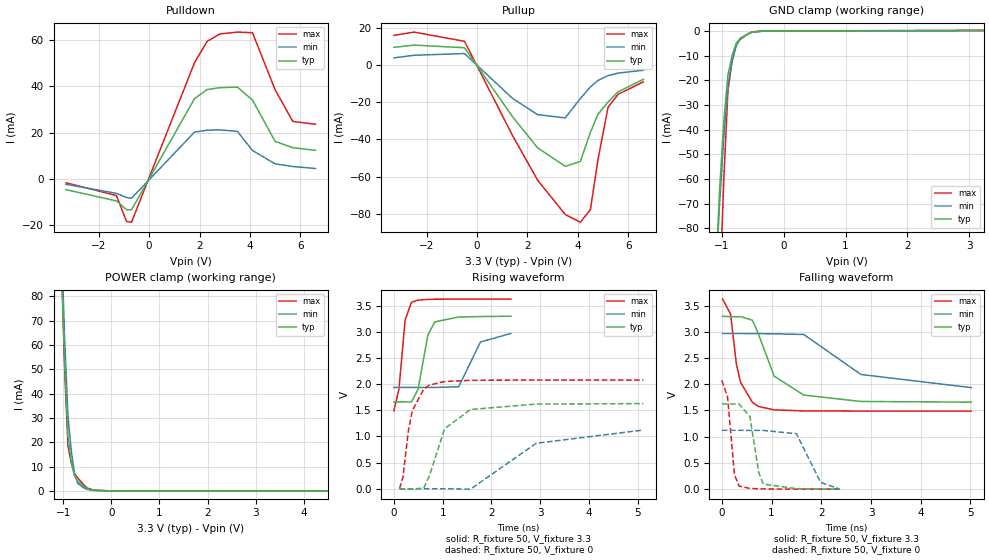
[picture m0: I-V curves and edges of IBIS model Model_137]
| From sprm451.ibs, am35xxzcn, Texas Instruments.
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| Model based on original model for BC1833DV50BTPBFHP18LL_7LM
|   Sub model HP18LL_7LM_PD_ON_3P3
[model]   Model_137
|[Description]  3.3V-I/O-PD-X
|[Input Load]   PD
|[Output Drive]
|Voltage   3.3V
|Mode   I/O
Model_type   I/O
Polarity   Non-Inverting
Enable   Active-Low
Vinl =  0.8V
Vinh =  2V
Cref =  15pF
Rref =  100.0000M
Vref =  0V
Vmeas =  1.65
C_comp   1.683006p   1.492615p   1.787227p
[Model Spec]
Vinl   0.8V   0.8V   0.8V
Vinh   2V   2V   2V
[Temperature Range]   25   125   -40
[Voltage Range]   3.3   2.97   3.63
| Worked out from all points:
|   slope of the pulldown table from 0 to 0.495 V, typ, clamps not added: 44.6 ohm
|   slope of the pullup table from 0 to 0.495 V, typ, clamps not added: 49.2 ohm
|   GND clamp passes 1 mA (typ) near -0.56 V on its own axis
|   POWER clamp passes 1 mA (typ) near -0.50 V on its own axis
|   rising waveform, R_fixture 50, V_fixture 3.3: 20-80 % time 193ps typ, 277ps min, 121ps max; typ from 1.66 V to 3.3 V
|   rising waveform, R_fixture 50, V_fixture 0: 20-80 % time 424ps typ, 977ps min, 231ps max; typ from 0 V to 1.63 V
|   falling waveform, R_fixture 50, V_fixture 3.3: 20-80 % time 504ps typ, 992ps min, 227ps max; typ from 3.3 V to 1.66 V
|   falling waveform, R_fixture 50, V_fixture 0: 20-80 % time 153ps typ, 283ps min, 108ps max; typ from 1.63 V to 0 V
[POWER_clamp]
-3.3V     2.414A     2.855A     2.597A
-1.033V   91.38mA    100.8mA    92.09mA
-966.7mV  51.62mA    61.2mA     48.76mA
-900mV    22.31mA    30.86mA    18.57mA
-833.3mV  12.32mA    16.85mA    11.59mA
-766.7mV  6.266mA    7.628mA    7.19mA
-700mV    4.145mA    3.179mA    5.382mA
-566.7mV  1.918mA    1.21mA     2.445mA
-500mV    988.1uA    615.4uA    1.197mA
-366.7mV  251uA      160.8uA    340.6uA
33.33mV   0A         0A         0A
6.6V      0A         0A         0A
[Pulldown]
-3.3V     -4.655mA   -2.337mA   -1.677mA
-1.3V     -9.504mA   -6.223mA   -7.163mA
-900mV    -13.3mA    -8.026mA   -18.36mA
-700mV    -13.35mA   -8.345mA   -18.7mA
1.8V      34.68mA    20.21mA    50.21mA
2.3V      38.61mA    21.07mA    59.44mA
2.8V      39.41mA    21.2mA     62.61mA
3.5V      39.7mA     20.55mA    63.45mA
4.1V      34.08mA    12.32mA    63.18mA
5V        16.21mA    6.501mA    38.53mA
5.7V      13.51mA    5.366mA    24.85mA
6.6V      12.35mA    4.495mA    23.63mA
[Pullup]
-3.3V     9.687mA    4.009mA    16.14mA
-2.5V     10.89mA    5.407mA    17.91mA
-500mV    9.485mA    6.336mA    12.94mA
1.4V      -27.6mA    -17.76mA   -37.69mA
2.4V      -44.47mA   -26.6mA    -61.92mA
3.5V      -54.49mA   -28.37mA   -80.48mA
4.1V      -51.87mA   -17.91mA   -84.62mA
4.5V      -36.09mA   -11.65mA   -77.77mA
4.8V      -26.39mA   -8.135mA   -50.71mA
5.2V      -19.78mA   -5.578mA   -22.57mA
5.6V      -14.26mA   -4.206mA   -15.61mA
6.6V      -7.577mA   -2.662mA   -8.942mA
[GND_clamp]
-3.3V     -1.975A    -1.766A    -3.378A
-1.1V     -99.4mA    -100.8mA   -162mA
-1.033V   -63.74mA   -69.32mA   -106.1mA
-966.7mV  -36.57mA   -43.05mA   -60.18mA
-900mV    -17.89mA   -22.01mA   -24.33mA
-833.3mV  -10.02mA   -12.39mA   -12.36mA
-766.7mV  -5.065mA   -6.03mA    -5.397mA
-700mV    -3.03mA    -2.946mA   -3.429mA
-566.7mV  -1.071mA   -1.108mA   -1.034mA
-500mV    -408.8uA   -526.2uA   -330.7uA
-300mV    -30.43uA   -31.39uA   -39.7uA
3.233V    152.3uA    93.49uA    242.6uA
[Ramp]
dV/dt_f 0.98254459/0.5034933n 0.61884461/0.9840801n  1.2814013/0.22628061n
dV/dt_r 0.98087741/0.42371489n 0.67807397/0.97305283n  1.2512137/0.23058352n
R_load = 50
[Rising Waveform]
R_fixture = 50
V_fixture = 3.3
V_fixture_min = 2.97
V_fixture_max = 3.63
515fs     1.659V     1.936V     1.489V
103.9ps   1.659V     1.936V     1.904V
230ps     1.659V     1.936V     3.223V
359.7ps   1.657V     1.936V     3.562V
495ps     1.899V     1.936V     3.604V
696.4ps   2.933V     1.936V     3.618V
839.5ps   3.188V     1.936V     3.621V
1.329ns   3.282V     1.949V     3.624V
1.775ns   3.29V      2.804V     3.624V
2.4ns     3.296V     2.968V     3.624V
[Rising Waveform]
R_fixture = 50
V_fixture = 0
V_fixture_min = 0
V_fixture_max = 0
115.2ps   7.935nV    106nV      4.134nV
185.8ps   4.524uV    -363.9nV   222.5mV
294.5ps   -180uV     -465.1nV   1.09V
376.1ps   -2.938mV   -58.61nV   1.489V
612.5ps   10.63mV    184.1nV    1.905V
731.7ps   254.7mV    -1.08nV    1.982V
1.04ns    1.147V     19.54uV    2.049V
1.57ns    1.514V     -7.658mV   2.072V
2.918ns   1.618V     868.8mV    2.077V
5.115ns   1.627V     1.122V     2.076V
[Falling Waveform]
R_fixture = 50
V_fixture = 3.3
V_fixture_min = 2.97
V_fixture_max = 3.63
15.84ps   3.296V     2.968V     3.624V
175.4ps   3.288V     2.968V     3.337V
293.5ps   3.287V     2.968V     2.381V
376ps     3.29V      2.968V     2.038V
615.9ps   3.219V     2.966V     1.653V
734.6ps   2.96V      2.964V     1.577V
1.053ns   2.154V     2.962V     1.512V
1.647ns   1.794V     2.949V     1.492V
2.797ns   1.672V     2.186V     1.489V
5.016ns   1.659V     1.936V     1.489V
[Falling Waveform]
R_fixture = 50
V_fixture = 0
V_fixture_min = 0
V_fixture_max = 0
0s        1.627V     1.122V     2.076V
114.6ps   1.623V     1.122V     1.759V
253.9ps   1.623V     1.122V     279.4mV
345.8ps   1.623V     1.122V     59mV
564.7ps   1.383V     1.121V     14.41mV
742.3ps   320.4mV    1.12V      6.655mV
832.9ps   96.23mV    1.12V      4.155mV
1.502ns   9.13mV     1.056V     127.2uV
1.985ns   3.261mV    130.5mV    14.18uV
2.377ns   7.935nV    106nV      4.134nV
